VERSION 5.7 ;
  NOWIREEXTENSIONATPIN ON ;
  DIVIDERCHAR "/" ;
  BUSBITCHARS "[]" ;
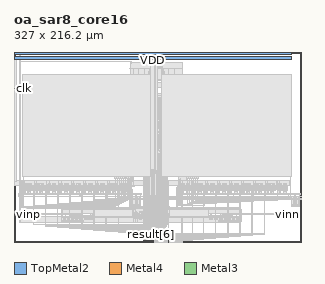
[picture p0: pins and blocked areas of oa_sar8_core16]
MACRO oa_sar8_core16
  CLASS BLOCK ;
  FOREIGN oa_sar8_core16 0.000 0.000 ;
  ORIGIN 0.000 0.000 ;
  SIZE 327.000 BY 216.200 ;
  PIN VDD
    DIRECTION INOUT ;
    USE POWER ;
    PORT
      LAYER TopMetal2 ;
        RECT 0.000 207.700 315.500 210.700 ;
    END
  END VDD
  PIN VSS
    DIRECTION INOUT ;
    USE GROUND ;
    PORT
      LAYER TopMetal2 ;
        RECT 0.000 213.200 315.500 216.200 ;
    END
  END VSS
  PIN busy
    DIRECTION OUTPUT ;
    USE SIGNAL ;
    PORT
      LAYER Metal4 ;
        RECT 158.400 0.000 158.800 1.500 ;
    END
  END busy
  PIN clk
    DIRECTION INPUT ;
    USE SIGNAL ;
    PORT
      LAYER Metal4 ;
        RECT 0.000 174.500 1.500 174.900 ;
    END
  END clk
  PIN done
    DIRECTION OUTPUT ;
    USE SIGNAL ;
    PORT
      LAYER Metal4 ;
        RECT 157.440 0.000 157.840 1.500 ;
    END
  END done
  PIN result[0]
    DIRECTION OUTPUT ;
    USE SIGNAL ;
    PORT
      LAYER Metal4 ;
        RECT 149.760 0.000 150.160 1.500 ;
    END
  END result[0]
  PIN result[1]
    DIRECTION OUTPUT ;
    USE SIGNAL ;
    PORT
      LAYER Metal4 ;
        RECT 150.720 0.000 151.120 1.500 ;
    END
  END result[1]
  PIN result[2]
    DIRECTION OUTPUT ;
    USE SIGNAL ;
    PORT
      LAYER Metal4 ;
        RECT 151.680 0.000 152.080 1.500 ;
    END
  END result[2]
  PIN result[3]
    DIRECTION OUTPUT ;
    USE SIGNAL ;
    PORT
      LAYER Metal4 ;
        RECT 152.640 0.000 153.040 1.500 ;
    END
  END result[3]
  PIN result[4]
    DIRECTION OUTPUT ;
    USE SIGNAL ;
    PORT
      LAYER Metal4 ;
        RECT 153.600 0.000 154.000 1.500 ;
    END
  END result[4]
  PIN result[5]
    DIRECTION OUTPUT ;
    USE SIGNAL ;
    PORT
      LAYER Metal4 ;
        RECT 154.560 0.000 154.960 1.500 ;
    END
  END result[5]
  PIN result[6]
    DIRECTION OUTPUT ;
    USE SIGNAL ;
    PORT
      LAYER Metal4 ;
        RECT 155.520 0.000 155.920 1.500 ;
    END
  END result[6]
  PIN result[7]
    DIRECTION OUTPUT ;
    USE SIGNAL ;
    PORT
      LAYER Metal4 ;
        RECT 156.480 0.000 156.880 1.500 ;
    END
  END result[7]
  PIN rst_n
    DIRECTION INPUT ;
    USE SIGNAL ;
    PORT
      LAYER Metal4 ;
        RECT 147.840 0.000 148.240 1.500 ;
    END
  END rst_n
  PIN start
    DIRECTION INPUT ;
    USE SIGNAL ;
    PORT
      LAYER Metal4 ;
        RECT 148.800 0.000 149.200 1.500 ;
    END
  END start
  PIN vcm
    DIRECTION INPUT ;
    USE SIGNAL ;
    PORT
      LAYER Metal4 ;
        RECT 175.400 0.000 175.800 1.500 ;
    END
  END vcm
  PIN vinn
    DIRECTION INPUT ;
    USE SIGNAL ;
    PORT
      LAYER Metal3 ;
        RECT 314.000 31.600 315.500 32.000 ;
    END
  END vinn
  PIN vinp
    DIRECTION INPUT ;
    USE SIGNAL ;
    PORT
      LAYER Metal3 ;
        RECT 0.000 31.600 1.500 32.000 ;
    END
  END vinp
  OBS
    LAYER Metal1 ;
      RECT 6.100 22.500 258.000 28.730 ;
      RECT 55.100 32.010 257.500 37.700 ;
      RECT 0.000 64.010 313.500 69.710 ;
      RECT 142.280 82.040 181.640 83.535 ;
      RECT 142.280 84.340 181.640 87.720 ;
      RECT 142.280 88.610 181.640 91.095 ;
      RECT 161.790 90.410 163.590 91.130 ;
      RECT 162.240 90.965 164.750 92.305 ;
      RECT 155.480 90.260 163.080 92.580 ;
      RECT 159.135 90.740 162.880 92.620 ;
      RECT 159.135 92.845 164.440 93.105 ;
      RECT 142.280 91.900 181.640 95.280 ;
      RECT 156.010 94.220 163.410 96.770 ;
      RECT 161.635 94.220 166.470 96.770 ;
      RECT 142.280 96.170 181.640 98.655 ;
      RECT 162.195 97.970 163.240 100.535 ;
      RECT 162.495 101.655 167.800 101.915 ;
      RECT 142.280 99.460 181.640 102.860 ;
      RECT 162.495 102.140 166.240 104.020 ;
      RECT 158.840 102.180 166.440 104.500 ;
      RECT 142.280 103.665 181.640 106.215 ;
      RECT 142.280 107.020 181.640 110.420 ;
      RECT 162.675 109.345 163.720 111.910 ;
      RECT 159.210 113.070 160.530 113.745 ;
      RECT 164.490 113.070 165.810 113.745 ;
      RECT 170.590 113.070 171.910 113.745 ;
      RECT 142.280 111.225 181.640 113.820 ;
      RECT 162.115 113.420 163.765 115.380 ;
      RECT 142.600 113.050 142.900 115.680 ;
      RECT 148.380 113.050 148.680 115.680 ;
      RECT 149.320 113.050 149.620 115.680 ;
      RECT 153.160 113.050 153.460 115.680 ;
      RECT 177.640 113.050 177.940 115.680 ;
      RECT 179.560 113.050 179.860 115.680 ;
      RECT 160.270 113.070 161.170 115.760 ;
      RECT 165.550 113.070 166.450 115.760 ;
      RECT 169.950 113.070 170.850 115.760 ;
      RECT 142.280 114.580 181.640 117.980 ;
      RECT 162.725 118.050 163.040 118.630 ;
      RECT 162.270 116.800 163.170 119.490 ;
      RECT 162.570 120.630 163.890 121.305 ;
      RECT 142.280 118.740 181.640 121.870 ;
      RECT 162.680 121.490 163.040 122.070 ;
      RECT 142.280 121.530 181.640 125.540 ;
      RECT 160.330 124.460 165.165 127.010 ;
      RECT 142.280 126.300 181.640 129.430 ;
      RECT 142.280 129.095 181.640 133.710 ;
      RECT 160.905 132.140 163.230 134.570 ;
      RECT 142.280 133.370 181.640 136.390 ;
      RECT 161.610 135.750 162.930 136.425 ;
      RECT 162.670 135.750 163.570 138.440 ;
      RECT 162.725 140.480 163.120 140.810 ;
      RECT 142.280 137.260 181.640 141.265 ;
      RECT 162.655 139.560 163.665 141.740 ;
      RECT 142.280 140.930 181.640 143.970 ;
      RECT 162.610 143.350 164.935 145.780 ;
      RECT 142.280 144.840 181.640 148.200 ;
      RECT 142.280 149.090 181.640 151.610 ;
      RECT 161.650 150.780 163.570 152.370 ;
      RECT 162.730 151.140 163.230 153.200 ;
      RECT 162.280 152.980 163.560 153.580 ;
      RECT 142.280 152.400 181.640 156.390 ;
      RECT 142.280 156.050 181.640 159.665 ;
      RECT 142.280 159.330 181.640 163.950 ;
      RECT 142.280 163.615 181.640 167.230 ;
      RECT 142.280 166.890 181.640 169.420 ;
      RECT 132.100 175.500 192.100 181.390 ;
      RECT 161.400 198.400 162.800 198.680 ;
      RECT 161.400 199.080 162.800 199.360 ;
      RECT 161.400 199.760 162.800 200.040 ;
      RECT 160.780 197.850 163.280 200.590 ;
      RECT 132.100 184.890 192.100 203.700 ;
      RECT 169.880 158.300 177.480 160.620 ;
      RECT 171.800 158.645 173.585 159.560 ;
      RECT 175.130 159.380 175.670 159.700 ;
      RECT 166.605 159.205 166.880 159.740 ;
      RECT 167.455 159.205 167.860 159.740 ;
      RECT 168.050 159.360 168.395 159.740 ;
      RECT 163.220 159.365 163.570 159.750 ;
      RECT 163.760 159.365 164.140 159.750 ;
      RECT 164.665 159.365 165.075 159.750 ;
      RECT 168.935 158.930 169.280 159.750 ;
      RECT 170.825 159.370 171.430 159.825 ;
      RECT 174.405 158.780 176.205 160.190 ;
      RECT 176.640 159.005 179.150 160.345 ;
      RECT 177.900 158.485 179.515 160.355 ;
      RECT 176.190 158.450 177.990 159.170 ;
      RECT 173.535 158.780 177.280 160.660 ;
      RECT 170.265 159.360 172.795 160.760 ;
      RECT 179.955 158.450 181.000 161.015 ;
      RECT 180.955 158.450 181.390 161.015 ;
      RECT 166.605 158.580 167.375 161.020 ;
      RECT 167.115 159.940 168.395 161.020 ;
      RECT 163.710 158.490 164.990 161.090 ;
      RECT 168.890 158.450 173.345 161.100 ;
      RECT 173.535 160.885 178.840 161.145 ;
      RECT 171.615 162.135 176.920 162.395 ;
      RECT 173.210 163.580 173.750 163.900 ;
      RECT 168.905 163.455 169.510 163.910 ;
      RECT 168.345 162.520 170.875 163.920 ;
      RECT 162.780 163.520 163.070 163.950 ;
      RECT 164.490 163.440 164.960 164.020 ;
      RECT 165.165 163.470 165.460 164.020 ;
      RECT 174.720 162.935 177.230 164.275 ;
      RECT 163.800 162.245 166.045 164.330 ;
      RECT 167.015 163.530 167.360 164.350 ;
      RECT 171.615 162.620 175.360 164.500 ;
      RECT 172.485 163.090 174.285 164.500 ;
      RECT 169.880 163.720 171.665 164.635 ;
      RECT 165.840 162.245 166.465 164.650 ;
      RECT 175.980 162.925 177.595 164.795 ;
      RECT 166.970 162.180 171.425 164.830 ;
      RECT 174.270 164.110 176.070 164.830 ;
      RECT 178.035 162.265 179.080 164.830 ;
      RECT 179.035 162.265 179.470 164.830 ;
      RECT 163.750 164.330 164.990 164.945 ;
      RECT 167.960 162.660 175.560 164.980 ;
      RECT 167.930 178.840 170.830 179.120 ;
      RECT 167.930 179.360 170.830 179.640 ;
      RECT 176.330 179.360 178.230 179.640 ;
      RECT 182.930 179.360 184.830 179.640 ;
      RECT 167.930 179.880 170.830 180.160 ;
      RECT 176.330 179.880 178.230 180.160 ;
      RECT 182.930 179.880 184.830 180.160 ;
      RECT 167.310 178.290 171.310 180.710 ;
      RECT 175.710 178.810 178.710 180.710 ;
      RECT 182.310 178.810 185.310 180.710 ;
      RECT 168.210 186.120 170.110 186.400 ;
      RECT 168.210 186.640 170.110 186.920 ;
      RECT 168.210 187.160 170.110 187.440 ;
      RECT 167.590 185.570 170.590 187.990 ;
      RECT 168.210 192.100 169.110 192.380 ;
      RECT 168.210 192.630 169.110 192.910 ;
      RECT 168.210 193.160 169.110 193.440 ;
      RECT 167.730 191.550 169.680 193.990 ;
      RECT 169.880 135.620 177.480 137.940 ;
      RECT 167.560 147.020 168.840 147.620 ;
      RECT 165.550 147.040 166.450 149.730 ;
      RECT 168.400 148.045 168.820 148.515 ;
      RECT 167.560 147.860 167.860 148.530 ;
      RECT 170.200 148.450 171.380 148.780 ;
      RECT 164.600 148.290 164.960 148.870 ;
      RECT 165.160 148.290 165.440 148.870 ;
      RECT 165.680 148.290 165.995 148.870 ;
      RECT 166.920 148.230 167.370 148.970 ;
      RECT 163.135 147.120 164.145 149.300 ;
      RECT 167.890 147.400 168.390 149.460 ;
      RECT 170.410 147.140 175.245 149.690 ;
      RECT 173.470 147.140 180.870 149.690 ;
      RECT 164.490 149.055 165.810 149.730 ;
      RECT 163.680 148.040 164.075 148.370 ;
      RECT 162.760 147.120 163.060 149.750 ;
      RECT 167.550 148.230 169.470 149.820 ;
      RECT 176.190 150.890 177.990 151.610 ;
      RECT 171.800 151.085 173.585 152.000 ;
      RECT 175.130 151.820 175.670 152.140 ;
      RECT 165.175 151.820 165.490 152.150 ;
      RECT 166.620 151.800 166.950 152.170 ;
      RECT 168.060 151.800 168.410 152.170 ;
      RECT 168.935 151.370 169.280 152.190 ;
      RECT 170.825 151.810 171.430 152.265 ;
      RECT 163.750 151.630 164.200 152.370 ;
      RECT 174.405 151.220 176.205 152.630 ;
      RECT 163.260 152.070 163.560 152.740 ;
      RECT 176.640 151.445 179.150 152.785 ;
      RECT 177.900 150.925 179.515 152.795 ;
      RECT 169.880 150.740 177.480 153.060 ;
      RECT 173.535 151.220 177.280 153.100 ;
      RECT 167.530 151.350 168.430 153.180 ;
      RECT 170.265 151.800 172.795 153.200 ;
      RECT 179.955 150.890 181.000 153.455 ;
      RECT 180.955 150.890 181.390 153.455 ;
      RECT 166.620 150.905 167.345 153.460 ;
      RECT 164.715 150.910 164.945 153.475 ;
      RECT 168.890 150.890 173.345 153.540 ;
      RECT 173.535 153.325 178.840 153.585 ;
      RECT 173.535 154.575 178.840 154.835 ;
      RECT 163.735 156.010 164.050 156.340 ;
      RECT 168.055 156.010 168.370 156.340 ;
      RECT 175.130 156.020 175.670 156.340 ;
      RECT 170.825 155.895 171.430 156.350 ;
      RECT 170.265 154.960 172.795 156.360 ;
      RECT 164.600 155.850 164.960 156.430 ;
      RECT 165.160 155.850 165.440 156.430 ;
      RECT 165.680 155.850 165.995 156.430 ;
      RECT 176.640 155.375 179.150 156.715 ;
      RECT 168.935 155.970 169.280 156.790 ;
      RECT 173.535 155.060 177.280 156.940 ;
      RECT 174.405 155.530 176.205 156.940 ;
      RECT 171.800 156.160 173.585 157.075 ;
      RECT 177.900 155.365 179.515 157.235 ;
      RECT 163.275 154.685 163.505 157.250 ;
      RECT 167.595 154.685 167.825 157.250 ;
      RECT 168.890 154.620 173.345 157.270 ;
      RECT 176.190 156.550 177.990 157.270 ;
      RECT 179.955 154.705 181.000 157.270 ;
      RECT 180.955 154.705 181.390 157.270 ;
      RECT 164.490 156.615 165.810 157.290 ;
      RECT 165.550 154.600 166.450 157.290 ;
      RECT 169.880 155.100 177.480 157.420 ;
      RECT 170.265 144.240 172.795 145.640 ;
      RECT 179.955 143.330 181.000 145.895 ;
      RECT 180.955 143.330 181.390 145.895 ;
      RECT 166.110 143.370 167.390 145.970 ;
      RECT 168.890 143.330 173.345 145.980 ;
      RECT 173.535 145.765 178.840 146.025 ;
      RECT 171.800 135.965 173.585 136.880 ;
      RECT 175.130 136.700 175.670 137.020 ;
      RECT 164.515 136.680 164.985 137.050 ;
      RECT 168.935 136.250 169.280 137.070 ;
      RECT 166.000 136.580 166.415 137.100 ;
      RECT 165.510 136.210 166.895 137.100 ;
      RECT 170.825 136.690 171.430 137.145 ;
      RECT 162.800 136.610 163.115 137.190 ;
      RECT 174.405 136.100 176.205 137.510 ;
      RECT 176.640 136.325 179.150 137.665 ;
      RECT 177.900 135.805 179.515 137.675 ;
      RECT 176.190 135.770 177.990 136.490 ;
      RECT 173.535 136.100 177.280 137.980 ;
      RECT 170.265 136.680 172.795 138.080 ;
      RECT 165.165 135.790 168.100 138.125 ;
      RECT 179.955 135.770 181.000 138.335 ;
      RECT 180.955 135.770 181.390 138.335 ;
      RECT 168.015 135.750 168.470 138.380 ;
      RECT 168.890 135.770 173.345 138.420 ;
      RECT 173.535 138.205 178.840 138.465 ;
      RECT 164.175 135.980 167.600 138.475 ;
      RECT 168.520 139.460 169.800 140.060 ;
      RECT 171.840 140.480 172.235 140.810 ;
      RECT 168.540 140.485 168.960 140.955 ;
      RECT 169.500 140.300 169.800 140.970 ;
      RECT 176.610 140.870 176.960 141.205 ;
      RECT 177.200 140.870 177.550 141.205 ;
      RECT 178.140 140.890 178.475 141.220 ;
      RECT 179.040 140.890 179.370 141.220 ;
      RECT 180.030 140.890 180.345 141.220 ;
      RECT 173.320 140.840 173.650 141.270 ;
      RECT 174.300 140.840 174.590 141.270 ;
      RECT 165.590 140.870 165.980 141.305 ;
      RECT 169.990 140.670 170.440 141.410 ;
      RECT 165.020 139.580 166.515 141.600 ;
      RECT 176.100 140.890 176.505 141.600 ;
      RECT 171.295 139.560 172.305 141.740 ;
      RECT 168.970 139.840 169.470 141.900 ;
      RECT 164.485 139.580 164.985 142.020 ;
      RECT 175.560 140.890 176.025 142.020 ;
      RECT 175.180 139.515 177.010 142.110 ;
      RECT 173.320 139.580 174.090 142.120 ;
      RECT 180.575 139.565 180.805 142.130 ;
      RECT 178.150 139.580 178.865 142.135 ;
      RECT 163.740 139.560 164.040 142.190 ;
      RECT 170.920 139.560 171.220 142.190 ;
      RECT 167.890 140.670 169.810 142.260 ;
      RECT 165.980 141.780 166.655 142.335 ;
      RECT 176.190 143.330 177.990 144.050 ;
      RECT 171.800 143.525 173.585 144.440 ;
      RECT 175.130 144.260 175.670 144.580 ;
      RECT 165.620 144.245 165.970 144.630 ;
      RECT 166.160 144.245 166.540 144.630 ;
      RECT 167.065 144.245 167.475 144.630 ;
      RECT 168.935 143.810 169.280 144.630 ;
      RECT 163.250 144.245 163.580 144.640 ;
      RECT 163.760 144.245 164.230 144.640 ;
      RECT 164.485 144.245 165.025 144.640 ;
      RECT 170.825 144.250 171.430 144.705 ;
      RECT 174.405 143.660 176.205 145.070 ;
      RECT 176.640 143.885 179.150 145.225 ;
      RECT 177.900 143.365 179.515 145.235 ;
      RECT 169.880 143.180 177.480 145.500 ;
      RECT 173.535 143.660 177.280 145.540 ;
      RECT 171.320 133.480 173.105 134.395 ;
      RECT 177.420 132.685 179.035 134.555 ;
      RECT 163.220 132.020 163.570 134.575 ;
      RECT 168.410 131.940 172.865 134.590 ;
      RECT 175.710 133.870 177.510 134.590 ;
      RECT 179.475 132.025 180.520 134.590 ;
      RECT 180.475 132.025 180.910 134.590 ;
      RECT 169.400 132.420 177.000 134.740 ;
      RECT 167.600 129.050 167.880 129.630 ;
      RECT 168.080 129.050 168.440 129.630 ;
      RECT 175.200 129.550 175.595 129.880 ;
      RECT 179.520 129.550 179.915 129.880 ;
      RECT 177.200 129.750 177.655 130.285 ;
      RECT 169.000 128.240 169.770 130.780 ;
      RECT 174.280 128.170 174.580 130.800 ;
      RECT 174.655 128.620 175.665 130.800 ;
      RECT 178.600 128.170 178.900 130.800 ;
      RECT 178.975 128.620 179.985 130.800 ;
      RECT 166.590 128.190 167.490 130.880 ;
      RECT 176.130 128.120 176.480 130.900 ;
      RECT 176.510 128.120 178.020 130.900 ;
      RECT 173.055 131.895 178.360 132.155 ;
      RECT 174.650 133.340 175.190 133.660 ;
      RECT 170.345 133.215 170.950 133.670 ;
      RECT 169.785 132.280 172.315 133.680 ;
      RECT 176.160 132.695 178.670 134.035 ;
      RECT 168.455 133.290 168.800 134.110 ;
      RECT 173.055 132.380 176.800 134.260 ;
      RECT 173.925 132.850 175.725 134.260 ;
      RECT 174.795 124.460 176.075 125.540 ;
      RECT 173.280 125.360 173.675 125.690 ;
      RECT 180.960 125.360 181.355 125.690 ;
      RECT 175.730 125.740 176.075 126.120 ;
      RECT 176.680 125.720 177.010 126.150 ;
      RECT 177.660 125.720 177.950 126.150 ;
      RECT 174.285 125.740 174.560 126.275 ;
      RECT 175.135 125.740 175.540 126.275 ;
      RECT 172.735 124.440 173.745 126.620 ;
      RECT 180.415 124.440 181.425 126.620 ;
      RECT 174.285 124.460 175.055 126.900 ;
      RECT 176.680 124.460 177.450 127.000 ;
      RECT 163.390 124.460 170.790 127.010 ;
      RECT 172.360 124.440 172.660 127.070 ;
      RECT 180.040 124.440 180.340 127.070 ;
      RECT 167.230 128.190 168.550 128.865 ;
      RECT 177.025 129.115 177.440 129.515 ;
      RECT 169.000 129.090 169.330 129.520 ;
      RECT 169.980 129.090 170.270 129.520 ;
      RECT 167.045 129.050 167.360 129.630 ;
      RECT 163.760 118.050 164.120 118.630 ;
      RECT 177.185 118.140 177.600 118.660 ;
      RECT 169.485 118.180 169.760 118.715 ;
      RECT 170.335 118.180 170.740 118.715 ;
      RECT 172.845 118.180 173.120 118.715 ;
      RECT 173.695 118.180 174.100 118.715 ;
      RECT 176.705 118.140 178.090 119.030 ;
      RECT 176.000 116.765 179.425 119.260 ;
      RECT 164.620 116.900 168.020 119.340 ;
      RECT 169.485 116.900 170.255 119.340 ;
      RECT 172.845 116.900 173.615 119.340 ;
      RECT 175.500 117.115 178.435 119.450 ;
      RECT 180.075 116.885 180.305 119.450 ;
      RECT 171.440 113.930 171.800 114.510 ;
      RECT 162.910 118.815 164.230 119.490 ;
      RECT 175.130 116.860 175.585 119.490 ;
      RECT 178.560 114.430 178.955 114.760 ;
      RECT 180.480 114.430 180.875 114.760 ;
      RECT 177.180 121.580 177.515 121.910 ;
      RECT 178.080 121.580 178.410 121.910 ;
      RECT 166.070 121.560 166.420 121.930 ;
      RECT 167.530 121.560 167.860 121.930 ;
      RECT 174.765 121.405 175.040 121.940 ;
      RECT 175.615 121.405 176.020 121.940 ;
      RECT 176.210 121.560 176.555 121.940 ;
      RECT 168.530 121.530 168.820 121.960 ;
      RECT 170.405 113.930 170.720 114.510 ;
      RECT 169.470 121.530 169.800 121.960 ;
      RECT 162.800 114.030 163.165 114.335 ;
      RECT 163.240 121.490 163.520 122.070 ;
      RECT 163.760 121.490 164.075 122.070 ;
      RECT 166.050 121.110 166.950 122.940 ;
      RECT 167.135 120.665 167.860 123.220 ;
      RECT 169.030 120.680 169.800 123.220 ;
      RECT 174.765 120.780 175.545 123.220 ;
      RECT 175.275 122.140 176.555 123.220 ;
      RECT 177.190 120.665 177.905 123.220 ;
      RECT 163.630 120.630 164.530 123.320 ;
      RECT 176.690 114.000 177.035 114.380 ;
      RECT 163.165 113.110 164.120 115.660 ;
      RECT 165.640 116.900 167.430 117.555 ;
      RECT 167.615 113.110 167.845 115.675 ;
      RECT 164.600 113.930 164.960 114.510 ;
      RECT 167.120 118.160 167.680 118.490 ;
      RECT 164.610 118.160 164.985 118.505 ;
      RECT 165.130 116.900 166.410 117.500 ;
      RECT 178.015 113.500 179.025 115.680 ;
      RECT 179.935 113.500 180.945 115.680 ;
      RECT 174.300 113.970 174.590 114.400 ;
      RECT 173.320 113.970 173.650 114.400 ;
      RECT 165.160 113.930 165.440 114.510 ;
      RECT 175.755 114.580 177.035 115.660 ;
      RECT 167.070 114.020 167.385 114.350 ;
      RECT 173.320 113.120 174.090 115.660 ;
      RECT 169.995 116.900 171.275 117.980 ;
      RECT 165.175 118.160 165.720 118.505 ;
      RECT 176.095 113.845 176.500 114.380 ;
      RECT 175.245 113.845 175.520 114.380 ;
      RECT 165.680 113.930 165.995 114.510 ;
      RECT 175.245 113.220 176.015 115.660 ;
      RECT 166.620 118.120 166.940 118.620 ;
      RECT 170.960 113.930 171.240 114.510 ;
      RECT 173.355 116.900 174.635 117.980 ;
      RECT 163.280 118.050 163.560 118.630 ;
      RECT 165.900 118.160 166.400 118.525 ;
      RECT 180.535 118.210 180.850 118.540 ;
      RECT 170.930 118.180 171.275 118.560 ;
      RECT 174.290 118.180 174.635 118.560 ;
      RECT 178.615 118.190 179.085 118.560 ;
      RECT 156.860 158.265 157.535 158.820 ;
      RECT 146.440 158.300 154.040 160.620 ;
      RECT 150.335 158.645 152.120 159.560 ;
      RECT 148.250 159.380 148.790 159.700 ;
      RECT 156.470 159.295 156.860 159.730 ;
      RECT 154.640 158.930 154.985 159.750 ;
      RECT 158.430 159.335 158.720 159.760 ;
      RECT 158.960 159.335 159.260 159.760 ;
      RECT 159.440 159.335 159.740 159.760 ;
      RECT 152.490 159.370 153.095 159.825 ;
      RECT 147.715 158.780 149.515 160.190 ;
      RECT 144.770 159.005 147.280 160.345 ;
      RECT 144.405 158.485 146.020 160.355 ;
      RECT 145.930 158.450 147.730 159.170 ;
      RECT 146.640 158.780 150.385 160.660 ;
      RECT 158.080 158.805 160.395 160.740 ;
      RECT 151.125 159.360 153.655 160.760 ;
      RECT 142.530 158.450 142.965 161.015 ;
      RECT 142.920 158.450 143.965 161.015 ;
      RECT 155.365 158.580 155.865 161.020 ;
      RECT 155.900 159.000 157.395 161.020 ;
      RECT 159.290 158.490 160.770 161.020 ;
      RECT 150.575 158.450 155.030 161.100 ;
      RECT 145.080 160.885 150.385 161.145 ;
      RECT 147.135 162.135 152.440 162.395 ;
      RECT 148.730 163.580 149.270 163.900 ;
      RECT 157.020 163.570 157.300 163.905 ;
      RECT 157.980 163.570 158.260 163.905 ;
      RECT 158.460 163.570 158.740 163.905 ;
      RECT 144.425 163.455 145.030 163.910 ;
      RECT 143.865 162.520 146.395 163.920 ;
      RECT 159.420 163.550 159.750 163.920 ;
      RECT 160.860 163.550 161.210 163.920 ;
      RECT 161.800 163.520 162.130 163.950 ;
      RECT 150.240 162.935 152.750 164.275 ;
      RECT 142.535 163.530 142.880 164.350 ;
      RECT 160.330 162.540 161.230 164.370 ;
      RECT 147.135 162.620 150.880 164.500 ;
      RECT 148.005 163.090 149.805 164.500 ;
      RECT 145.400 163.720 147.185 164.635 ;
      RECT 151.500 162.925 153.115 164.795 ;
      RECT 157.535 162.290 158.905 164.800 ;
      RECT 161.800 162.260 162.570 164.800 ;
      RECT 159.420 162.260 160.120 164.815 ;
      RECT 142.490 162.180 146.945 164.830 ;
      RECT 149.790 164.110 151.590 164.830 ;
      RECT 153.555 162.265 154.600 164.830 ;
      RECT 154.555 162.265 154.990 164.830 ;
      RECT 143.480 162.660 151.080 164.980 ;
      RECT 147.900 166.935 148.180 167.270 ;
      RECT 148.860 166.935 149.140 167.270 ;
      RECT 149.340 166.935 149.620 167.270 ;
      RECT 152.710 166.940 153.040 167.270 ;
      RECT 153.605 166.940 153.940 167.270 ;
      RECT 150.300 166.920 150.630 167.290 ;
      RECT 151.740 166.920 152.090 167.290 ;
      RECT 151.210 166.470 152.110 168.300 ;
      RECT 148.415 166.040 149.785 168.550 ;
      RECT 150.300 166.025 151.000 168.580 ;
      RECT 153.215 166.025 153.930 168.580 ;
      RECT 153.370 178.840 156.270 179.120 ;
      RECT 139.370 179.360 141.270 179.640 ;
      RECT 145.970 179.360 147.870 179.640 ;
      RECT 153.370 179.360 156.270 179.640 ;
      RECT 139.370 179.880 141.270 180.160 ;
      RECT 145.970 179.880 147.870 180.160 ;
      RECT 153.370 179.880 156.270 180.160 ;
      RECT 138.890 178.810 141.890 180.710 ;
      RECT 145.490 178.810 148.490 180.710 ;
      RECT 152.890 178.290 156.890 180.710 ;
      RECT 154.090 186.120 155.990 186.400 ;
      RECT 154.090 186.640 155.990 186.920 ;
      RECT 154.090 187.160 155.990 187.440 ;
      RECT 153.610 185.570 156.610 187.990 ;
      RECT 155.090 192.100 155.990 192.380 ;
      RECT 155.090 192.630 155.990 192.910 ;
      RECT 155.090 193.160 155.990 193.440 ;
      RECT 154.520 191.550 156.470 193.990 ;
      RECT 146.440 135.620 154.040 137.940 ;
      RECT 150.015 147.015 155.320 147.275 ;
      RECT 145.370 147.060 149.825 149.710 ;
      RECT 151.610 148.460 152.150 148.780 ;
      RECT 147.305 148.335 147.910 148.790 ;
      RECT 146.745 147.400 149.275 148.800 ;
      RECT 159.380 148.400 159.680 148.825 ;
      RECT 159.860 148.305 160.185 148.825 ;
      RECT 160.400 148.400 160.690 148.825 ;
      RECT 153.120 147.815 155.630 149.155 ;
      RECT 145.415 148.410 145.760 149.230 ;
      RECT 158.725 147.420 161.040 149.355 ;
      RECT 150.015 147.500 153.760 149.380 ;
      RECT 150.885 147.970 152.685 149.380 ;
      RECT 148.280 148.600 150.065 149.515 ;
      RECT 158.350 147.140 159.830 149.670 ;
      RECT 154.380 147.805 155.995 149.675 ;
      RECT 144.075 147.125 144.305 149.690 ;
      RECT 144.535 148.450 144.850 148.780 ;
      RECT 152.670 148.990 154.470 149.710 ;
      RECT 156.435 147.145 157.480 149.710 ;
      RECT 157.435 147.145 157.870 149.710 ;
      RECT 146.360 147.540 153.960 149.860 ;
      RECT 144.030 151.820 144.345 152.150 ;
      RECT 157.340 151.820 158.520 152.150 ;
      RECT 159.920 151.795 160.335 152.195 ;
      RECT 162.300 152.085 162.720 152.555 ;
      RECT 146.400 152.230 146.795 152.560 ;
      RECT 159.705 152.430 160.160 152.965 ;
      RECT 147.850 150.910 155.250 153.460 ;
      RECT 153.475 150.910 158.310 153.460 ;
      RECT 144.575 150.910 144.805 153.475 ;
      RECT 145.480 150.850 145.780 153.480 ;
      RECT 145.855 151.300 146.865 153.480 ;
      RECT 159.340 150.800 160.850 153.580 ;
      RECT 160.880 150.800 161.230 153.580 ;
      RECT 148.840 154.580 150.120 155.180 ;
      RECT 149.680 155.605 150.100 156.075 ;
      RECT 148.840 155.420 149.140 156.090 ;
      RECT 153.035 156.025 153.440 156.330 ;
      RECT 153.680 156.025 154.045 156.330 ;
      RECT 155.550 156.010 155.865 156.340 ;
      RECT 158.940 156.010 159.220 156.345 ;
      RECT 159.900 156.010 160.180 156.345 ;
      RECT 160.380 156.010 160.660 156.345 ;
      RECT 151.240 155.960 151.570 156.390 ;
      RECT 152.220 155.960 152.510 156.390 ;
      RECT 148.200 155.790 148.650 156.530 ;
      RECT 152.995 154.980 154.645 156.940 ;
      RECT 149.170 154.960 149.670 157.020 ;
      RECT 151.240 154.700 152.010 157.240 ;
      RECT 159.545 154.730 160.825 157.240 ;
      RECT 154.045 154.700 155.000 157.250 ;
      RECT 156.095 154.685 156.325 157.250 ;
      RECT 148.830 155.790 150.750 157.380 ;
      RECT 147.135 145.765 152.440 146.025 ;
      RECT 155.525 140.890 155.860 141.220 ;
      RECT 161.815 140.890 162.130 141.220 ;
      RECT 145.930 135.770 147.730 136.490 ;
      RECT 148.805 140.730 149.120 141.310 ;
      RECT 149.360 140.730 149.640 141.310 ;
      RECT 150.335 135.965 152.120 136.880 ;
      RECT 149.840 140.730 150.200 141.310 ;
      RECT 148.250 136.700 148.790 137.020 ;
      RECT 159.420 136.700 159.755 137.030 ;
      RECT 160.320 136.700 160.650 137.030 ;
      RECT 144.885 139.580 145.905 141.855 ;
      RECT 154.640 136.250 154.985 137.070 ;
      RECT 145.305 139.615 146.915 141.915 ;
      RECT 155.490 136.735 155.865 137.080 ;
      RECT 156.055 136.735 156.600 137.080 ;
      RECT 156.780 136.715 157.280 137.080 ;
      RECT 158.000 136.750 158.560 137.080 ;
      RECT 143.595 139.565 143.825 142.130 ;
      RECT 161.355 139.565 161.585 142.130 ;
      RECT 155.135 139.580 155.850 142.135 ;
      RECT 148.350 139.480 149.250 142.170 ;
      RECT 157.500 136.620 157.820 137.120 ;
      RECT 148.990 141.495 150.310 142.170 ;
      RECT 152.490 136.690 153.095 137.145 ;
      RECT 161.720 136.610 162.080 137.190 ;
      RECT 162.280 136.610 162.560 137.190 ;
      RECT 147.440 141.775 147.790 142.335 ;
      RECT 147.715 136.100 149.515 137.510 ;
      RECT 144.770 136.325 147.280 137.665 ;
      RECT 149.790 143.330 151.590 144.050 ;
      RECT 144.405 135.805 146.020 137.675 ;
      RECT 145.400 143.525 147.185 144.440 ;
      RECT 142.490 143.330 146.945 145.980 ;
      RECT 148.730 144.260 149.270 144.580 ;
      RECT 156.060 144.260 156.395 144.590 ;
      RECT 156.960 144.260 157.290 144.590 ;
      RECT 157.950 144.260 158.265 144.590 ;
      RECT 160.855 144.260 161.170 144.590 ;
      RECT 142.535 143.810 142.880 144.630 ;
      RECT 146.640 136.100 150.385 137.980 ;
      RECT 151.125 136.680 153.655 138.080 ;
      RECT 142.530 135.770 142.965 138.335 ;
      RECT 142.920 135.770 143.965 138.335 ;
      RECT 144.425 144.250 145.030 144.705 ;
      RECT 148.005 143.660 149.805 145.070 ;
      RECT 150.240 143.885 152.750 145.225 ;
      RECT 151.500 143.365 153.115 145.235 ;
      RECT 143.480 143.180 151.080 145.500 ;
      RECT 155.500 135.900 158.900 138.340 ;
      RECT 156.010 137.740 157.290 138.340 ;
      RECT 156.520 137.685 158.310 138.340 ;
      RECT 147.135 143.660 150.880 145.540 ;
      RECT 159.430 135.785 160.145 138.340 ;
      RECT 150.575 135.770 155.030 138.420 ;
      RECT 143.865 144.240 146.395 145.640 ;
      RECT 145.080 138.205 150.385 138.465 ;
      RECT 153.555 143.330 154.600 145.895 ;
      RECT 154.555 143.330 154.990 145.895 ;
      RECT 146.535 139.615 147.855 140.530 ;
      RECT 156.070 143.345 156.785 145.900 ;
      RECT 162.270 143.345 162.620 145.900 ;
      RECT 158.495 143.350 158.725 145.915 ;
      RECT 160.395 143.350 160.625 145.915 ;
      RECT 146.435 140.740 146.730 141.215 ;
      RECT 146.930 140.740 147.225 141.215 ;
      RECT 144.055 140.890 144.370 141.220 ;
      RECT 154.630 140.890 154.960 141.220 ;
      RECT 145.950 124.360 146.850 127.050 ;
      RECT 148.300 124.340 149.810 127.120 ;
      RECT 149.840 124.340 150.190 127.120 ;
      RECT 143.095 125.770 143.410 126.100 ;
      RECT 142.600 132.000 142.900 134.630 ;
      RECT 145.000 132.000 145.300 134.630 ;
      RECT 160.120 125.770 161.300 126.100 ;
      RECT 147.665 134.220 148.340 134.775 ;
      RECT 152.210 125.740 152.555 126.120 ;
      RECT 153.125 125.740 153.470 126.120 ;
      RECT 161.790 129.090 162.120 129.520 ;
      RECT 142.490 128.210 146.945 130.860 ;
      RECT 148.880 125.725 149.295 126.125 ;
      RECT 144.050 125.720 144.340 126.150 ;
      RECT 144.990 125.720 145.320 126.150 ;
      RECT 146.405 125.610 146.720 126.190 ;
      RECT 147.135 130.645 152.440 130.905 ;
      RECT 146.960 125.610 147.240 126.190 ;
      RECT 147.440 125.610 147.800 126.190 ;
      RECT 155.045 132.020 156.325 133.100 ;
      RECT 143.520 132.920 143.915 133.250 ;
      RECT 156.330 125.640 156.800 126.220 ;
      RECT 145.920 132.920 146.315 133.250 ;
      RECT 157.005 125.670 157.300 126.220 ;
      RECT 158.940 129.140 159.275 129.470 ;
      RECT 159.840 129.140 160.170 129.470 ;
      RECT 150.765 125.740 151.040 126.275 ;
      RECT 151.615 125.740 152.020 126.275 ;
      RECT 142.535 128.690 142.880 129.510 ;
      RECT 157.885 133.290 158.295 133.675 ;
      RECT 153.660 125.740 154.065 126.275 ;
      RECT 154.640 125.740 154.915 126.275 ;
      RECT 158.820 133.290 159.200 133.675 ;
      RECT 159.390 133.290 159.740 133.675 ;
      RECT 160.815 133.280 161.355 133.675 ;
      RECT 155.640 124.445 157.885 126.530 ;
      RECT 161.610 133.280 162.080 133.675 ;
      RECT 144.425 129.130 145.030 129.585 ;
      RECT 148.005 128.540 149.805 129.950 ;
      RECT 157.680 124.445 158.305 126.850 ;
      RECT 150.240 128.765 152.750 130.105 ;
      RECT 151.500 128.245 153.115 130.115 ;
      RECT 162.260 133.280 162.590 133.675 ;
      RECT 155.045 133.300 155.390 133.680 ;
      RECT 160.850 129.090 161.140 129.520 ;
      RECT 150.765 124.460 151.535 126.900 ;
      RECT 143.480 128.060 151.080 130.380 ;
      RECT 150.290 133.280 150.580 133.710 ;
      RECT 154.145 124.460 154.915 126.900 ;
      RECT 144.550 124.460 145.320 127.000 ;
      RECT 142.635 124.445 142.865 127.010 ;
      RECT 151.230 133.280 151.560 133.710 ;
      RECT 147.135 128.540 150.880 130.420 ;
      RECT 157.970 131.950 159.250 134.550 ;
      RECT 143.865 129.120 146.395 130.520 ;
      RECT 146.590 126.375 147.910 127.050 ;
      RECT 148.340 133.310 148.730 133.745 ;
      RECT 155.580 133.300 155.985 133.835 ;
      RECT 156.560 133.300 156.835 133.835 ;
      RECT 153.555 128.210 154.600 130.775 ;
      RECT 150.790 132.020 151.560 134.560 ;
      RECT 147.805 132.020 149.300 134.040 ;
      RECT 145.400 128.405 147.185 129.320 ;
      RECT 148.730 129.140 149.270 129.460 ;
      RECT 155.590 126.530 156.830 127.145 ;
      RECT 142.975 132.000 143.985 134.180 ;
      RECT 145.375 132.000 146.385 134.180 ;
      RECT 149.790 128.210 151.590 128.930 ;
      RECT 154.555 128.210 154.990 130.775 ;
      RECT 148.665 124.955 149.120 125.490 ;
      RECT 158.950 128.225 159.665 130.780 ;
      RECT 151.275 124.460 152.555 125.540 ;
      RECT 161.350 128.240 162.120 130.780 ;
      RECT 153.125 124.460 154.405 125.540 ;
      RECT 149.335 132.020 149.835 134.460 ;
      RECT 156.055 132.020 156.835 134.460 ;
      RECT 150.240 114.430 150.635 114.760 ;
      RECT 145.970 121.530 146.260 121.960 ;
      RECT 142.975 113.500 143.985 115.680 ;
      RECT 160.400 113.930 160.715 114.510 ;
      RECT 160.735 116.880 161.745 119.060 ;
      RECT 146.470 120.680 147.240 123.220 ;
      RECT 142.920 116.905 143.965 119.470 ;
      RECT 157.990 113.120 158.760 115.660 ;
      RECT 147.880 120.680 148.650 123.220 ;
      RECT 145.930 118.750 147.730 119.470 ;
      RECT 147.715 117.730 149.515 119.140 ;
      RECT 155.085 120.780 155.865 123.220 ;
      RECT 147.365 114.430 147.760 114.760 ;
      RECT 144.770 117.575 147.280 118.915 ;
      RECT 155.370 118.815 156.690 119.490 ;
      RECT 157.500 121.575 157.780 121.910 ;
      RECT 156.530 121.560 156.875 121.940 ;
      RECT 147.295 113.500 148.305 115.680 ;
      RECT 161.765 121.580 162.100 121.910 ;
      RECT 158.590 118.815 159.910 119.490 ;
      RECT 155.595 122.140 156.875 123.220 ;
      RECT 152.490 118.095 153.095 118.550 ;
      RECT 161.375 120.665 162.090 123.220 ;
      RECT 156.560 118.050 156.875 118.630 ;
      RECT 158.460 121.575 158.740 121.910 ;
      RECT 146.910 121.530 147.240 121.960 ;
      RECT 155.085 113.220 155.865 115.660 ;
      RECT 155.480 118.050 155.840 118.630 ;
      RECT 146.640 117.260 150.385 119.140 ;
      RECT 155.595 114.580 156.875 115.660 ;
      RECT 154.080 114.430 154.475 114.760 ;
      RECT 147.880 121.530 148.210 121.960 ;
      RECT 150.335 118.360 152.120 119.275 ;
      RECT 148.860 121.530 149.150 121.960 ;
      RECT 157.490 113.970 157.780 114.400 ;
      RECT 160.360 116.880 160.660 119.510 ;
      RECT 151.125 117.160 153.655 118.560 ;
      RECT 158.940 121.575 159.220 121.910 ;
      RECT 158.405 118.050 158.720 118.630 ;
      RECT 153.535 113.500 154.545 115.680 ;
      RECT 158.960 118.050 159.240 118.630 ;
      RECT 162.155 114.030 162.560 114.335 ;
      RECT 158.430 113.970 158.760 114.400 ;
      RECT 151.200 121.990 151.595 122.320 ;
      RECT 143.520 114.430 143.915 114.760 ;
      RECT 152.165 121.990 152.560 122.320 ;
      RECT 143.090 121.530 143.380 121.960 ;
      RECT 145.080 116.775 150.385 117.035 ;
      RECT 159.320 113.930 159.680 114.510 ;
      RECT 160.870 121.580 161.200 121.910 ;
      RECT 155.085 113.845 155.360 114.380 ;
      RECT 159.440 118.050 159.800 118.630 ;
      RECT 156.530 114.000 156.875 114.380 ;
      RECT 159.880 113.930 160.160 114.510 ;
      RECT 146.440 117.300 154.040 119.620 ;
      RECT 145.000 113.120 145.770 115.660 ;
      RECT 145.000 113.970 145.330 114.400 ;
      RECT 150.280 120.610 150.580 123.240 ;
      RECT 144.030 121.530 144.360 121.960 ;
      RECT 150.655 121.060 151.665 123.240 ;
      RECT 150.575 116.820 155.030 119.470 ;
      RECT 152.095 121.060 153.105 123.240 ;
      RECT 155.935 113.845 156.340 114.380 ;
      RECT 153.180 120.610 153.480 123.240 ;
      RECT 144.405 117.565 146.020 119.435 ;
      RECT 148.250 118.220 148.790 118.540 ;
      RECT 156.430 116.800 157.330 119.490 ;
      RECT 145.980 113.970 146.270 114.400 ;
      RECT 154.640 118.170 154.985 118.990 ;
      RECT 156.040 118.050 156.320 118.630 ;
      RECT 152.220 113.970 152.510 114.400 ;
      RECT 157.950 116.800 158.850 119.490 ;
      RECT 158.105 120.680 159.385 123.190 ;
      RECT 142.530 116.905 142.965 119.470 ;
      RECT 151.240 113.120 152.010 115.660 ;
      RECT 149.695 113.500 150.705 115.680 ;
      RECT 151.240 113.970 151.570 114.400 ;
      RECT 155.085 121.405 155.360 121.940 ;
      RECT 155.935 121.405 156.340 121.940 ;
      RECT 161.280 117.800 161.675 118.130 ;
      RECT 143.590 120.680 144.360 123.220 ;
      RECT 81.170 26.960 83.070 27.240 ;
      RECT 80.690 25.890 83.690 27.790 ;
      RECT 80.010 25.210 84.230 28.470 ;
      RECT 6.100 53.500 133.900 54.100 ;
      RECT 7.700 54.500 144.600 55.100 ;
      RECT 78.430 55.700 81.800 60.510 ;
      RECT 78.890 64.690 81.890 67.110 ;
      RECT 81.170 26.440 83.070 26.720 ;
      RECT 146.590 90.390 147.910 91.065 ;
      RECT 152.830 90.390 154.150 91.065 ;
      RECT 144.550 90.440 145.320 92.980 ;
      RECT 143.135 90.430 143.365 92.995 ;
      RECT 149.340 90.370 149.640 93.000 ;
      RECT 151.260 90.370 151.560 93.000 ;
      RECT 154.490 90.410 158.945 93.060 ;
      RECT 145.950 90.390 146.850 93.080 ;
      RECT 152.190 90.390 153.090 93.080 ;
      RECT 142.495 101.760 143.505 103.940 ;
      RECT 144.415 101.760 145.425 103.940 ;
      RECT 149.695 101.760 150.705 103.940 ;
      RECT 154.015 101.760 155.025 103.940 ;
      RECT 155.935 101.760 156.945 103.940 ;
      RECT 148.895 101.765 149.125 104.330 ;
      RECT 157.850 101.700 162.305 104.350 ;
      RECT 143.580 101.760 143.880 104.390 ;
      RECT 145.500 101.760 145.800 104.390 ;
      RECT 150.780 101.760 151.080 104.390 ;
      RECT 153.640 101.760 153.940 104.390 ;
      RECT 157.020 101.760 157.320 104.390 ;
      RECT 157.895 103.050 158.240 103.870 ;
      RECT 142.565 102.680 142.960 103.010 ;
      RECT 144.485 102.680 144.880 103.010 ;
      RECT 149.765 102.680 150.160 103.010 ;
      RECT 154.560 102.680 154.955 103.010 ;
      RECT 156.005 102.680 156.400 103.010 ;
      RECT 160.760 103.240 162.545 104.155 ;
      RECT 146.950 101.780 147.720 104.320 ;
      RECT 151.720 101.780 152.490 104.320 ;
      RECT 148.350 103.090 148.665 103.420 ;
      RECT 159.785 102.975 160.390 103.430 ;
      RECT 159.225 102.040 161.755 103.440 ;
      RECT 146.450 103.040 146.740 103.470 ;
      RECT 147.390 103.040 147.720 103.470 ;
      RECT 151.720 103.040 152.050 103.470 ;
      RECT 152.700 103.040 152.990 103.470 ;
      RECT 149.790 105.530 151.590 106.250 ;
      RECT 145.400 105.725 147.185 106.640 ;
      RECT 148.730 106.460 149.270 106.780 ;
      RECT 155.550 106.460 155.865 106.790 ;
      RECT 142.535 106.010 142.880 106.830 ;
      RECT 144.425 106.450 145.030 106.905 ;
      RECT 157.920 106.870 158.315 107.200 ;
      RECT 159.840 106.870 160.235 107.200 ;
      RECT 161.760 106.870 162.155 107.200 ;
      RECT 148.005 105.860 149.805 107.270 ;
      RECT 150.240 106.085 152.750 107.425 ;
      RECT 151.500 105.565 153.115 107.435 ;
      RECT 143.480 105.380 151.080 107.700 ;
      RECT 147.135 105.860 150.880 107.740 ;
      RECT 143.865 106.440 146.395 107.840 ;
      RECT 153.555 105.530 154.600 108.095 ;
      RECT 154.555 105.530 154.990 108.095 ;
      RECT 156.095 105.550 156.325 108.115 ;
      RECT 157.000 105.490 157.300 108.120 ;
      RECT 157.375 105.940 158.385 108.120 ;
      RECT 158.920 105.490 159.220 108.120 ;
      RECT 159.295 105.940 160.305 108.120 ;
      RECT 160.840 105.490 161.140 108.120 ;
      RECT 161.215 105.940 162.225 108.120 ;
      RECT 142.490 105.530 146.945 108.180 ;
      RECT 147.135 107.965 152.440 108.225 ;
      RECT 156.255 109.215 161.560 109.475 ;
      RECT 142.565 110.240 142.960 110.570 ;
      RECT 147.365 110.240 147.760 110.570 ;
      RECT 157.850 110.660 158.390 110.980 ;
      RECT 153.545 110.535 154.150 110.990 ;
      RECT 152.985 109.600 155.515 111.000 ;
      RECT 145.445 110.490 145.760 111.070 ;
      RECT 146.000 110.490 146.280 111.070 ;
      RECT 146.480 110.490 146.840 111.070 ;
      RECT 149.240 110.490 149.600 111.070 ;
      RECT 149.800 110.490 150.080 111.070 ;
      RECT 150.320 110.490 150.635 111.070 ;
      RECT 159.360 110.015 161.870 111.355 ;
      RECT 151.655 110.610 152.000 111.430 ;
      RECT 142.495 109.320 143.505 111.500 ;
      RECT 147.295 109.320 148.305 111.500 ;
      RECT 156.255 109.700 160.000 111.580 ;
      RECT 157.125 110.170 158.925 111.580 ;
      RECT 154.520 110.800 156.305 111.715 ;
      RECT 160.620 110.005 162.235 111.875 ;
      RECT 151.610 109.260 156.065 111.910 ;
      RECT 158.910 111.190 160.710 111.910 ;
      RECT 144.990 109.240 145.890 111.930 ;
      RECT 145.630 111.255 146.950 111.930 ;
      RECT 149.130 111.255 150.450 111.930 ;
      RECT 150.190 109.240 151.090 111.930 ;
      RECT 143.580 109.320 143.880 111.950 ;
      RECT 148.380 109.320 148.680 111.950 ;
      RECT 152.600 109.740 160.200 112.060 ;
      RECT 147.895 98.900 148.210 99.230 ;
      RECT 151.175 98.450 151.520 99.270 ;
      RECT 143.090 98.850 143.380 99.280 ;
      RECT 144.030 98.850 144.360 99.280 ;
      RECT 153.065 98.890 153.670 99.345 ;
      RECT 145.445 98.810 145.760 99.390 ;
      RECT 146.000 98.810 146.280 99.390 ;
      RECT 146.480 98.810 146.840 99.390 ;
      RECT 149.285 98.810 149.600 99.390 ;
      RECT 149.840 98.810 150.120 99.390 ;
      RECT 150.320 98.810 150.680 99.390 ;
      RECT 156.645 98.300 158.445 99.710 ;
      RECT 158.880 98.525 161.390 99.865 ;
      RECT 160.140 98.005 161.755 99.875 ;
      RECT 152.120 97.820 159.720 100.140 ;
      RECT 147.135 94.095 152.440 94.355 ;
      RECT 155.775 98.300 159.520 100.180 ;
      RECT 152.505 98.880 155.035 100.280 ;
      RECT 143.590 98.000 144.360 100.540 ;
      RECT 147.435 97.990 147.665 100.555 ;
      RECT 151.130 97.970 155.585 100.620 ;
      RECT 144.990 97.950 145.890 100.640 ;
      RECT 148.830 97.950 149.730 100.640 ;
      RECT 155.775 100.405 161.080 100.665 ;
      RECT 158.430 97.970 160.230 98.690 ;
      RECT 154.040 98.165 155.825 99.080 ;
      RECT 157.370 98.900 157.910 99.220 ;
      RECT 148.730 95.540 149.270 95.860 ;
      RECT 144.425 95.415 145.030 95.870 ;
      RECT 143.865 94.480 146.395 95.880 ;
      RECT 150.240 94.895 152.750 96.235 ;
      RECT 142.535 95.490 142.880 96.310 ;
      RECT 147.135 94.580 150.880 96.460 ;
      RECT 145.400 95.680 147.185 96.595 ;
      RECT 151.500 94.885 153.115 96.755 ;
      RECT 157.400 90.605 159.185 91.520 ;
      RECT 160.730 91.340 161.270 91.660 ;
      RECT 142.590 91.340 142.905 91.670 ;
      RECT 154.535 90.890 154.880 91.710 ;
      RECT 144.050 91.290 144.340 91.720 ;
      RECT 144.990 91.290 145.320 91.720 ;
      RECT 156.425 91.330 157.030 91.785 ;
      RECT 146.405 91.250 146.745 91.830 ;
      RECT 146.960 91.250 147.240 91.830 ;
      RECT 147.440 91.250 147.800 91.830 ;
      RECT 152.645 91.250 152.985 91.830 ;
      RECT 153.200 91.250 153.480 91.830 ;
      RECT 153.680 91.250 154.040 91.830 ;
      RECT 148.325 91.750 148.720 92.080 ;
      RECT 150.245 91.750 150.640 92.080 ;
      RECT 160.005 90.740 161.805 92.150 ;
      RECT 148.005 95.050 149.805 96.460 ;
      RECT 155.865 91.320 158.395 92.720 ;
      RECT 142.490 94.140 146.945 96.790 ;
      RECT 149.790 96.070 151.590 96.790 ;
      RECT 148.255 90.820 149.265 93.000 ;
      RECT 153.555 94.225 154.600 96.790 ;
      RECT 150.175 90.820 151.185 93.000 ;
      RECT 154.555 94.225 154.990 96.790 ;
      RECT 143.480 94.620 151.080 96.940 ;
      RECT 145.630 97.950 146.950 98.625 ;
      RECT 149.470 97.950 150.790 98.625 ;
      RECT 155.550 87.970 155.865 88.300 ;
      RECT 152.490 87.855 153.095 88.310 ;
      RECT 151.125 86.920 153.655 88.320 ;
      RECT 144.770 87.335 147.280 88.675 ;
      RECT 154.640 87.930 154.985 88.750 ;
      RECT 156.895 86.640 157.905 88.820 ;
      RECT 158.815 86.640 159.825 88.820 ;
      RECT 160.735 86.640 161.745 88.820 ;
      RECT 147.715 87.490 149.515 88.900 ;
      RECT 146.640 87.020 150.385 88.900 ;
      RECT 150.335 88.120 152.120 89.035 ;
      RECT 144.405 87.325 146.020 89.195 ;
      RECT 156.095 86.645 156.325 89.210 ;
      RECT 142.530 86.665 142.965 89.230 ;
      RECT 142.920 86.665 143.965 89.230 ;
      RECT 145.930 88.510 147.730 89.230 ;
      RECT 150.575 86.580 155.030 89.230 ;
      RECT 157.980 86.640 158.280 89.270 ;
      RECT 159.900 86.640 160.200 89.270 ;
      RECT 161.820 86.640 162.120 89.270 ;
      RECT 146.440 87.060 154.040 89.380 ;
      RECT 152.670 82.850 154.470 83.570 ;
      RECT 148.280 83.045 150.065 83.960 ;
      RECT 151.610 83.780 152.150 84.100 ;
      RECT 145.415 83.330 145.760 84.150 ;
      RECT 143.570 83.730 143.860 84.160 ;
      RECT 144.510 83.730 144.840 84.160 ;
      RECT 158.930 83.730 159.220 84.160 ;
      RECT 159.870 83.730 160.200 84.160 ;
      RECT 160.850 83.730 161.140 84.160 ;
      RECT 161.790 83.730 162.120 84.160 ;
      RECT 147.305 83.770 147.910 84.225 ;
      RECT 150.885 83.180 152.685 84.590 ;
      RECT 153.120 83.405 155.630 84.745 ;
      RECT 154.380 82.885 155.995 84.755 ;
      RECT 146.360 82.700 153.960 85.020 ;
      RECT 150.015 83.180 153.760 85.060 ;
      RECT 146.745 83.760 149.275 85.160 ;
      RECT 156.435 82.850 157.480 85.415 ;
      RECT 157.435 82.850 157.870 85.415 ;
      RECT 144.070 82.880 144.840 85.420 ;
      RECT 159.430 82.880 160.200 85.420 ;
      RECT 161.350 82.880 162.120 85.420 ;
      RECT 145.370 82.850 149.825 85.500 ;
      RECT 150.015 85.285 155.320 85.545 ;
      RECT 145.080 86.535 150.385 86.795 ;
      RECT 156.965 87.560 157.360 87.890 ;
      RECT 158.885 87.560 159.280 87.890 ;
      RECT 160.805 87.560 161.200 87.890 ;
      RECT 148.250 87.980 148.790 88.300 ;
      RECT 79.370 65.240 81.270 65.520 ;
      RECT 44.570 65.760 46.470 66.040 ;
      RECT 51.770 65.760 53.670 66.040 ;
      RECT 58.370 65.760 60.270 66.040 ;
      RECT 65.570 65.760 67.470 66.040 ;
      RECT 72.170 65.760 74.070 66.040 ;
      RECT 79.370 65.760 81.270 66.040 ;
      RECT 44.570 66.280 46.470 66.560 ;
      RECT 51.770 66.280 53.670 66.560 ;
      RECT 58.370 66.280 60.270 66.560 ;
      RECT 65.570 66.280 67.470 66.560 ;
      RECT 72.170 66.280 74.070 66.560 ;
      RECT 79.370 66.280 81.270 66.560 ;
      RECT 44.090 64.690 47.090 67.110 ;
      RECT 51.290 64.690 54.290 67.110 ;
      RECT 57.890 64.690 60.890 67.110 ;
      RECT 65.090 64.690 68.090 67.110 ;
      RECT 71.690 64.690 74.690 67.110 ;
      RECT 44.690 57.960 45.590 58.240 ;
      RECT 51.990 57.960 52.890 58.240 ;
      RECT 58.490 57.960 59.390 58.240 ;
      RECT 65.790 57.960 66.690 58.240 ;
      RECT 72.290 57.960 73.190 58.240 ;
      RECT 79.590 57.960 80.490 58.240 ;
      RECT 44.690 58.480 45.590 58.760 ;
      RECT 51.990 58.480 52.890 58.760 ;
      RECT 58.490 58.480 59.390 58.760 ;
      RECT 65.790 58.480 66.690 58.760 ;
      RECT 72.290 58.480 73.190 58.760 ;
      RECT 79.590 58.480 80.490 58.760 ;
      RECT 44.690 59.000 45.590 59.280 ;
      RECT 51.990 59.000 52.890 59.280 ;
      RECT 58.490 59.000 59.390 59.280 ;
      RECT 65.790 59.000 66.690 59.280 ;
      RECT 72.290 59.000 73.190 59.280 ;
      RECT 79.590 59.000 80.490 59.280 ;
      RECT 44.210 57.410 46.210 59.830 ;
      RECT 51.510 57.410 53.510 59.830 ;
      RECT 58.010 57.410 60.010 59.830 ;
      RECT 65.310 57.410 67.310 59.830 ;
      RECT 71.810 57.410 73.810 59.830 ;
      RECT 79.110 57.410 81.110 59.830 ;
      RECT 43.330 55.700 46.750 60.510 ;
      RECT 50.830 55.700 54.200 60.510 ;
      RECT 57.130 55.700 60.550 60.510 ;
      RECT 64.630 55.700 68.000 60.510 ;
      RECT 70.930 55.700 74.350 60.510 ;
      RECT 44.570 65.240 46.470 65.520 ;
      RECT 51.770 65.240 53.670 65.520 ;
      RECT 58.370 65.240 60.270 65.520 ;
      RECT 65.570 65.240 67.470 65.520 ;
      RECT 72.170 65.240 74.070 65.520 ;
      RECT 30.290 64.690 33.290 67.110 ;
      RECT 37.490 64.690 40.490 67.110 ;
      RECT 16.970 66.280 18.870 66.560 ;
      RECT 24.170 66.280 26.070 66.560 ;
      RECT 10.590 59.000 11.490 59.280 ;
      RECT 17.090 59.000 17.990 59.280 ;
      RECT 24.390 59.000 25.290 59.280 ;
      RECT 30.890 59.000 31.790 59.280 ;
      RECT 38.190 59.000 39.090 59.280 ;
      RECT 30.770 66.280 32.670 66.560 ;
      RECT 37.970 66.280 39.870 66.560 ;
      RECT 16.970 65.760 18.870 66.040 ;
      RECT 5.400 54.500 7.400 55.100 ;
      RECT 10.590 57.960 11.490 58.240 ;
      RECT 17.090 57.960 17.990 58.240 ;
      RECT 10.110 57.410 12.110 59.830 ;
      RECT 16.610 57.410 18.610 59.830 ;
      RECT 23.910 57.410 25.910 59.830 ;
      RECT 30.410 57.410 32.410 59.830 ;
      RECT 37.710 57.410 39.710 59.830 ;
      RECT 24.390 57.960 25.290 58.240 ;
      RECT 30.890 57.960 31.790 58.240 ;
      RECT 38.190 57.960 39.090 58.240 ;
      RECT 24.170 65.760 26.070 66.040 ;
      RECT 30.770 65.760 32.670 66.040 ;
      RECT 37.970 65.760 39.870 66.040 ;
      RECT 9.430 55.700 12.800 60.510 ;
      RECT 15.730 55.700 19.150 60.510 ;
      RECT 23.230 55.700 26.600 60.510 ;
      RECT 29.530 55.700 32.950 60.510 ;
      RECT 37.030 55.700 40.400 60.510 ;
      RECT 10.370 65.760 12.270 66.040 ;
      RECT 10.370 66.280 12.270 66.560 ;
      RECT 9.890 64.690 12.890 67.110 ;
      RECT 10.590 58.480 11.490 58.760 ;
      RECT 17.090 58.480 17.990 58.760 ;
      RECT 10.370 65.240 12.270 65.520 ;
      RECT 16.970 65.240 18.870 65.520 ;
      RECT 24.170 65.240 26.070 65.520 ;
      RECT 30.770 65.240 32.670 65.520 ;
      RECT 37.970 65.240 39.870 65.520 ;
      RECT 24.390 58.480 25.290 58.760 ;
      RECT 30.890 58.480 31.790 58.760 ;
      RECT 38.190 58.480 39.090 58.760 ;
      RECT 16.490 64.690 19.490 67.110 ;
      RECT 23.690 64.690 26.690 67.110 ;
      RECT 61.490 26.690 62.390 26.970 ;
      RECT 56.890 26.160 57.790 26.440 ;
      RECT 56.890 27.220 57.790 27.500 ;
      RECT 61.490 27.220 62.390 27.500 ;
      RECT 66.090 27.220 66.990 27.500 ;
      RECT 70.690 27.220 71.590 27.500 ;
      RECT 70.690 26.690 71.590 26.970 ;
      RECT 74.810 25.610 77.810 28.030 ;
      RECT 75.290 26.160 77.190 26.440 ;
      RECT 66.090 26.690 66.990 26.970 ;
      RECT 66.090 26.160 66.990 26.440 ;
      RECT 70.690 26.160 71.590 26.440 ;
      RECT 56.410 25.610 58.410 28.050 ;
      RECT 61.010 25.610 63.010 28.050 ;
      RECT 65.610 25.610 67.610 28.050 ;
      RECT 70.210 25.610 72.210 28.050 ;
      RECT 61.490 26.160 62.390 26.440 ;
      RECT 75.290 26.680 77.190 26.960 ;
      RECT 56.890 26.690 57.790 26.970 ;
      RECT 75.290 27.200 77.190 27.480 ;
      RECT 120.290 64.690 123.290 67.110 ;
      RECT 120.510 57.410 122.510 59.830 ;
      RECT 119.830 55.700 123.200 60.510 ;
      RECT 120.770 65.240 122.670 65.520 ;
      RECT 120.770 65.760 122.670 66.040 ;
      RECT 120.770 66.280 122.670 66.560 ;
      RECT 126.130 55.700 129.550 60.510 ;
      RECT 127.010 57.410 129.010 59.830 ;
      RECT 127.370 65.240 129.270 65.520 ;
      RECT 127.490 58.480 128.390 58.760 ;
      RECT 127.490 57.960 128.390 58.240 ;
      RECT 127.370 65.760 129.270 66.040 ;
      RECT 126.890 64.690 129.890 67.110 ;
      RECT 127.370 66.280 129.270 66.560 ;
      RECT 127.490 59.000 128.390 59.280 ;
      RECT 93.390 57.960 94.290 58.240 ;
      RECT 99.890 57.960 100.790 58.240 ;
      RECT 107.190 57.960 108.090 58.240 ;
      RECT 113.690 57.960 114.590 58.240 ;
      RECT 120.990 57.960 121.890 58.240 ;
      RECT 113.090 64.690 116.090 67.110 ;
      RECT 84.730 55.700 88.150 60.510 ;
      RECT 92.230 55.700 95.600 60.510 ;
      RECT 98.530 55.700 101.950 60.510 ;
      RECT 106.030 55.700 109.400 60.510 ;
      RECT 112.330 55.700 115.750 60.510 ;
      RECT 85.490 64.690 88.490 67.110 ;
      RECT 92.690 64.690 95.690 67.110 ;
      RECT 86.090 58.480 86.990 58.760 ;
      RECT 85.970 65.240 87.870 65.520 ;
      RECT 93.170 65.240 95.070 65.520 ;
      RECT 99.770 65.240 101.670 65.520 ;
      RECT 106.970 65.240 108.870 65.520 ;
      RECT 113.570 65.240 115.470 65.520 ;
      RECT 85.610 57.410 87.610 59.830 ;
      RECT 92.910 57.410 94.910 59.830 ;
      RECT 93.390 58.480 94.290 58.760 ;
      RECT 99.890 58.480 100.790 58.760 ;
      RECT 107.190 58.480 108.090 58.760 ;
      RECT 113.690 58.480 114.590 58.760 ;
      RECT 120.990 58.480 121.890 58.760 ;
      RECT 99.410 57.410 101.410 59.830 ;
      RECT 85.970 65.760 87.870 66.040 ;
      RECT 93.170 65.760 95.070 66.040 ;
      RECT 99.770 65.760 101.670 66.040 ;
      RECT 106.970 65.760 108.870 66.040 ;
      RECT 113.570 65.760 115.470 66.040 ;
      RECT 106.710 57.410 108.710 59.830 ;
      RECT 113.210 57.410 115.210 59.830 ;
      RECT 86.090 59.000 86.990 59.280 ;
      RECT 93.390 59.000 94.290 59.280 ;
      RECT 99.890 59.000 100.790 59.280 ;
      RECT 107.190 59.000 108.090 59.280 ;
      RECT 113.690 59.000 114.590 59.280 ;
      RECT 85.970 66.280 87.870 66.560 ;
      RECT 93.170 66.280 95.070 66.560 ;
      RECT 99.770 66.280 101.670 66.560 ;
      RECT 106.970 66.280 108.870 66.560 ;
      RECT 113.570 66.280 115.470 66.560 ;
      RECT 99.290 64.690 102.290 67.110 ;
      RECT 106.490 64.690 109.490 67.110 ;
      RECT 120.990 59.000 121.890 59.280 ;
      RECT 86.090 57.960 86.990 58.240 ;
      RECT 85.710 25.210 89.930 28.470 ;
      RECT 86.870 26.960 88.770 27.240 ;
      RECT 86.870 26.440 88.770 26.720 ;
      RECT 86.390 25.890 89.390 27.790 ;
      RECT 143.590 25.960 144.490 26.240 ;
      RECT 135.790 41.960 137.690 42.240 ;
      RECT 140.790 41.960 142.690 42.240 ;
      RECT 135.790 42.480 137.690 42.760 ;
      RECT 140.790 42.480 142.690 42.760 ;
      RECT 143.470 33.760 145.370 34.040 ;
      RECT 157.270 33.760 159.170 34.040 ;
      RECT 136.870 34.280 138.770 34.560 ;
      RECT 143.470 34.280 145.370 34.560 ;
      RECT 157.270 34.280 159.170 34.560 ;
      RECT 136.390 32.690 139.390 35.110 ;
      RECT 142.990 32.690 145.990 35.110 ;
      RECT 135.790 43.000 137.690 43.280 ;
      RECT 140.790 43.000 142.690 43.280 ;
      RECT 135.310 41.410 138.310 43.830 ;
      RECT 140.310 41.410 143.310 43.830 ;
      RECT 134.630 39.960 138.850 44.510 ;
      RECT 139.630 39.960 143.850 44.510 ;
      RECT 156.790 32.690 159.790 35.110 ;
      RECT 157.390 27.000 158.290 27.280 ;
      RECT 137.090 26.480 137.990 26.760 ;
      RECT 157.390 26.480 158.290 26.760 ;
      RECT 143.590 27.000 144.490 27.280 ;
      RECT 143.470 33.240 145.370 33.520 ;
      RECT 157.390 25.960 158.290 26.240 ;
      RECT 143.590 26.480 144.490 26.760 ;
      RECT 137.090 25.960 137.990 26.240 ;
      RECT 136.870 33.240 138.770 33.520 ;
      RECT 136.610 25.410 138.610 27.830 ;
      RECT 143.110 25.410 145.110 27.830 ;
      RECT 156.910 25.410 158.910 27.830 ;
      RECT 157.270 33.240 159.170 33.520 ;
      RECT 136.870 33.760 138.770 34.040 ;
      RECT 137.090 27.000 137.990 27.280 ;
      RECT 187.700 53.500 313.500 54.100 ;
      RECT 187.700 54.500 325.500 55.100 ;
      RECT 163.500 90.445 165.115 92.315 ;
      RECT 165.555 90.410 166.600 92.975 ;
      RECT 166.555 90.410 166.990 92.975 ;
      RECT 167.560 90.440 168.330 92.980 ;
      RECT 170.410 90.430 175.245 92.980 ;
      RECT 173.470 90.430 180.870 92.980 ;
      RECT 173.215 101.760 174.225 103.940 ;
      RECT 175.615 101.760 176.625 103.940 ;
      RECT 178.495 101.760 179.505 103.940 ;
      RECT 180.415 101.760 181.425 103.940 ;
      RECT 170.910 101.680 171.810 104.370 ;
      RECT 174.300 101.760 174.600 104.390 ;
      RECT 175.240 101.760 175.540 104.390 ;
      RECT 178.120 101.760 178.420 104.390 ;
      RECT 180.040 101.760 180.340 104.390 ;
      RECT 179.955 109.345 181.000 111.910 ;
      RECT 180.955 109.345 181.390 111.910 ;
      RECT 166.410 111.255 167.730 111.930 ;
      RECT 167.470 109.240 168.370 111.930 ;
      RECT 169.880 109.740 177.480 112.060 ;
      RECT 164.690 110.600 164.980 111.030 ;
      RECT 165.630 110.600 165.960 111.030 ;
      RECT 166.520 110.490 166.880 111.070 ;
      RECT 167.080 110.490 167.360 111.070 ;
      RECT 167.600 110.490 167.915 111.070 ;
      RECT 176.640 110.015 179.150 111.355 ;
      RECT 173.285 102.680 173.680 103.010 ;
      RECT 176.160 102.680 176.555 103.010 ;
      RECT 179.040 102.680 179.435 103.010 ;
      RECT 180.960 102.680 181.355 103.010 ;
      RECT 164.090 103.100 164.630 103.420 ;
      RECT 170.825 110.535 171.430 110.990 ;
      RECT 170.265 109.600 172.795 111.000 ;
      RECT 171.365 102.930 171.680 103.510 ;
      RECT 171.920 102.930 172.200 103.510 ;
      RECT 172.400 102.930 172.760 103.510 ;
      RECT 165.600 102.455 168.110 103.795 ;
      RECT 168.935 110.610 169.280 111.430 ;
      RECT 173.535 109.700 177.280 111.580 ;
      RECT 174.405 110.170 176.205 111.580 ;
      RECT 171.800 110.800 173.585 111.715 ;
      RECT 163.365 102.610 165.165 104.020 ;
      RECT 166.860 102.445 168.475 104.315 ;
      RECT 165.150 103.630 166.950 104.350 ;
      RECT 168.915 101.785 169.960 104.350 ;
      RECT 169.915 101.785 170.350 104.350 ;
      RECT 177.900 110.005 179.515 111.875 ;
      RECT 171.550 103.695 172.870 104.370 ;
      RECT 165.190 109.340 165.960 111.880 ;
      RECT 163.675 109.345 164.110 111.910 ;
      RECT 168.890 109.260 173.345 111.910 ;
      RECT 176.190 111.190 177.990 111.910 ;
      RECT 176.190 105.530 177.990 106.250 ;
      RECT 171.800 105.725 173.585 106.640 ;
      RECT 175.130 106.460 175.670 106.780 ;
      RECT 163.255 106.460 163.570 106.790 ;
      RECT 168.935 106.010 169.280 106.830 ;
      RECT 167.090 106.410 167.380 106.840 ;
      RECT 168.030 106.410 168.360 106.840 ;
      RECT 170.825 106.450 171.430 106.905 ;
      RECT 165.120 106.870 165.515 107.200 ;
      RECT 174.405 105.860 176.205 107.270 ;
      RECT 176.640 106.085 179.150 107.425 ;
      RECT 177.900 105.565 179.515 107.435 ;
      RECT 169.880 105.380 177.480 107.700 ;
      RECT 173.535 105.860 177.280 107.740 ;
      RECT 170.265 106.440 172.795 107.840 ;
      RECT 179.955 105.530 181.000 108.095 ;
      RECT 180.955 105.530 181.390 108.095 ;
      RECT 167.590 105.560 168.360 108.100 ;
      RECT 162.795 105.550 163.025 108.115 ;
      RECT 164.200 105.490 164.500 108.120 ;
      RECT 164.575 105.940 165.585 108.120 ;
      RECT 168.890 105.530 173.345 108.180 ;
      RECT 173.535 107.965 178.840 108.225 ;
      RECT 173.535 109.215 178.840 109.475 ;
      RECT 175.130 110.660 175.670 110.980 ;
      RECT 175.130 95.540 175.670 95.860 ;
      RECT 170.825 95.415 171.430 95.870 ;
      RECT 170.265 94.480 172.795 95.880 ;
      RECT 176.640 94.895 179.150 96.235 ;
      RECT 168.935 95.490 169.280 96.310 ;
      RECT 173.535 94.580 177.280 96.460 ;
      RECT 174.405 95.050 176.205 96.460 ;
      RECT 171.800 95.680 173.585 96.595 ;
      RECT 177.900 94.885 179.515 96.755 ;
      RECT 168.095 94.205 168.325 96.770 ;
      RECT 168.890 94.140 173.345 96.790 ;
      RECT 176.190 96.070 177.990 96.790 ;
      RECT 179.955 94.225 181.000 96.790 ;
      RECT 180.955 94.225 181.390 96.790 ;
      RECT 169.880 94.620 177.480 96.940 ;
      RECT 166.410 97.950 167.730 98.625 ;
      RECT 176.190 97.970 177.990 98.690 ;
      RECT 171.800 98.165 173.585 99.080 ;
      RECT 175.130 98.900 175.670 99.220 ;
      RECT 164.690 98.850 164.980 99.280 ;
      RECT 165.630 98.850 165.960 99.280 ;
      RECT 170.825 98.890 171.430 99.345 ;
      RECT 166.520 98.810 166.880 99.390 ;
      RECT 167.080 98.810 167.360 99.390 ;
      RECT 167.600 98.810 167.915 99.390 ;
      RECT 168.935 98.450 169.280 99.415 ;
      RECT 174.405 98.300 176.205 99.710 ;
      RECT 176.640 98.525 179.150 99.865 ;
      RECT 177.900 98.005 179.515 99.875 ;
      RECT 169.880 97.820 177.480 100.140 ;
      RECT 173.535 98.300 177.280 100.180 ;
      RECT 170.265 98.880 172.795 100.280 ;
      RECT 163.195 97.970 163.630 100.535 ;
      RECT 179.955 97.970 181.000 100.535 ;
      RECT 180.955 97.970 181.390 100.535 ;
      RECT 165.190 98.000 165.960 100.540 ;
      RECT 168.890 97.970 173.345 100.620 ;
      RECT 167.470 97.950 168.370 100.640 ;
      RECT 173.535 100.405 178.840 100.665 ;
      RECT 170.200 91.340 171.380 91.670 ;
      RECT 167.560 91.290 167.890 91.720 ;
      RECT 168.540 91.290 168.830 91.720 ;
      RECT 173.535 94.095 178.840 94.355 ;
      RECT 165.500 95.530 166.680 95.860 ;
      RECT 167.550 95.530 167.865 95.860 ;
      RECT 167.080 86.640 167.380 89.270 ;
      RECT 169.880 87.060 177.480 89.380 ;
      RECT 173.470 82.830 174.790 83.505 ;
      RECT 171.895 83.780 172.210 84.110 ;
      RECT 162.770 83.730 163.060 84.160 ;
      RECT 163.710 83.730 164.040 84.160 ;
      RECT 167.080 83.730 167.410 84.160 ;
      RECT 168.060 83.730 168.350 84.160 ;
      RECT 177.170 83.730 177.460 84.160 ;
      RECT 178.110 83.730 178.440 84.160 ;
      RECT 173.285 83.690 173.600 84.270 ;
      RECT 173.840 83.690 174.120 84.270 ;
      RECT 174.320 83.690 174.680 84.270 ;
      RECT 165.125 84.190 165.520 84.520 ;
      RECT 170.400 84.190 170.795 84.520 ;
      RECT 176.160 84.190 176.555 84.520 ;
      RECT 180.000 84.190 180.395 84.520 ;
      RECT 163.270 82.880 164.040 85.420 ;
      RECT 167.080 82.880 167.850 85.420 ;
      RECT 177.670 82.880 178.440 85.420 ;
      RECT 171.435 82.870 171.665 85.435 ;
      RECT 165.055 83.260 166.065 85.440 ;
      RECT 166.140 82.810 166.440 85.440 ;
      RECT 169.480 82.810 169.780 85.440 ;
      RECT 169.855 83.260 170.865 85.440 ;
      RECT 175.240 82.810 175.540 85.440 ;
      RECT 175.615 83.260 176.625 85.440 ;
      RECT 179.080 82.810 179.380 85.440 ;
      RECT 179.455 83.260 180.465 85.440 ;
      RECT 172.830 82.830 173.730 85.520 ;
      RECT 173.535 86.535 178.840 86.795 ;
      RECT 163.680 87.560 164.075 87.890 ;
      RECT 165.125 87.560 165.520 87.890 ;
      RECT 168.000 87.560 168.395 87.890 ;
      RECT 175.130 87.980 175.670 88.300 ;
      RECT 170.825 87.855 171.430 88.310 ;
      RECT 170.265 86.920 172.795 88.320 ;
      RECT 176.640 87.335 179.150 88.675 ;
      RECT 168.935 87.930 169.280 88.750 ;
      RECT 163.135 86.640 164.145 88.820 ;
      RECT 165.055 86.640 166.065 88.820 ;
      RECT 167.455 86.640 168.465 88.820 ;
      RECT 173.535 87.020 177.280 88.900 ;
      RECT 174.405 87.490 176.205 88.900 ;
      RECT 171.800 88.120 173.585 89.035 ;
      RECT 177.900 87.325 179.515 89.195 ;
      RECT 168.890 86.580 173.345 89.230 ;
      RECT 176.190 88.510 177.990 89.230 ;
      RECT 179.955 86.665 181.000 89.230 ;
      RECT 180.955 86.665 181.390 89.230 ;
      RECT 162.760 86.640 163.060 89.270 ;
      RECT 166.140 86.640 166.440 89.270 ;
      RECT 190.590 57.960 191.490 58.240 ;
      RECT 224.570 65.760 226.470 66.040 ;
      RECT 240.410 27.220 241.310 27.500 ;
      RECT 231.770 65.760 233.670 66.040 ;
      RECT 237.890 64.690 240.890 67.110 ;
      RECT 238.370 65.760 240.270 66.040 ;
      RECT 218.190 57.960 219.090 58.240 ;
      RECT 197.090 57.960 197.990 58.240 ;
      RECT 223.230 26.960 225.130 27.240 ;
      RECT 190.590 58.480 191.490 58.760 ;
      RECT 197.090 58.480 197.990 58.760 ;
      RECT 204.390 58.480 205.290 58.760 ;
      RECT 210.890 58.480 211.790 58.760 ;
      RECT 186.800 53.600 187.200 54.000 ;
      RECT 218.190 58.480 219.090 58.760 ;
      RECT 190.370 65.240 192.270 65.520 ;
      RECT 196.970 65.240 198.870 65.520 ;
      RECT 204.170 65.240 206.070 65.520 ;
      RECT 239.790 25.610 241.790 28.050 ;
      RECT 204.390 57.960 205.290 58.240 ;
      RECT 210.770 65.240 212.670 65.520 ;
      RECT 217.970 65.240 219.870 65.520 ;
      RECT 210.890 57.960 211.790 58.240 ;
      RECT 228.930 26.440 230.830 26.720 ;
      RECT 171.070 33.760 172.970 34.040 ;
      RECT 224.570 65.240 226.470 65.520 ;
      RECT 171.190 27.000 172.090 27.280 ;
      RECT 222.070 25.210 226.290 28.470 ;
      RECT 227.770 25.210 231.990 28.470 ;
      RECT 190.590 59.000 191.490 59.280 ;
      RECT 197.090 59.000 197.990 59.280 ;
      RECT 204.390 59.000 205.290 59.280 ;
      RECT 223.230 26.440 225.130 26.720 ;
      RECT 231.770 65.240 233.670 65.520 ;
      RECT 240.410 26.690 241.310 26.970 ;
      RECT 238.370 65.240 240.270 65.520 ;
      RECT 210.890 59.000 211.790 59.280 ;
      RECT 222.610 25.890 225.610 27.790 ;
      RECT 218.190 59.000 219.090 59.280 ;
      RECT 170.590 32.690 173.590 35.110 ;
      RECT 190.370 66.280 192.270 66.560 ;
      RECT 196.970 66.280 198.870 66.560 ;
      RECT 204.170 66.280 206.070 66.560 ;
      RECT 210.770 66.280 212.670 66.560 ;
      RECT 228.310 25.890 231.310 27.790 ;
      RECT 171.070 34.280 172.970 34.560 ;
      RECT 190.110 57.410 192.110 59.830 ;
      RECT 196.610 57.410 198.610 59.830 ;
      RECT 203.910 57.410 205.910 59.830 ;
      RECT 217.970 66.280 219.870 66.560 ;
      RECT 224.570 66.280 226.470 66.560 ;
      RECT 231.770 66.280 233.670 66.560 ;
      RECT 238.370 66.280 240.270 66.560 ;
      RECT 224.690 58.480 225.590 58.760 ;
      RECT 189.430 55.700 192.800 60.510 ;
      RECT 195.730 55.700 199.150 60.510 ;
      RECT 203.230 55.700 206.600 60.510 ;
      RECT 210.410 57.410 212.410 59.830 ;
      RECT 231.990 58.480 232.890 58.760 ;
      RECT 217.710 57.410 219.710 59.830 ;
      RECT 238.490 58.480 239.390 58.760 ;
      RECT 224.210 57.410 226.210 59.830 ;
      RECT 209.530 55.700 212.950 60.510 ;
      RECT 224.690 57.960 225.590 58.240 ;
      RECT 217.030 55.700 220.400 60.510 ;
      RECT 224.690 59.000 225.590 59.280 ;
      RECT 231.990 59.000 232.890 59.280 ;
      RECT 223.330 55.700 226.750 60.510 ;
      RECT 238.490 59.000 239.390 59.280 ;
      RECT 230.830 55.700 234.200 60.510 ;
      RECT 237.130 55.700 240.550 60.510 ;
      RECT 228.930 26.960 230.830 27.240 ;
      RECT 171.190 26.480 172.090 26.760 ;
      RECT 190.370 65.760 192.270 66.040 ;
      RECT 231.990 57.960 232.890 58.240 ;
      RECT 231.510 57.410 233.510 59.830 ;
      RECT 238.490 57.960 239.390 58.240 ;
      RECT 240.410 26.160 241.310 26.440 ;
      RECT 196.970 65.760 198.870 66.040 ;
      RECT 234.810 26.680 236.710 26.960 ;
      RECT 234.810 27.200 236.710 27.480 ;
      RECT 171.190 25.960 172.090 26.240 ;
      RECT 234.810 26.160 236.710 26.440 ;
      RECT 170.710 25.410 172.710 27.830 ;
      RECT 204.170 65.760 206.070 66.040 ;
      RECT 171.070 33.240 172.970 33.520 ;
      RECT 238.010 57.410 240.010 59.830 ;
      RECT 189.890 64.690 192.890 67.110 ;
      RECT 210.770 65.760 212.670 66.040 ;
      RECT 196.490 64.690 199.490 67.110 ;
      RECT 234.190 25.610 237.190 28.030 ;
      RECT 203.690 64.690 206.690 67.110 ;
      RECT 210.290 64.690 213.290 67.110 ;
      RECT 217.490 64.690 220.490 67.110 ;
      RECT 224.090 64.690 227.090 67.110 ;
      RECT 217.970 65.760 219.870 66.040 ;
      RECT 231.290 64.690 234.290 67.110 ;
      RECT 300.770 65.760 302.670 66.040 ;
      RECT 307.370 65.760 309.270 66.040 ;
      RECT 286.970 65.240 288.870 65.520 ;
      RECT 293.570 65.240 295.470 65.520 ;
      RECT 300.770 65.240 302.670 65.520 ;
      RECT 307.370 65.240 309.270 65.520 ;
      RECT 293.090 64.690 296.090 67.110 ;
      RECT 286.030 55.700 289.400 60.510 ;
      RECT 292.330 55.700 295.750 60.510 ;
      RECT 299.830 55.700 303.200 60.510 ;
      RECT 306.130 55.700 309.550 60.510 ;
      RECT 287.190 58.480 288.090 58.760 ;
      RECT 293.690 58.480 294.590 58.760 ;
      RECT 300.990 58.480 301.890 58.760 ;
      RECT 300.290 64.690 303.290 67.110 ;
      RECT 307.490 58.480 308.390 58.760 ;
      RECT 287.190 57.960 288.090 58.240 ;
      RECT 286.970 66.280 288.870 66.560 ;
      RECT 293.570 66.280 295.470 66.560 ;
      RECT 300.770 66.280 302.670 66.560 ;
      RECT 307.370 66.280 309.270 66.560 ;
      RECT 293.690 57.960 294.590 58.240 ;
      RECT 306.890 64.690 309.890 67.110 ;
      RECT 300.990 57.960 301.890 58.240 ;
      RECT 307.490 57.960 308.390 58.240 ;
      RECT 287.190 59.000 288.090 59.280 ;
      RECT 286.710 57.410 288.710 59.830 ;
      RECT 293.210 57.410 295.210 59.830 ;
      RECT 293.690 59.000 294.590 59.280 ;
      RECT 300.510 57.410 302.510 59.830 ;
      RECT 300.990 59.000 301.890 59.280 ;
      RECT 307.490 59.000 308.390 59.280 ;
      RECT 307.010 57.410 309.010 59.830 ;
      RECT 286.490 64.690 289.490 67.110 ;
      RECT 286.970 65.760 288.870 66.040 ;
      RECT 293.570 65.760 295.470 66.040 ;
      RECT 245.570 66.280 247.470 66.560 ;
      RECT 258.430 55.700 261.800 60.510 ;
      RECT 273.170 65.240 275.070 65.520 ;
      RECT 272.690 64.690 275.690 67.110 ;
      RECT 273.390 57.960 274.290 58.240 ;
      RECT 252.170 66.280 254.070 66.560 ;
      RECT 259.370 66.280 261.270 66.560 ;
      RECT 265.970 66.280 267.870 66.560 ;
      RECT 279.770 65.240 281.670 65.520 ;
      RECT 273.170 66.280 275.070 66.560 ;
      RECT 279.770 66.280 281.670 66.560 ;
      RECT 265.490 64.690 268.490 67.110 ;
      RECT 264.730 55.700 268.150 60.510 ;
      RECT 252.290 57.960 253.190 58.240 ;
      RECT 259.590 57.960 260.490 58.240 ;
      RECT 245.570 65.240 247.470 65.520 ;
      RECT 272.230 55.700 275.600 60.510 ;
      RECT 265.610 57.410 267.610 59.830 ;
      RECT 278.530 55.700 281.950 60.510 ;
      RECT 279.890 57.960 280.790 58.240 ;
      RECT 245.790 59.000 246.690 59.280 ;
      RECT 272.910 57.410 274.910 59.830 ;
      RECT 252.290 59.000 253.190 59.280 ;
      RECT 266.090 57.960 266.990 58.240 ;
      RECT 259.590 59.000 260.490 59.280 ;
      RECT 266.090 59.000 266.990 59.280 ;
      RECT 279.410 57.410 281.410 59.830 ;
      RECT 273.390 59.000 274.290 59.280 ;
      RECT 245.310 57.410 247.310 59.830 ;
      RECT 279.890 59.000 280.790 59.280 ;
      RECT 252.170 65.240 254.070 65.520 ;
      RECT 259.370 65.240 261.270 65.520 ;
      RECT 244.630 55.700 248.000 60.510 ;
      RECT 250.930 55.700 254.350 60.510 ;
      RECT 245.790 58.480 246.690 58.760 ;
      RECT 252.290 58.480 253.190 58.760 ;
      RECT 259.590 58.480 260.490 58.760 ;
      RECT 266.090 58.480 266.990 58.760 ;
      RECT 251.810 57.410 253.810 59.830 ;
      RECT 259.110 57.410 261.110 59.830 ;
      RECT 279.290 64.690 282.290 67.110 ;
      RECT 245.090 64.690 248.090 67.110 ;
      RECT 245.570 65.760 247.470 66.040 ;
      RECT 251.690 64.690 254.690 67.110 ;
      RECT 252.170 65.760 254.070 66.040 ;
      RECT 259.370 65.760 261.270 66.040 ;
      RECT 258.890 64.690 261.890 67.110 ;
      RECT 265.970 65.760 267.870 66.040 ;
      RECT 273.170 65.760 275.070 66.040 ;
      RECT 273.390 58.480 274.290 58.760 ;
      RECT 279.770 65.760 281.670 66.040 ;
      RECT 245.790 57.960 246.690 58.240 ;
      RECT 279.890 58.480 280.790 58.760 ;
      RECT 265.970 65.240 267.870 65.520 ;
      RECT 249.610 27.220 250.510 27.500 ;
      RECT 249.610 26.160 250.510 26.440 ;
      RECT 244.390 25.610 246.390 28.050 ;
      RECT 245.010 26.160 245.910 26.440 ;
      RECT 248.990 25.610 250.990 28.050 ;
      RECT 249.610 26.690 250.510 26.970 ;
      RECT 254.210 27.220 255.110 27.500 ;
      RECT 253.590 25.610 255.590 28.050 ;
      RECT 254.210 26.690 255.110 26.970 ;
      RECT 245.010 27.220 245.910 27.500 ;
      RECT 254.210 26.160 255.110 26.440 ;
      RECT 245.010 26.690 245.910 26.970 ;
      RECT 321.210 41.410 324.210 43.830 ;
      RECT 316.690 43.000 318.590 43.280 ;
      RECT 316.690 42.480 318.590 42.760 ;
      RECT 321.690 42.480 323.590 42.760 ;
      RECT 315.530 39.960 319.750 44.510 ;
      RECT 316.690 41.960 318.590 42.240 ;
      RECT 320.530 39.960 324.750 44.510 ;
      RECT 316.210 41.410 319.210 43.830 ;
      RECT 321.690 43.000 323.590 43.280 ;
      RECT 321.690 41.960 323.590 42.240 ;
    LAYER Metal2 ;
      RECT 163.000 30.000 163.400 50.300 ;
      RECT 161.860 52.900 163.500 87.025 ;
      RECT 162.815 106.475 163.460 106.770 ;
      RECT 161.860 88.415 163.980 107.560 ;
      RECT 159.455 87.575 163.500 116.845 ;
      RECT 153.695 96.395 155.340 118.945 ;
      RECT 159.455 117.660 159.665 118.945 ;
      RECT 162.815 118.225 163.025 118.945 ;
      RECT 170.975 118.225 171.185 118.945 ;
      RECT 173.375 118.230 173.585 118.945 ;
      RECT 156.580 118.235 158.220 119.365 ;
      RECT 163.295 118.235 163.505 119.365 ;
      RECT 165.695 118.650 165.905 119.365 ;
      RECT 169.535 117.815 169.745 119.365 ;
      RECT 156.095 118.235 156.305 119.785 ;
      RECT 166.175 118.235 166.385 119.785 ;
      RECT 170.495 118.235 170.705 119.785 ;
      RECT 142.175 116.975 142.860 120.205 ;
      RECT 158.495 118.235 158.705 120.205 ;
      RECT 164.260 114.035 165.420 121.045 ;
      RECT 175.295 118.235 175.505 121.045 ;
      RECT 177.700 118.235 178.860 121.045 ;
      RECT 143.620 100.175 144.305 121.465 ;
      RECT 167.445 118.200 169.265 121.465 ;
      RECT 144.095 118.655 144.305 121.885 ;
      RECT 145.540 115.295 146.220 121.885 ;
      RECT 165.220 118.235 168.780 121.885 ;
      RECT 176.260 116.975 177.905 121.885 ;
      RECT 150.815 114.035 151.450 122.240 ;
      RECT 145.055 110.675 146.700 122.725 ;
      RECT 152.740 118.235 153.425 122.725 ;
      RECT 158.980 118.235 159.660 122.725 ;
      RECT 152.255 117.815 152.465 124.825 ;
      RECT 144.575 112.775 144.785 125.665 ;
      RECT 146.015 114.035 146.700 125.665 ;
      RECT 143.135 104.375 144.300 126.085 ;
      RECT 147.935 116.975 149.105 128.605 ;
      RECT 174.340 114.035 176.460 128.605 ;
      RECT 161.380 114.035 164.460 129.025 ;
      RECT 148.900 115.715 149.585 132.385 ;
      RECT 147.455 116.135 148.145 134.485 ;
      RECT 162.815 129.155 163.500 136.165 ;
      RECT 158.315 114.035 160.145 137.005 ;
      RECT 162.340 140.495 163.500 143.725 ;
      RECT 141.215 106.895 144.300 158.845 ;
      RECT 162.820 152.675 163.500 163.885 ;
      RECT 134.000 69.200 134.400 176.000 ;
      RECT 135.400 87.520 135.800 184.300 ;
      RECT 10.650 71.000 11.350 189.905 ;
      RECT 161.400 198.440 163.420 203.400 ;
      RECT 6.250 22.600 6.950 215.005 ;
      RECT 205.600 126.100 305.200 127.700 ;
      RECT 199.000 121.300 305.200 122.900 ;
      RECT 201.200 122.900 305.200 124.500 ;
      RECT 207.800 127.700 305.200 129.300 ;
      RECT 196.800 119.700 305.200 121.300 ;
      RECT 187.800 124.480 188.200 185.100 ;
      RECT 203.400 124.500 305.200 126.100 ;
      RECT 313.950 186.500 314.650 189.905 ;
      RECT 176.330 179.920 178.230 183.400 ;
      RECT 176.330 175.650 178.230 179.600 ;
      RECT 182.930 179.920 184.830 185.100 ;
      RECT 182.930 175.650 184.830 179.600 ;
      RECT 167.310 179.310 167.990 186.970 ;
      RECT 168.210 186.580 170.110 186.980 ;
      RECT 171.670 179.300 172.070 186.980 ;
      RECT 167.930 179.300 170.830 179.700 ;
      RECT 168.210 192.550 169.110 192.950 ;
      RECT 168.210 183.000 170.730 193.900 ;
      RECT 169.180 189.295 169.880 196.300 ;
      RECT 175.710 179.570 176.110 197.400 ;
      RECT 182.310 179.570 182.710 197.400 ;
      RECT 167.590 192.140 169.110 199.300 ;
      RECT 167.930 175.650 171.450 180.160 ;
      RECT 165.695 121.175 165.905 142.885 ;
      RECT 171.455 140.495 172.140 142.885 ;
      RECT 170.015 140.915 170.225 143.305 ;
      RECT 170.975 141.755 171.185 143.305 ;
      RECT 167.135 139.655 167.345 143.725 ;
      RECT 181.055 139.655 181.265 143.725 ;
      RECT 169.055 142.175 169.265 144.145 ;
      RECT 163.300 121.595 165.900 144.565 ;
      RECT 174.335 140.910 174.545 144.565 ;
      RECT 173.375 140.915 173.585 144.985 ;
      RECT 166.655 130.415 167.345 146.245 ;
      RECT 180.100 140.915 180.780 147.505 ;
      RECT 168.095 142.595 168.305 147.925 ;
      RECT 178.175 140.915 178.385 158.845 ;
      RECT 170.495 133.355 171.660 159.685 ;
      RECT 179.135 140.915 179.345 162.625 ;
      RECT 173.380 133.355 177.900 163.885 ;
      RECT 169.055 147.635 169.265 148.765 ;
      RECT 170.495 148.050 170.705 148.765 ;
      RECT 163.295 148.055 163.980 149.605 ;
      RECT 166.175 148.890 166.385 149.605 ;
      RECT 163.775 144.275 164.940 150.865 ;
      RECT 169.055 149.315 169.265 151.705 ;
      RECT 164.735 150.995 164.945 151.710 ;
      RECT 163.775 151.410 163.985 152.125 ;
      RECT 167.135 148.475 167.345 152.125 ;
      RECT 168.095 151.410 168.305 152.125 ;
      RECT 163.295 150.995 163.505 152.545 ;
      RECT 165.215 151.825 165.425 152.545 ;
      RECT 166.655 144.270 167.820 152.545 ;
      RECT 181.055 153.095 181.265 154.225 ;
      RECT 163.295 154.350 163.505 155.065 ;
      RECT 167.620 145.955 169.745 155.065 ;
      RECT 163.775 154.355 163.985 156.325 ;
      RECT 165.215 155.195 165.425 156.325 ;
      RECT 165.695 155.610 165.905 156.325 ;
      RECT 165.700 148.475 166.380 156.325 ;
      RECT 168.095 153.935 168.305 156.325 ;
      RECT 169.055 156.030 169.265 156.745 ;
      RECT 181.055 156.450 181.265 157.165 ;
      RECT 164.260 148.475 165.420 158.845 ;
      RECT 166.175 145.535 166.385 146.250 ;
      RECT 181.055 158.130 181.265 158.845 ;
      RECT 166.655 154.355 166.865 159.685 ;
      RECT 168.095 156.875 168.305 159.685 ;
      RECT 163.295 144.275 163.505 144.990 ;
      RECT 163.295 159.395 163.505 160.110 ;
      RECT 164.735 159.395 164.945 160.110 ;
      RECT 167.135 152.675 167.820 161.785 ;
      RECT 166.180 159.395 169.260 162.625 ;
      RECT 166.175 143.850 166.385 144.565 ;
      RECT 170.495 151.835 171.180 163.465 ;
      RECT 163.775 157.295 164.940 163.885 ;
      RECT 165.220 160.655 166.860 163.885 ;
      RECT 167.135 163.170 167.345 163.885 ;
      RECT 168.575 144.275 168.785 148.345 ;
      RECT 169.055 163.175 169.265 163.895 ;
      RECT 163.775 160.235 164.940 164.725 ;
      RECT 169.535 140.075 169.745 140.795 ;
      RECT 168.095 140.075 168.305 141.205 ;
      RECT 169.055 140.075 169.265 141.205 ;
      RECT 176.260 130.415 176.940 141.205 ;
      RECT 175.780 121.595 177.900 141.205 ;
      RECT 175.775 121.170 175.985 121.885 ;
      RECT 176.255 140.910 176.465 141.625 ;
      RECT 178.655 140.910 178.865 141.625 ;
      RECT 163.775 141.330 163.985 142.045 ;
      RECT 166.175 141.330 166.385 142.045 ;
      RECT 175.775 141.330 175.985 142.045 ;
      RECT 180.095 122.435 180.305 124.825 ;
      RECT 181.055 129.575 181.265 136.165 ;
      RECT 166.655 135.870 166.865 136.585 ;
      RECT 174.335 124.530 174.545 125.245 ;
      RECT 178.175 121.595 178.385 122.310 ;
      RECT 164.735 129.995 164.945 137.005 ;
      RECT 168.100 136.715 169.260 137.845 ;
      RECT 173.375 121.595 173.585 125.665 ;
      RECT 173.375 129.995 173.585 139.945 ;
      RECT 173.855 119.075 174.065 139.945 ;
      RECT 175.775 139.650 175.985 140.365 ;
      RECT 164.735 140.065 164.945 140.785 ;
      RECT 166.175 136.715 166.385 140.785 ;
      RECT 168.575 140.070 168.785 140.785 ;
      RECT 181.055 124.535 181.265 125.665 ;
      RECT 170.495 126.210 170.705 126.925 ;
      RECT 169.535 121.170 169.745 121.885 ;
      RECT 166.655 121.595 166.865 128.605 ;
      RECT 170.015 128.660 170.225 129.380 ;
      RECT 167.135 125.795 167.345 129.445 ;
      RECT 169.055 124.535 169.265 129.445 ;
      RECT 174.335 128.315 174.545 129.445 ;
      RECT 177.215 128.730 177.425 129.445 ;
      RECT 168.095 122.015 168.305 129.865 ;
      RECT 175.295 129.150 175.505 129.865 ;
      RECT 176.735 125.795 176.945 129.865 ;
      RECT 172.415 124.955 172.625 126.085 ;
      RECT 167.615 121.595 167.825 130.285 ;
      RECT 179.615 129.565 179.825 130.285 ;
      RECT 177.215 129.995 177.425 131.125 ;
      RECT 177.700 125.795 178.865 131.125 ;
      RECT 166.175 121.585 166.385 122.305 ;
      RECT 180.575 121.595 180.785 132.385 ;
      RECT 168.580 130.415 169.740 133.645 ;
      RECT 168.575 123.275 168.785 124.825 ;
      RECT 174.335 125.795 174.545 126.510 ;
      RECT 19.000 127.700 116.400 129.300 ;
      RECT 19.000 119.700 127.400 121.300 ;
      RECT 19.000 124.500 120.800 126.100 ;
      RECT 19.000 121.300 125.200 122.900 ;
      RECT 147.455 157.715 148.140 167.245 ;
      RECT 148.420 156.035 149.580 167.245 ;
      RECT 150.335 166.530 150.545 167.245 ;
      RECT 151.775 156.035 152.460 167.245 ;
      RECT 152.740 156.025 153.425 167.245 ;
      RECT 153.695 164.435 154.860 167.245 ;
      RECT 134.700 160.600 135.100 174.900 ;
      RECT 19.000 126.100 118.600 127.700 ;
      RECT 136.100 136.240 136.500 197.400 ;
      RECT 19.000 122.900 123.000 124.500 ;
      RECT 145.970 175.650 147.870 179.600 ;
      RECT 153.370 179.300 156.270 179.700 ;
      RECT 154.960 169.055 156.800 169.345 ;
      RECT 152.750 175.650 156.270 180.160 ;
      RECT 145.970 179.920 147.870 183.400 ;
      RECT 139.370 179.920 141.270 184.300 ;
      RECT 156.210 179.310 156.890 186.970 ;
      RECT 152.130 179.300 152.530 186.980 ;
      RECT 154.090 186.580 155.990 186.980 ;
      RECT 155.090 192.550 155.990 192.950 ;
      RECT 153.470 183.000 155.990 193.900 ;
      RECT 154.330 189.295 155.030 196.300 ;
      RECT 149.380 166.955 150.540 168.085 ;
      RECT 141.490 179.570 141.890 197.400 ;
      RECT 148.090 179.570 148.490 197.400 ;
      RECT 139.370 175.650 141.270 179.600 ;
      RECT 155.090 192.140 156.610 199.300 ;
      RECT 161.400 198.900 162.800 199.320 ;
      RECT 160.780 197.000 161.180 199.410 ;
      RECT 133.300 203.200 133.700 205.900 ;
      RECT 145.535 140.915 146.700 149.190 ;
      RECT 147.935 129.155 149.100 151.285 ;
      RECT 145.060 124.535 146.700 152.545 ;
      RECT 149.860 132.930 151.980 155.905 ;
      RECT 152.735 136.715 152.945 159.685 ;
      RECT 149.375 140.915 149.585 143.305 ;
      RECT 161.160 142.595 163.000 142.885 ;
      RECT 146.975 140.915 147.185 143.725 ;
      RECT 156.575 141.335 156.785 143.725 ;
      RECT 158.495 141.335 158.705 143.725 ;
      RECT 142.655 140.075 142.865 144.145 ;
      RECT 144.580 134.195 145.745 144.565 ;
      RECT 160.415 140.075 161.100 144.565 ;
      RECT 151.780 148.475 152.465 155.065 ;
      RECT 161.855 151.835 162.065 155.065 ;
      RECT 160.415 154.770 160.625 155.485 ;
      RECT 156.095 154.775 156.305 155.490 ;
      RECT 148.895 153.095 149.105 155.905 ;
      RECT 161.160 150.155 163.000 150.445 ;
      RECT 155.615 155.610 155.825 156.325 ;
      RECT 151.360 156.025 151.570 156.745 ;
      RECT 160.415 156.035 160.625 156.750 ;
      RECT 154.655 156.450 154.865 157.165 ;
      RECT 162.335 152.255 162.545 157.165 ;
      RECT 150.335 156.035 150.545 158.005 ;
      RECT 159.935 156.035 160.145 158.005 ;
      RECT 161.160 157.715 163.000 158.005 ;
      RECT 155.615 157.715 155.825 158.845 ;
      RECT 149.375 155.195 149.585 159.265 ;
      RECT 154.655 158.550 154.865 159.265 ;
      RECT 157.055 158.545 157.265 159.265 ;
      RECT 145.540 148.475 147.660 151.285 ;
      RECT 156.575 158.970 156.785 159.685 ;
      RECT 153.695 156.035 153.905 160.105 ;
      RECT 158.975 159.385 159.185 160.105 ;
      RECT 160.415 159.395 160.625 160.525 ;
      RECT 154.960 161.495 156.800 161.785 ;
      RECT 159.455 156.875 159.665 162.625 ;
      RECT 157.535 156.035 159.180 163.045 ;
      RECT 158.495 159.395 158.705 163.045 ;
      RECT 144.580 153.095 145.745 163.885 ;
      RECT 147.935 153.095 149.100 163.885 ;
      RECT 157.055 162.335 157.265 163.885 ;
      RECT 158.015 163.170 158.225 163.885 ;
      RECT 158.975 161.495 159.660 163.885 ;
      RECT 160.895 158.555 161.105 163.885 ;
      RECT 161.855 159.395 162.065 163.885 ;
      RECT 162.335 163.170 162.545 163.885 ;
      RECT 144.575 147.635 144.785 148.765 ;
      RECT 158.500 148.475 163.020 164.680 ;
      RECT 161.160 165.275 163.000 165.565 ;
      RECT 142.655 164.015 142.865 166.405 ;
      RECT 148.415 165.690 148.625 166.405 ;
      RECT 153.215 162.755 153.425 166.405 ;
      RECT 160.895 150.995 161.105 151.710 ;
      RECT 158.015 148.475 158.225 152.125 ;
      RECT 154.655 143.010 154.865 143.725 ;
      RECT 159.935 151.415 160.145 152.135 ;
      RECT 144.095 148.050 144.305 148.765 ;
      RECT 144.575 152.670 144.785 153.385 ;
      RECT 154.960 153.935 156.800 154.225 ;
      RECT 158.015 143.435 158.225 144.565 ;
      RECT 158.980 147.635 160.145 154.645 ;
      RECT 157.055 143.855 157.265 144.575 ;
      RECT 160.415 145.110 160.625 145.825 ;
      RECT 154.960 146.375 156.800 146.665 ;
      RECT 156.100 144.275 157.740 147.505 ;
      RECT 158.495 147.210 158.705 147.925 ;
      RECT 159.935 147.215 160.145 148.555 ;
      RECT 154.660 136.715 155.820 138.265 ;
      RECT 159.935 132.095 160.145 136.165 ;
      RECT 154.960 138.815 156.800 139.105 ;
      RECT 143.620 132.935 143.820 139.945 ;
      RECT 160.415 125.370 160.625 126.085 ;
      RECT 161.855 121.170 162.065 121.885 ;
      RECT 162.815 136.290 163.025 139.945 ;
      RECT 142.175 134.195 142.860 136.585 ;
      RECT 161.855 129.155 162.545 133.645 ;
      RECT 143.135 125.375 143.345 126.095 ;
      RECT 150.820 124.955 151.505 126.085 ;
      RECT 156.575 132.935 156.785 133.655 ;
      RECT 153.215 124.955 153.425 132.385 ;
      RECT 153.695 125.220 153.905 137.005 ;
      RECT 148.415 132.930 148.625 133.645 ;
      RECT 152.255 125.785 152.465 126.505 ;
      RECT 154.175 125.790 154.385 126.505 ;
      RECT 145.055 139.650 145.265 140.365 ;
      RECT 151.270 133.460 151.505 140.365 ;
      RECT 155.615 133.345 155.825 134.065 ;
      RECT 154.180 135.920 155.820 140.785 ;
      RECT 150.335 122.015 151.020 126.085 ;
      RECT 162.335 136.715 162.545 140.785 ;
      RECT 156.095 136.290 156.305 137.005 ;
      RECT 155.135 132.930 155.345 133.645 ;
      RECT 157.535 136.290 157.745 137.005 ;
      RECT 156.575 125.375 156.785 126.095 ;
      RECT 159.455 132.935 159.665 137.005 ;
      RECT 156.575 126.635 156.785 129.025 ;
      RECT 146.975 125.370 147.185 126.085 ;
      RECT 158.015 133.355 158.225 134.070 ;
      RECT 154.655 125.370 154.865 126.085 ;
      RECT 158.975 129.155 159.185 133.645 ;
      RECT 158.020 121.220 158.700 124.825 ;
      RECT 159.935 128.730 160.145 129.445 ;
      RECT 160.895 121.175 161.105 121.895 ;
      RECT 146.015 126.210 146.225 126.925 ;
      RECT 160.895 128.580 161.105 133.645 ;
      RECT 160.420 119.075 161.060 119.365 ;
      RECT 149.860 125.795 151.980 126.925 ;
      RECT 150.335 120.330 150.545 121.045 ;
      RECT 160.415 133.355 162.060 137.005 ;
      RECT 142.655 122.435 142.865 124.825 ;
      RECT 150.815 132.515 151.025 137.845 ;
      RECT 144.095 140.490 144.305 141.205 ;
      RECT 148.895 124.530 149.105 125.245 ;
      RECT 148.895 137.555 149.105 141.205 ;
      RECT 149.855 132.095 150.065 141.205 ;
      RECT 162.815 121.585 163.025 122.305 ;
      RECT 153.215 133.775 154.860 141.205 ;
      RECT 155.620 134.195 157.260 141.205 ;
      RECT 155.135 119.915 155.345 121.885 ;
      RECT 161.855 140.490 162.065 141.205 ;
      RECT 161.855 130.415 162.065 133.645 ;
      RECT 156.095 121.595 156.305 122.310 ;
      RECT 148.415 122.845 148.625 123.565 ;
      RECT 161.160 127.475 163.000 127.765 ;
      RECT 154.960 123.695 156.800 123.985 ;
      RECT 154.655 127.890 154.865 128.605 ;
      RECT 155.620 120.755 157.740 121.885 ;
      RECT 156.580 121.595 157.265 128.605 ;
      RECT 157.535 132.095 158.220 133.225 ;
      RECT 159.455 127.890 159.665 128.605 ;
      RECT 158.975 121.170 159.185 121.885 ;
      RECT 148.415 141.330 148.625 142.045 ;
      RECT 146.975 121.595 147.185 122.725 ;
      RECT 161.160 119.915 163.000 120.205 ;
      RECT 142.655 137.550 142.865 138.265 ;
      RECT 161.375 141.330 161.585 142.045 ;
      RECT 145.055 125.370 145.265 126.085 ;
      RECT 144.580 129.155 145.260 132.385 ;
      RECT 161.375 120.755 161.585 121.470 ;
      RECT 146.495 123.275 146.705 126.085 ;
      RECT 154.960 131.255 156.800 131.545 ;
      RECT 142.655 126.635 142.865 129.025 ;
      RECT 161.160 135.035 163.000 135.325 ;
      RECT 147.455 141.345 147.665 142.065 ;
      RECT 136.100 62.800 136.500 112.280 ;
      RECT 81.170 27.000 83.070 30.400 ;
      RECT 81.170 26.430 83.070 26.730 ;
      RECT 159.360 52.900 159.760 78.205 ;
      RECT 150.720 52.900 151.120 79.885 ;
      RECT 158.400 52.900 158.800 79.885 ;
      RECT 147.840 52.900 148.240 80.305 ;
      RECT 154.560 52.900 154.960 81.145 ;
      RECT 148.800 52.900 149.200 81.985 ;
      RECT 156.480 52.900 156.880 81.985 ;
      RECT 159.935 52.900 160.720 82.405 ;
      RECT 151.680 52.900 152.080 82.825 ;
      RECT 152.640 52.900 153.040 87.025 ;
      RECT 159.940 52.900 161.680 87.025 ;
      RECT 154.175 52.900 155.920 87.445 ;
      RECT 153.600 52.900 154.000 88.285 ;
      RECT 149.760 52.900 150.160 96.265 ;
      RECT 157.060 52.900 157.840 102.145 ;
      RECT 142.175 87.575 142.860 110.545 ;
      RECT 158.495 80.855 159.660 105.925 ;
      RECT 160.895 91.355 161.105 95.845 ;
      RECT 159.455 91.355 160.140 107.185 ;
      RECT 153.695 91.355 153.905 96.265 ;
      RECT 152.735 91.565 152.945 96.685 ;
      RECT 144.100 82.580 149.585 97.105 ;
      RECT 146.975 87.575 147.665 97.525 ;
      RECT 147.935 91.830 148.625 98.365 ;
      RECT 142.655 90.515 143.345 99.205 ;
      RECT 157.540 85.055 158.705 100.045 ;
      RECT 144.580 87.995 145.745 102.145 ;
      RECT 150.820 87.155 151.980 102.145 ;
      RECT 141.215 86.315 141.425 103.405 ;
      RECT 144.575 106.475 144.785 112.225 ;
      RECT 153.700 110.675 154.865 112.225 ;
      RECT 142.660 102.760 143.345 103.405 ;
      RECT 161.160 112.355 163.000 112.645 ;
      RECT 142.655 111.935 142.865 113.485 ;
      RECT 143.615 109.835 143.825 113.485 ;
      RECT 155.615 111.515 155.825 113.485 ;
      RECT 158.020 103.115 158.705 113.485 ;
      RECT 151.775 113.190 151.985 113.905 ;
      RECT 158.015 111.515 158.225 113.905 ;
      RECT 153.215 113.195 153.425 113.910 ;
      RECT 160.895 113.195 161.105 113.910 ;
      RECT 145.055 113.195 145.265 114.220 ;
      RECT 148.415 111.935 148.625 114.325 ;
      RECT 152.255 111.095 152.465 114.325 ;
      RECT 155.135 113.610 155.345 114.325 ;
      RECT 156.575 113.610 156.785 114.325 ;
      RECT 143.615 114.030 143.825 114.745 ;
      RECT 147.455 113.195 147.665 114.745 ;
      RECT 150.335 113.195 150.545 114.745 ;
      RECT 157.535 114.025 157.745 114.745 ;
      RECT 151.365 106.475 152.945 115.120 ;
      RECT 149.375 114.450 149.585 115.165 ;
      RECT 162.815 114.035 163.025 115.165 ;
      RECT 156.095 114.035 156.305 115.585 ;
      RECT 149.380 110.675 150.065 116.425 ;
      RECT 154.960 116.135 156.800 116.425 ;
      RECT 160.420 114.035 161.105 116.845 ;
      RECT 158.975 107.735 159.185 117.265 ;
      RECT 148.415 115.295 148.625 117.685 ;
      RECT 158.495 114.035 158.705 117.685 ;
      RECT 161.375 117.395 161.585 118.115 ;
      RECT 147.940 95.130 149.105 118.525 ;
      RECT 155.615 117.810 155.825 118.525 ;
      RECT 154.660 117.020 157.260 118.525 ;
      RECT 162.335 116.555 162.545 118.525 ;
      RECT 146.975 102.690 147.185 103.405 ;
      RECT 151.775 102.690 151.985 103.405 ;
      RECT 152.735 99.335 153.900 103.405 ;
      RECT 149.855 102.695 150.065 103.825 ;
      RECT 159.935 103.105 160.145 103.825 ;
      RECT 143.615 103.530 143.825 104.245 ;
      RECT 161.160 104.795 163.000 105.085 ;
      RECT 147.455 103.115 147.675 105.505 ;
      RECT 148.895 103.955 149.105 105.925 ;
      RECT 157.055 105.210 157.265 105.925 ;
      RECT 154.960 108.575 156.800 108.865 ;
      RECT 154.655 105.215 154.865 105.935 ;
      RECT 142.655 106.050 142.865 106.765 ;
      RECT 150.340 98.915 151.025 106.765 ;
      RECT 158.015 104.375 158.225 107.185 ;
      RECT 156.095 95.130 156.305 95.845 ;
      RECT 148.415 108.990 148.625 109.705 ;
      RECT 144.575 95.135 144.785 95.855 ;
      RECT 156.100 107.735 157.265 109.705 ;
      RECT 160.895 107.310 161.105 108.025 ;
      RECT 147.455 109.830 147.665 110.545 ;
      RECT 145.055 106.475 145.265 110.965 ;
      RECT 145.535 103.115 145.745 110.965 ;
      RECT 161.160 97.235 163.000 97.525 ;
      RECT 142.655 95.975 142.865 98.365 ;
      RECT 145.055 97.650 145.265 98.365 ;
      RECT 146.020 101.855 146.705 110.965 ;
      RECT 143.615 96.395 143.825 98.785 ;
      RECT 148.900 98.075 151.500 98.785 ;
      RECT 150.335 109.835 150.545 110.965 ;
      RECT 146.015 98.490 146.225 99.205 ;
      RECT 153.215 98.490 153.425 99.205 ;
      RECT 157.535 98.490 157.745 99.205 ;
      RECT 146.495 98.915 146.705 100.045 ;
      RECT 149.375 98.915 149.585 100.045 ;
      RECT 150.820 110.675 151.980 110.965 ;
      RECT 145.535 98.915 145.745 100.465 ;
      RECT 143.615 98.915 144.300 101.305 ;
      RECT 154.960 101.015 156.800 101.305 ;
      RECT 158.015 110.250 158.225 110.965 ;
      RECT 148.895 98.915 149.105 102.145 ;
      RECT 149.855 98.915 150.065 102.145 ;
      RECT 149.790 110.675 150.065 111.805 ;
      RECT 152.255 99.755 152.465 102.145 ;
      RECT 155.615 106.050 155.825 108.025 ;
      RECT 144.575 102.270 144.785 102.985 ;
      RECT 154.655 101.855 154.865 102.985 ;
      RECT 156.100 99.755 157.745 102.985 ;
      RECT 162.815 99.335 163.025 102.985 ;
      RECT 148.415 99.755 148.625 103.340 ;
      RECT 159.935 98.075 160.625 111.805 ;
      RECT 117.600 71.750 118.000 72.150 ;
      RECT 119.800 71.750 120.200 72.150 ;
      RECT 122.000 71.750 122.400 72.150 ;
      RECT 115.400 71.750 115.800 72.150 ;
      RECT 153.215 90.515 153.425 91.645 ;
      RECT 150.335 88.835 150.545 92.065 ;
      RECT 156.575 90.095 156.785 92.065 ;
      RECT 146.495 91.565 146.705 92.285 ;
      RECT 145.055 91.355 145.265 92.905 ;
      RECT 151.295 92.190 151.505 92.905 ;
      RECT 154.960 93.455 156.800 93.745 ;
      RECT 152.255 91.355 152.465 94.165 ;
      RECT 154.175 91.355 154.860 94.165 ;
      RECT 161.160 82.115 163.000 82.405 ;
      RECT 130.800 71.750 131.200 72.150 ;
      RECT 159.455 82.950 159.665 83.665 ;
      RECT 145.535 83.370 145.745 84.085 ;
      RECT 147.455 83.370 147.665 84.085 ;
      RECT 158.975 82.955 159.185 84.085 ;
      RECT 158.015 82.115 158.225 84.505 ;
      RECT 162.815 83.795 163.025 84.510 ;
      RECT 160.895 83.870 161.105 84.590 ;
      RECT 161.375 84.630 161.585 85.345 ;
      RECT 159.935 83.795 160.145 85.765 ;
      RECT 154.960 85.895 156.800 86.185 ;
      RECT 133.000 71.750 133.400 72.150 ;
      RECT 158.015 85.895 158.225 87.025 ;
      RECT 124.200 71.750 124.600 72.150 ;
      RECT 126.400 71.750 126.800 72.150 ;
      RECT 162.815 86.730 163.025 87.445 ;
      RECT 157.055 87.150 157.265 87.865 ;
      RECT 158.975 85.895 159.185 87.865 ;
      RECT 128.600 71.750 129.000 72.150 ;
      RECT 155.615 87.570 155.825 88.285 ;
      RECT 154.655 87.990 154.865 88.705 ;
      RECT 142.655 88.410 142.865 89.125 ;
      RECT 144.575 83.795 144.785 89.125 ;
      RECT 156.095 88.410 156.305 89.125 ;
      RECT 160.895 83.795 162.060 89.125 ;
      RECT 148.420 87.995 149.105 89.545 ;
      RECT 151.775 83.795 151.985 89.545 ;
      RECT 161.160 89.675 163.000 89.965 ;
      RECT 152.255 83.795 152.945 90.385 ;
      RECT 143.135 83.795 143.345 90.805 ;
      RECT 146.015 88.415 146.225 90.805 ;
      RECT 149.375 89.675 149.585 90.805 ;
      RECT 144.575 90.510 144.785 91.225 ;
      RECT 146.975 90.515 147.185 91.540 ;
      RECT 143.615 82.955 144.300 91.645 ;
      RECT 8.900 39.700 9.300 62.400 ;
      RECT 22.700 41.000 23.100 62.400 ;
      RECT 36.500 42.300 36.900 62.400 ;
      RECT 50.300 43.600 50.700 62.400 ;
      RECT 64.100 44.900 64.500 62.400 ;
      RECT 77.900 46.200 78.300 62.400 ;
      RECT 54.920 62.000 55.320 66.110 ;
      RECT 58.370 65.730 60.270 66.110 ;
      RECT 61.150 62.000 61.550 66.110 ;
      RECT 65.570 65.730 67.470 66.110 ;
      RECT 68.720 62.000 69.120 66.110 ;
      RECT 72.170 65.730 74.070 66.110 ;
      RECT 74.950 62.000 75.350 66.110 ;
      RECT 79.370 65.730 81.270 66.110 ;
      RECT 43.350 61.200 46.470 66.520 ;
      RECT 57.150 61.200 60.270 66.520 ;
      RECT 70.950 61.200 74.070 66.520 ;
      RECT 51.150 65.240 53.670 69.550 ;
      RECT 64.950 65.240 67.470 69.550 ;
      RECT 78.750 65.240 81.270 69.550 ;
      RECT 74.800 51.500 75.200 54.000 ;
      RECT 43.330 53.600 43.730 56.100 ;
      RECT 53.800 53.600 54.200 56.100 ;
      RECT 57.130 53.600 57.530 56.100 ;
      RECT 67.600 53.600 68.000 56.100 ;
      RECT 70.930 53.600 71.330 56.100 ;
      RECT 81.400 53.600 81.800 56.100 ;
      RECT 44.690 58.450 45.590 58.830 ;
      RECT 51.990 58.450 52.890 58.830 ;
      RECT 58.490 58.450 59.390 58.830 ;
      RECT 65.790 58.450 66.690 58.830 ;
      RECT 72.290 58.450 73.190 58.830 ;
      RECT 79.590 58.450 80.490 58.830 ;
      RECT 51.370 54.650 52.890 59.240 ;
      RECT 65.170 54.650 66.690 59.240 ;
      RECT 78.970 54.650 80.490 59.240 ;
      RECT 49.400 52.500 49.800 60.800 ;
      RECT 53.110 58.430 53.510 60.800 ;
      RECT 63.200 52.500 63.600 60.800 ;
      RECT 66.910 58.430 67.310 60.800 ;
      RECT 77.000 52.500 77.400 60.800 ;
      RECT 80.710 58.430 81.110 60.800 ;
      RECT 44.070 57.960 45.590 61.600 ;
      RECT 57.870 57.960 59.390 61.600 ;
      RECT 71.670 57.960 73.190 61.600 ;
      RECT 67.690 60.400 68.090 66.090 ;
      RECT 74.290 59.600 74.690 66.090 ;
      RECT 81.490 60.400 81.890 66.090 ;
      RECT 42.200 58.450 42.600 62.400 ;
      RECT 48.200 58.450 48.600 62.400 ;
      RECT 44.570 65.730 46.470 66.110 ;
      RECT 56.000 58.450 56.400 62.400 ;
      RECT 62.000 58.450 62.400 62.400 ;
      RECT 47.350 62.000 47.750 66.110 ;
      RECT 69.800 58.450 70.200 62.400 ;
      RECT 75.800 58.450 76.200 62.400 ;
      RECT 51.770 65.730 53.670 66.110 ;
      RECT 45.810 58.430 46.210 64.010 ;
      RECT 59.610 58.430 60.010 64.010 ;
      RECT 73.410 58.430 73.810 64.010 ;
      RECT 46.690 59.600 47.090 66.090 ;
      RECT 53.890 60.400 54.290 66.090 ;
      RECT 60.490 59.600 60.890 66.090 ;
      RECT 37.570 54.650 39.090 59.240 ;
      RECT 27.320 62.000 27.720 66.110 ;
      RECT 30.770 65.730 32.670 66.110 ;
      RECT 1.250 69.095 1.950 69.705 ;
      RECT 11.710 58.430 12.110 60.800 ;
      RECT 21.800 52.500 22.200 60.800 ;
      RECT 25.510 58.430 25.910 60.800 ;
      RECT 35.600 52.500 36.000 60.800 ;
      RECT 39.310 58.430 39.710 60.800 ;
      RECT 7.850 60.400 8.550 69.705 ;
      RECT 33.550 62.000 33.950 66.110 ;
      RECT 5.600 51.500 6.000 55.000 ;
      RECT 12.400 53.600 12.800 56.100 ;
      RECT 15.730 53.600 16.130 56.100 ;
      RECT 26.200 53.600 26.600 56.100 ;
      RECT 16.470 57.960 17.990 61.600 ;
      RECT 30.270 57.960 31.790 61.600 ;
      RECT 29.530 53.600 29.930 56.100 ;
      RECT 40.000 53.600 40.400 56.100 ;
      RECT 37.970 65.730 39.870 66.110 ;
      RECT 41.120 62.000 41.520 66.110 ;
      RECT 14.600 58.450 15.000 62.400 ;
      RECT 20.600 58.450 21.000 62.400 ;
      RECT 10.370 65.730 12.270 66.110 ;
      RECT 28.400 58.450 28.800 62.400 ;
      RECT 34.400 58.450 34.800 62.400 ;
      RECT 15.750 61.200 18.870 66.520 ;
      RECT 29.550 61.200 32.670 66.520 ;
      RECT 13.520 62.000 13.920 66.110 ;
      RECT 10.590 58.450 11.490 58.830 ;
      RECT 17.090 58.450 17.990 58.830 ;
      RECT 24.390 58.450 25.290 58.830 ;
      RECT 30.890 58.450 31.790 58.830 ;
      RECT 38.190 58.450 39.090 58.830 ;
      RECT 16.970 65.730 18.870 66.110 ;
      RECT 19.750 62.000 20.150 66.110 ;
      RECT 18.210 58.430 18.610 64.010 ;
      RECT 32.010 58.430 32.410 64.010 ;
      RECT 9.750 65.240 12.270 69.550 ;
      RECT 23.550 65.240 26.070 69.550 ;
      RECT 37.350 65.240 39.870 69.550 ;
      RECT 12.490 60.400 12.890 66.090 ;
      RECT 19.090 59.600 19.490 66.090 ;
      RECT 26.290 60.400 26.690 66.090 ;
      RECT 32.890 59.600 33.290 66.090 ;
      RECT 40.090 60.400 40.490 66.090 ;
      RECT 24.170 65.730 26.070 66.110 ;
      RECT 9.970 54.650 11.490 59.240 ;
      RECT 23.770 54.650 25.290 59.240 ;
      RECT 58.010 26.640 58.410 28.000 ;
      RECT 62.610 26.640 63.010 28.000 ;
      RECT 67.890 26.630 68.290 28.800 ;
      RECT 71.810 26.640 72.210 28.800 ;
      RECT 77.410 26.630 77.810 28.800 ;
      RECT 63.290 26.630 63.690 29.600 ;
      RECT 72.490 26.630 72.890 29.600 ;
      RECT 80.410 25.220 80.810 30.400 ;
      RECT 75.290 26.670 77.190 26.970 ;
      RECT 58.690 26.630 59.090 31.200 ;
      RECT 65.470 26.160 66.990 31.200 ;
      RECT 70.070 26.160 71.590 32.000 ;
      RECT 74.670 26.160 77.190 32.000 ;
      RECT 67.210 26.640 67.610 32.800 ;
      RECT 53.500 23.500 53.900 37.500 ;
      RECT 54.300 28.400 54.700 39.300 ;
      RECT 56.890 26.680 57.790 26.980 ;
      RECT 61.490 26.680 62.390 26.980 ;
      RECT 66.090 26.680 66.990 26.980 ;
      RECT 70.690 26.680 71.590 26.980 ;
      RECT 78.090 23.500 78.490 27.020 ;
      RECT 56.270 24.940 57.790 27.460 ;
      RECT 60.870 24.940 62.390 27.460 ;
      RECT 137.910 42.430 138.310 49.250 ;
      RECT 142.910 42.430 143.310 49.250 ;
      RECT 135.170 41.960 137.690 51.900 ;
      RECT 140.170 41.960 142.690 51.900 ;
      RECT 131.700 37.100 132.100 61.600 ;
      RECT 138.800 42.420 139.200 55.000 ;
      RECT 143.800 42.420 144.200 55.000 ;
      RECT 133.200 40.000 133.600 63.200 ;
      RECT 132.500 38.900 132.900 64.020 ;
      RECT 134.000 39.100 134.400 60.000 ;
      RECT 127.370 65.730 129.270 66.110 ;
      RECT 126.150 61.200 129.270 66.520 ;
      RECT 130.150 62.000 130.550 66.110 ;
      RECT 125.000 58.450 125.400 62.400 ;
      RECT 131.000 58.450 131.400 62.400 ;
      RECT 123.920 62.000 124.320 66.110 ;
      RECT 122.800 53.600 123.200 56.100 ;
      RECT 126.130 53.600 126.530 56.100 ;
      RECT 128.610 58.430 129.010 64.010 ;
      RECT 124.800 51.500 125.200 54.000 ;
      RECT 122.890 60.400 123.290 66.090 ;
      RECT 129.490 59.600 129.890 66.090 ;
      RECT 127.490 58.450 128.390 58.830 ;
      RECT 126.870 57.960 128.390 61.600 ;
      RECT 90.800 52.500 91.200 60.800 ;
      RECT 94.510 58.430 94.910 60.800 ;
      RECT 104.600 52.500 105.000 60.800 ;
      RECT 108.310 58.430 108.710 60.800 ;
      RECT 84.730 53.600 85.130 56.100 ;
      RECT 95.200 53.600 95.600 56.100 ;
      RECT 98.530 53.600 98.930 56.100 ;
      RECT 83.600 58.450 84.000 62.400 ;
      RECT 89.600 58.450 90.000 62.400 ;
      RECT 91.700 47.500 92.100 62.400 ;
      RECT 97.400 58.450 97.800 62.400 ;
      RECT 103.400 58.450 103.800 62.400 ;
      RECT 105.500 48.800 105.900 62.400 ;
      RECT 111.200 58.450 111.600 62.400 ;
      RECT 117.200 58.450 117.600 62.400 ;
      RECT 119.300 50.100 119.700 62.400 ;
      RECT 118.400 52.500 118.800 60.800 ;
      RECT 92.550 65.240 95.070 69.550 ;
      RECT 106.350 65.240 108.870 69.550 ;
      RECT 109.000 53.600 109.400 56.100 ;
      RECT 112.330 53.600 112.730 56.100 ;
      RECT 120.150 65.240 122.670 69.550 ;
      RECT 122.110 58.430 122.510 60.800 ;
      RECT 87.210 58.430 87.610 64.010 ;
      RECT 101.010 58.430 101.410 64.010 ;
      RECT 114.810 58.430 115.210 64.010 ;
      RECT 98.550 61.200 101.670 66.520 ;
      RECT 112.350 61.200 115.470 66.520 ;
      RECT 86.090 58.450 86.990 58.830 ;
      RECT 88.090 59.600 88.490 66.090 ;
      RECT 95.290 60.400 95.690 66.090 ;
      RECT 101.890 59.600 102.290 66.090 ;
      RECT 109.090 60.400 109.490 66.090 ;
      RECT 115.690 59.600 116.090 66.090 ;
      RECT 84.750 61.200 87.870 66.520 ;
      RECT 85.470 57.960 86.990 61.600 ;
      RECT 93.390 58.450 94.290 58.830 ;
      RECT 99.890 58.450 100.790 58.830 ;
      RECT 107.190 58.450 108.090 58.830 ;
      RECT 113.690 58.450 114.590 58.830 ;
      RECT 120.990 58.450 121.890 58.830 ;
      RECT 99.270 57.960 100.790 61.600 ;
      RECT 92.770 54.650 94.290 59.240 ;
      RECT 106.570 54.650 108.090 59.240 ;
      RECT 120.370 54.650 121.890 59.240 ;
      RECT 113.070 57.960 114.590 61.600 ;
      RECT 82.520 62.000 82.920 66.110 ;
      RECT 85.970 65.730 87.870 66.110 ;
      RECT 88.750 62.000 89.150 66.110 ;
      RECT 93.170 65.730 95.070 66.110 ;
      RECT 96.320 62.000 96.720 66.110 ;
      RECT 99.770 65.730 101.670 66.110 ;
      RECT 102.550 62.000 102.950 66.110 ;
      RECT 106.970 65.730 108.870 66.110 ;
      RECT 110.120 62.000 110.520 66.110 ;
      RECT 113.570 65.730 115.470 66.110 ;
      RECT 116.350 62.000 116.750 66.110 ;
      RECT 120.770 65.730 122.670 66.110 ;
      RECT 83.970 26.380 84.370 28.800 ;
      RECT 88.990 26.650 89.390 28.800 ;
      RECT 86.870 27.000 88.770 32.800 ;
      RECT 83.290 26.650 83.690 28.000 ;
      RECT 86.110 25.220 86.510 30.400 ;
      RECT 86.870 26.430 88.770 26.730 ;
      RECT 92.050 30.000 92.750 35.705 ;
      RECT 89.670 26.380 90.070 30.400 ;
      RECT 141.100 26.450 141.500 30.400 ;
      RECT 147.100 26.450 147.500 30.400 ;
      RECT 160.900 26.450 161.300 30.400 ;
      RECT 157.390 26.450 158.290 26.830 ;
      RECT 156.770 25.960 158.290 29.600 ;
      RECT 146.250 30.000 146.650 34.110 ;
      RECT 157.270 33.730 159.170 34.110 ;
      RECT 160.050 30.000 160.450 34.110 ;
      RECT 142.250 29.200 145.370 34.520 ;
      RECT 156.050 29.200 159.170 34.520 ;
      RECT 138.210 26.430 138.610 28.800 ;
      RECT 136.470 22.650 137.990 27.240 ;
      RECT 134.500 28.400 134.900 31.200 ;
      RECT 138.990 28.400 139.390 34.090 ;
      RECT 145.590 27.600 145.990 34.090 ;
      RECT 159.390 27.600 159.790 34.090 ;
      RECT 136.250 33.240 138.770 37.550 ;
      RECT 149.200 30.000 149.600 38.400 ;
      RECT 140.200 22.600 140.600 29.600 ;
      RECT 135.170 39.960 135.570 40.360 ;
      RECT 136.870 33.730 138.770 34.110 ;
      RECT 140.020 30.000 140.420 34.110 ;
      RECT 143.470 33.730 145.370 34.110 ;
      RECT 144.710 26.430 145.110 31.200 ;
      RECT 142.970 25.960 144.490 29.600 ;
      RECT 137.090 26.450 137.990 26.830 ;
      RECT 140.170 39.960 140.570 40.360 ;
      RECT 143.590 26.450 144.490 26.830 ;
      RECT 135.790 42.480 137.690 42.760 ;
      RECT 140.790 42.480 142.690 42.760 ;
      RECT 158.510 26.430 158.910 31.200 ;
      RECT 135.400 27.600 135.800 30.400 ;
      RECT 169.920 52.900 170.320 81.985 ;
      RECT 170.880 52.900 171.280 81.985 ;
      RECT 172.800 52.900 173.200 81.985 ;
      RECT 173.760 52.900 174.160 82.405 ;
      RECT 163.200 52.900 163.985 82.825 ;
      RECT 164.160 52.900 164.560 83.245 ;
      RECT 168.000 52.900 168.400 83.245 ;
      RECT 168.960 52.900 169.740 83.245 ;
      RECT 171.840 52.900 172.240 83.245 ;
      RECT 165.695 52.900 166.480 87.025 ;
      RECT 166.180 52.900 167.440 87.025 ;
      RECT 244.100 44.470 244.500 62.400 ;
      RECT 164.255 52.900 165.520 93.325 ;
      RECT 174.720 52.900 175.120 95.425 ;
      RECT 170.495 91.355 170.705 95.005 ;
      RECT 166.175 94.715 166.385 95.845 ;
      RECT 177.695 91.775 177.905 95.845 ;
      RECT 168.580 91.355 169.745 96.685 ;
      RECT 164.735 87.575 165.420 98.365 ;
      RECT 167.620 92.615 168.300 99.205 ;
      RECT 178.180 81.695 178.865 102.145 ;
      RECT 179.615 82.115 180.300 102.145 ;
      RECT 166.175 92.615 167.340 102.985 ;
      RECT 173.855 83.790 174.540 102.985 ;
      RECT 176.255 84.215 176.465 102.985 ;
      RECT 174.820 87.995 175.505 110.965 ;
      RECT 175.775 83.795 176.945 114.745 ;
      RECT 178.655 85.475 178.865 114.745 ;
      RECT 180.575 83.375 180.785 114.745 ;
      RECT 172.415 88.835 175.020 118.525 ;
      RECT 177.215 85.055 177.425 118.525 ;
      RECT 165.695 98.490 165.905 99.205 ;
      RECT 170.015 101.850 170.225 102.565 ;
      RECT 167.615 95.130 167.825 95.845 ;
      RECT 173.375 96.395 173.585 102.985 ;
      RECT 170.975 98.490 171.185 99.205 ;
      RECT 181.055 98.910 181.265 99.625 ;
      RECT 179.135 96.815 179.345 102.985 ;
      RECT 163.295 100.175 163.505 103.405 ;
      RECT 164.255 95.555 164.465 103.405 ;
      RECT 165.220 100.175 165.905 103.405 ;
      RECT 170.975 100.175 171.185 103.405 ;
      RECT 171.455 102.690 171.665 103.405 ;
      RECT 171.935 102.275 172.145 103.405 ;
      RECT 172.415 102.690 172.625 103.405 ;
      RECT 181.060 102.695 181.745 104.665 ;
      RECT 164.255 105.210 164.465 105.925 ;
      RECT 181.055 103.535 181.265 105.925 ;
      RECT 168.095 103.535 168.305 106.660 ;
      RECT 166.655 98.915 166.865 106.765 ;
      RECT 165.215 106.470 165.425 107.185 ;
      RECT 163.775 108.155 163.985 109.705 ;
      RECT 169.055 106.475 169.265 110.545 ;
      RECT 164.735 110.250 164.945 110.965 ;
      RECT 166.175 106.475 167.340 110.965 ;
      RECT 167.620 107.735 167.820 110.965 ;
      RECT 168.095 99.125 169.260 100.465 ;
      RECT 165.215 110.670 165.425 111.385 ;
      RECT 181.055 110.255 181.265 111.385 ;
      RECT 168.095 110.675 168.305 111.390 ;
      RECT 165.695 110.675 165.905 111.805 ;
      RECT 170.975 104.795 171.185 112.225 ;
      RECT 169.060 111.095 170.220 113.485 ;
      RECT 177.695 112.770 177.905 113.485 ;
      RECT 179.615 110.675 179.825 113.485 ;
      RECT 173.855 104.375 174.065 113.905 ;
      RECT 163.295 109.415 164.940 114.325 ;
      RECT 163.780 113.195 165.900 114.325 ;
      RECT 166.175 113.610 166.385 114.325 ;
      RECT 167.135 113.195 167.345 114.325 ;
      RECT 170.495 111.095 170.705 114.325 ;
      RECT 173.375 113.610 173.585 114.325 ;
      RECT 175.295 113.610 175.505 114.325 ;
      RECT 171.455 113.615 171.665 114.335 ;
      RECT 173.855 113.970 174.540 114.745 ;
      RECT 170.980 95.555 171.665 101.305 ;
      RECT 164.735 98.915 164.945 102.145 ;
      RECT 167.135 98.915 167.345 102.145 ;
      RECT 170.975 114.035 171.185 115.165 ;
      RECT 175.295 114.875 175.505 115.590 ;
      RECT 166.655 110.675 166.865 116.005 ;
      RECT 167.140 110.675 169.740 117.265 ;
      RECT 175.300 114.035 176.940 117.265 ;
      RECT 167.615 115.295 167.825 117.685 ;
      RECT 180.095 117.390 180.305 118.105 ;
      RECT 166.655 117.810 166.865 118.525 ;
      RECT 172.895 117.810 173.105 118.525 ;
      RECT 175.300 95.135 175.985 102.145 ;
      RECT 168.100 95.975 169.260 98.365 ;
      RECT 180.580 107.735 181.740 118.525 ;
      RECT 163.775 117.815 163.985 118.535 ;
      RECT 163.295 83.790 163.505 84.505 ;
      RECT 173.375 82.535 173.585 84.085 ;
      RECT 165.215 83.790 165.425 84.505 ;
      RECT 177.215 83.785 177.425 84.505 ;
      RECT 167.620 84.215 170.700 84.925 ;
      RECT 175.295 83.795 175.505 84.925 ;
      RECT 171.935 83.795 172.145 85.345 ;
      RECT 174.335 83.795 174.545 85.345 ;
      RECT 167.135 83.795 167.345 86.185 ;
      RECT 177.695 83.795 178.380 86.605 ;
      RECT 163.775 83.730 163.985 87.025 ;
      RECT 166.175 82.530 166.385 83.245 ;
      RECT 179.135 82.530 179.345 83.245 ;
      RECT 181.055 86.315 181.265 87.035 ;
      RECT 171.455 85.055 171.665 87.445 ;
      RECT 167.135 86.735 167.345 87.450 ;
      RECT 168.095 87.150 168.305 87.865 ;
      RECT 169.055 87.570 169.265 88.285 ;
      RECT 172.895 83.795 173.105 88.285 ;
      RECT 163.295 85.475 163.985 88.290 ;
      RECT 170.975 87.995 171.185 90.385 ;
      RECT 180.095 84.215 180.305 91.225 ;
      RECT 177.695 82.535 177.905 83.665 ;
      RECT 167.615 90.930 167.825 91.645 ;
      RECT 167.615 83.730 168.265 84.085 ;
      RECT 181.055 91.355 181.265 94.585 ;
      RECT 186.000 38.900 186.400 64.020 ;
      RECT 203.550 65.240 206.070 69.550 ;
      RECT 175.400 37.200 175.800 69.600 ;
      RECT 184.400 37.100 184.800 61.600 ;
      RECT 188.900 42.830 189.300 62.400 ;
      RECT 202.700 42.010 203.100 62.400 ;
      RECT 216.500 41.190 216.900 62.400 ;
      RECT 185.200 39.100 185.600 60.000 ;
      RECT 230.300 43.650 230.700 62.400 ;
      RECT 204.390 58.450 205.290 58.830 ;
      RECT 210.890 58.450 211.790 58.830 ;
      RECT 223.330 53.600 223.730 56.100 ;
      RECT 233.800 53.600 234.200 56.100 ;
      RECT 229.400 52.500 229.800 60.800 ;
      RECT 233.110 58.430 233.510 60.800 ;
      RECT 237.130 53.600 237.530 56.100 ;
      RECT 243.200 52.500 243.600 60.800 ;
      RECT 218.190 58.450 219.090 58.830 ;
      RECT 224.690 58.450 225.590 58.830 ;
      RECT 231.990 58.450 232.890 58.830 ;
      RECT 238.490 58.450 239.390 58.830 ;
      RECT 209.550 61.200 212.670 66.520 ;
      RECT 223.350 61.200 226.470 66.520 ;
      RECT 237.150 61.200 240.270 66.520 ;
      RECT 205.510 58.430 205.910 60.800 ;
      RECT 217.350 65.240 219.870 69.550 ;
      RECT 231.150 65.240 233.670 69.550 ;
      RECT 215.600 52.500 216.000 60.800 ;
      RECT 206.290 60.400 206.690 66.090 ;
      RECT 212.890 59.600 213.290 66.090 ;
      RECT 220.090 60.400 220.490 66.090 ;
      RECT 226.690 59.600 227.090 66.090 ;
      RECT 233.890 60.400 234.290 66.090 ;
      RECT 240.490 59.600 240.890 66.090 ;
      RECT 209.530 53.600 209.930 56.100 ;
      RECT 210.270 57.960 211.790 61.600 ;
      RECT 225.810 58.430 226.210 64.010 ;
      RECT 239.610 58.430 240.010 64.010 ;
      RECT 203.770 54.650 205.290 59.240 ;
      RECT 217.570 54.650 219.090 59.240 ;
      RECT 231.370 54.650 232.890 59.240 ;
      RECT 208.400 58.450 208.800 62.400 ;
      RECT 214.400 58.450 214.800 62.400 ;
      RECT 224.070 57.960 225.590 61.600 ;
      RECT 219.310 58.430 219.710 60.800 ;
      RECT 220.000 53.600 220.400 56.100 ;
      RECT 222.200 58.450 222.600 62.400 ;
      RECT 228.200 58.450 228.600 62.400 ;
      RECT 212.010 58.430 212.410 64.010 ;
      RECT 237.870 57.960 239.390 61.600 ;
      RECT 236.000 58.450 236.400 62.400 ;
      RECT 242.000 58.450 242.400 62.400 ;
      RECT 217.970 65.730 219.870 66.110 ;
      RECT 221.120 62.000 221.520 66.110 ;
      RECT 224.570 65.730 226.470 66.110 ;
      RECT 227.350 62.000 227.750 66.110 ;
      RECT 206.200 53.600 206.600 56.100 ;
      RECT 231.770 65.730 233.670 66.110 ;
      RECT 234.920 62.000 235.320 66.110 ;
      RECT 204.170 65.730 206.070 66.110 ;
      RECT 207.320 62.000 207.720 66.110 ;
      RECT 210.770 65.730 212.670 66.110 ;
      RECT 213.550 62.000 213.950 66.110 ;
      RECT 238.370 65.730 240.270 66.110 ;
      RECT 241.150 62.000 241.550 66.110 ;
      RECT 196.470 57.960 197.990 61.600 ;
      RECT 189.750 65.240 192.270 69.550 ;
      RECT 192.400 53.600 192.800 56.100 ;
      RECT 195.730 53.600 196.130 56.100 ;
      RECT 195.750 61.200 198.870 66.520 ;
      RECT 194.600 58.450 195.000 62.400 ;
      RECT 186.800 51.500 187.200 54.000 ;
      RECT 190.370 65.730 192.270 66.110 ;
      RECT 200.600 58.450 201.000 62.400 ;
      RECT 193.520 62.000 193.920 66.110 ;
      RECT 196.970 65.730 198.870 66.110 ;
      RECT 199.750 62.000 200.150 66.110 ;
      RECT 189.970 54.650 191.490 59.240 ;
      RECT 190.590 58.450 191.490 58.830 ;
      RECT 191.710 58.430 192.110 60.800 ;
      RECT 197.090 58.450 197.990 58.830 ;
      RECT 192.490 60.400 192.890 66.090 ;
      RECT 199.090 59.600 199.490 66.090 ;
      RECT 198.210 58.430 198.610 64.010 ;
      RECT 173.190 27.600 173.590 34.090 ;
      RECT 171.070 33.730 172.970 34.110 ;
      RECT 174.700 26.450 175.100 30.400 ;
      RECT 173.850 30.000 174.250 34.110 ;
      RECT 170.570 25.960 172.090 29.600 ;
      RECT 169.850 29.200 172.970 34.520 ;
      RECT 172.310 26.430 172.710 31.200 ;
      RECT 178.200 27.600 178.600 39.500 ;
      RECT 176.600 30.800 177.000 40.400 ;
      RECT 171.190 26.450 172.090 26.830 ;
      RECT 223.230 26.430 225.130 26.730 ;
      RECT 221.930 26.380 222.330 30.400 ;
      RECT 225.490 25.220 225.890 30.400 ;
      RECT 228.930 26.430 230.830 26.730 ;
      RECT 233.510 23.500 233.910 27.020 ;
      RECT 219.250 30.000 219.950 35.705 ;
      RECT 234.810 26.160 237.330 32.000 ;
      RECT 228.930 27.000 230.830 30.400 ;
      RECT 231.190 25.220 231.590 30.400 ;
      RECT 240.410 26.160 241.930 32.000 ;
      RECT 227.630 26.380 228.030 28.800 ;
      RECT 234.190 26.630 234.590 28.800 ;
      RECT 243.710 26.630 244.110 28.800 ;
      RECT 239.790 26.640 240.190 28.800 ;
      RECT 240.410 26.680 241.310 26.980 ;
      RECT 239.110 26.630 239.510 29.600 ;
      RECT 223.230 27.000 225.130 32.800 ;
      RECT 234.810 26.670 236.710 26.970 ;
      RECT 222.610 26.650 223.010 28.800 ;
      RECT 228.310 26.650 228.710 28.000 ;
      RECT 284.600 52.500 285.000 60.800 ;
      RECT 257.900 45.290 258.300 62.400 ;
      RECT 271.700 46.110 272.100 62.400 ;
      RECT 318.810 42.430 319.210 49.250 ;
      RECT 323.810 42.430 324.210 49.250 ;
      RECT 316.070 41.960 318.590 51.900 ;
      RECT 321.070 41.960 323.590 51.900 ;
      RECT 319.700 42.420 320.100 55.000 ;
      RECT 324.700 42.420 325.100 55.000 ;
      RECT 306.150 61.200 309.270 66.520 ;
      RECT 287.190 58.450 288.090 58.830 ;
      RECT 289.090 60.400 289.490 66.090 ;
      RECT 295.690 59.600 296.090 66.090 ;
      RECT 302.890 60.400 303.290 66.090 ;
      RECT 286.970 65.730 288.870 66.110 ;
      RECT 309.490 59.600 309.890 66.090 ;
      RECT 290.120 62.000 290.520 66.110 ;
      RECT 293.690 58.450 294.590 58.830 ;
      RECT 300.990 58.450 301.890 58.830 ;
      RECT 285.500 46.930 285.900 62.400 ;
      RECT 291.200 58.450 291.600 62.400 ;
      RECT 293.570 65.730 295.470 66.110 ;
      RECT 296.350 62.000 296.750 66.110 ;
      RECT 300.770 65.730 302.670 66.110 ;
      RECT 297.200 58.450 297.600 62.400 ;
      RECT 299.300 47.750 299.700 62.400 ;
      RECT 305.000 58.450 305.400 62.400 ;
      RECT 311.000 58.450 311.400 62.400 ;
      RECT 307.490 58.450 308.390 58.830 ;
      RECT 286.350 65.240 288.870 69.550 ;
      RECT 286.570 54.650 288.090 59.240 ;
      RECT 300.370 54.650 301.890 59.240 ;
      RECT 292.350 61.200 295.470 66.520 ;
      RECT 300.150 65.240 302.670 69.550 ;
      RECT 303.920 62.000 304.320 66.110 ;
      RECT 311.800 51.500 312.200 54.000 ;
      RECT 298.400 60.400 298.800 69.600 ;
      RECT 307.370 65.730 309.270 66.110 ;
      RECT 289.000 53.600 289.400 56.100 ;
      RECT 292.330 53.600 292.730 56.100 ;
      RECT 302.800 53.600 303.200 56.100 ;
      RECT 288.310 58.430 288.710 60.800 ;
      RECT 294.810 58.430 295.210 64.010 ;
      RECT 302.110 58.430 302.510 60.800 ;
      RECT 308.610 58.430 309.010 64.010 ;
      RECT 310.150 62.000 310.550 66.110 ;
      RECT 306.130 53.600 306.530 56.100 ;
      RECT 293.070 57.960 294.590 61.600 ;
      RECT 306.870 57.960 308.390 61.600 ;
      RECT 282.550 62.000 282.950 66.110 ;
      RECT 279.890 58.450 280.790 58.830 ;
      RECT 247.690 60.400 248.090 66.090 ;
      RECT 244.950 65.240 247.470 69.550 ;
      RECT 277.400 58.450 277.800 62.400 ;
      RECT 258.750 65.240 261.270 69.550 ;
      RECT 247.600 53.600 248.000 56.100 ;
      RECT 250.930 53.600 251.330 56.100 ;
      RECT 245.170 54.650 246.690 59.240 ;
      RECT 258.970 54.650 260.490 59.240 ;
      RECT 272.770 54.650 274.290 59.240 ;
      RECT 272.550 65.240 275.070 69.550 ;
      RECT 254.290 59.600 254.690 66.090 ;
      RECT 261.490 60.400 261.890 66.090 ;
      RECT 268.090 59.600 268.490 66.090 ;
      RECT 261.400 53.600 261.800 56.100 ;
      RECT 275.290 60.400 275.690 66.090 ;
      RECT 281.890 59.600 282.290 66.090 ;
      RECT 276.320 62.000 276.720 66.110 ;
      RECT 249.800 51.500 250.200 54.000 ;
      RECT 283.400 58.450 283.800 62.400 ;
      RECT 264.730 53.600 265.130 56.100 ;
      RECT 275.200 53.600 275.600 56.100 ;
      RECT 279.770 65.730 281.670 66.110 ;
      RECT 260.710 58.430 261.110 60.800 ;
      RECT 278.530 53.600 278.930 56.100 ;
      RECT 250.950 61.200 254.070 66.520 ;
      RECT 270.800 52.500 271.200 60.800 ;
      RECT 274.510 58.430 274.910 60.800 ;
      RECT 253.410 58.430 253.810 64.010 ;
      RECT 267.210 58.430 267.610 64.010 ;
      RECT 264.750 61.200 267.870 66.520 ;
      RECT 281.010 58.430 281.410 64.010 ;
      RECT 278.550 61.200 281.670 66.520 ;
      RECT 266.090 58.450 266.990 58.830 ;
      RECT 249.800 58.450 250.200 62.400 ;
      RECT 255.800 58.450 256.200 62.400 ;
      RECT 273.390 58.450 274.290 58.830 ;
      RECT 245.570 65.730 247.470 66.110 ;
      RECT 248.720 62.000 249.120 66.110 ;
      RECT 252.170 65.730 254.070 66.110 ;
      RECT 254.950 62.000 255.350 66.110 ;
      RECT 259.370 65.730 261.270 66.110 ;
      RECT 262.520 62.000 262.920 66.110 ;
      RECT 265.970 65.730 267.870 66.110 ;
      RECT 251.670 57.960 253.190 61.600 ;
      RECT 265.470 57.960 266.990 61.600 ;
      RECT 279.270 57.960 280.790 61.600 ;
      RECT 263.600 58.450 264.000 62.400 ;
      RECT 269.600 58.450 270.000 62.400 ;
      RECT 246.910 58.430 247.310 60.800 ;
      RECT 257.000 52.500 257.400 60.800 ;
      RECT 268.750 62.000 269.150 66.110 ;
      RECT 273.170 65.730 275.070 66.110 ;
      RECT 245.790 58.450 246.690 58.830 ;
      RECT 252.290 58.450 253.190 58.830 ;
      RECT 259.590 58.450 260.490 58.830 ;
      RECT 258.100 23.500 258.500 37.500 ;
      RECT 257.300 28.400 257.700 39.300 ;
      RECT 248.990 26.640 249.390 28.000 ;
      RECT 248.310 26.630 248.710 29.600 ;
      RECT 244.390 26.640 244.790 32.800 ;
      RECT 245.010 26.680 245.910 26.980 ;
      RECT 249.610 26.680 250.510 26.980 ;
      RECT 249.610 24.940 251.130 27.460 ;
      RECT 253.590 26.640 253.990 28.000 ;
      RECT 252.910 26.630 253.310 31.200 ;
      RECT 254.210 24.940 255.730 27.460 ;
      RECT 245.010 26.160 246.530 31.200 ;
      RECT 254.210 26.680 255.110 26.980 ;
      RECT 316.690 42.480 318.590 42.760 ;
      RECT 316.070 39.960 316.470 40.360 ;
      RECT 321.690 42.480 323.590 42.760 ;
      RECT 321.070 39.960 321.470 40.360 ;
    LAYER Metal3 ;
      RECT 159.360 0.000 191.200 0.400 ;
      RECT 160.320 1.300 203.300 1.700 ;
      RECT 161.280 2.600 216.000 3.000 ;
      RECT 162.240 3.900 229.800 4.300 ;
      RECT 163.200 5.200 243.600 5.600 ;
      RECT 118.400 10.400 167.440 10.800 ;
      RECT 104.600 11.700 168.400 12.100 ;
      RECT 90.800 13.000 169.360 13.400 ;
      RECT 77.000 14.300 170.320 14.700 ;
      RECT 63.200 15.600 171.280 16.000 ;
      RECT 49.400 16.900 172.240 17.300 ;
      RECT 35.600 18.200 173.200 18.600 ;
      RECT 21.800 19.500 174.160 19.900 ;
      RECT 55.300 27.600 257.200 28.000 ;
      RECT 148.000 29.200 176.000 29.600 ;
      RECT 162.000 30.000 175.200 30.400 ;
      RECT 134.200 30.800 177.000 31.200 ;
      RECT 134.000 39.100 185.600 39.500 ;
      RECT 133.200 40.000 177.000 40.400 ;
      RECT 133.000 48.850 327.000 49.250 ;
      RECT 163.000 49.900 314.500 50.300 ;
      RECT 5.400 51.500 327.000 51.900 ;
      RECT 163.790 82.995 164.505 83.205 ;
      RECT 159.415 83.420 180.825 83.620 ;
      RECT 158.935 83.840 176.985 84.460 ;
      RECT 163.255 84.260 165.465 84.460 ;
      RECT 161.335 85.100 178.905 85.720 ;
      RECT 158.935 85.940 167.385 86.140 ;
      RECT 141.175 86.360 181.305 86.560 ;
      RECT 163.735 87.200 171.705 87.820 ;
      RECT 160.855 88.880 172.665 89.080 ;
      RECT 149.335 89.295 164.505 89.920 ;
      RECT 156.535 90.135 171.225 90.345 ;
      RECT 144.535 90.980 180.345 91.180 ;
      RECT 159.415 91.400 181.305 91.600 ;
      RECT 151.255 92.660 164.505 93.280 ;
      RECT 149.335 96.860 179.385 97.060 ;
      RECT 160.375 98.120 164.985 98.320 ;
      RECT 157.495 98.960 164.505 99.160 ;
      RECT 162.775 98.960 181.305 99.580 ;
      RECT 146.455 101.900 164.985 102.100 ;
      RECT 143.575 101.060 166.425 104.620 ;
      RECT 158.455 105.675 164.505 105.885 ;
      RECT 162.775 106.520 166.905 106.720 ;
      RECT 141.175 106.940 165.465 107.140 ;
      RECT 152.215 110.720 166.425 111.340 ;
      RECT 144.535 111.980 171.225 112.180 ;
      RECT 153.655 113.240 167.385 113.865 ;
      RECT 156.535 114.080 166.425 114.280 ;
      RECT 157.495 114.500 176.025 114.700 ;
      RECT 147.415 115.760 166.905 116.380 ;
      RECT 159.895 117.015 177.945 117.225 ;
      RECT 158.455 117.440 167.865 117.640 ;
      RECT 159.415 117.860 169.785 118.060 ;
      RECT 159.415 118.275 166.905 118.485 ;
      RECT 163.255 119.120 165.945 119.320 ;
      RECT 158.455 118.695 165.945 120.160 ;
      RECT 161.335 119.540 166.425 121.000 ;
      RECT 161.815 121.640 166.905 121.840 ;
      RECT 162.775 122.060 168.345 122.260 ;
      RECT 146.935 122.480 180.345 122.680 ;
      RECT 158.935 124.995 174.585 125.205 ;
      RECT 159.895 128.780 167.385 129.400 ;
      RECT 162.775 128.780 170.265 129.400 ;
      RECT 158.935 129.200 177.465 130.660 ;
      RECT 160.855 130.880 178.905 131.080 ;
      RECT 162.775 139.700 167.385 139.900 ;
      RECT 162.295 140.540 168.825 140.740 ;
      RECT 161.815 140.960 169.305 141.160 ;
      RECT 158.455 141.375 171.705 141.585 ;
      RECT 163.735 141.795 166.425 142.005 ;
      RECT 161.335 141.800 169.305 142.420 ;
      RECT 163.735 142.635 165.945 142.845 ;
      RECT 160.375 143.060 171.225 143.260 ;
      RECT 149.335 143.055 168.345 143.680 ;
      RECT 157.015 143.900 166.905 144.100 ;
      RECT 152.695 145.160 170.745 145.360 ;
      RECT 159.415 147.680 178.425 147.880 ;
      RECT 157.975 148.515 170.745 148.725 ;
      RECT 162.830 151.035 164.985 151.245 ;
      RECT 163.735 151.880 167.385 152.080 ;
      RECT 160.855 152.300 166.905 152.500 ;
      RECT 158.935 151.455 179.385 152.920 ;
      RECT 159.895 154.400 166.905 154.600 ;
      RECT 160.375 155.240 165.465 155.440 ;
      RECT 159.415 156.075 169.305 156.700 ;
      RECT 160.855 158.600 166.905 158.800 ;
      RECT 157.015 159.015 168.345 160.060 ;
      RECT 163.735 159.435 164.985 160.480 ;
      RECT 158.935 161.540 167.385 161.740 ;
      RECT 145.495 162.380 170.745 163.420 ;
      RECT 162.295 163.640 167.385 163.840 ;
      RECT 114.800 71.700 116.400 177.900 ;
      RECT 117.000 71.700 118.600 177.900 ;
      RECT 119.200 71.700 120.800 177.900 ;
      RECT 121.400 71.700 123.000 177.900 ;
      RECT 123.600 71.700 125.200 177.900 ;
      RECT 125.800 71.700 127.400 177.900 ;
      RECT 127.800 71.700 129.800 177.900 ;
      RECT 130.000 71.700 132.000 177.900 ;
      RECT 132.200 71.700 134.200 177.900 ;
      RECT 189.200 71.500 192.000 177.900 ;
      RECT 188.100 70.600 194.200 177.900 ;
      RECT 187.200 69.700 196.400 177.900 ;
      RECT 196.800 71.700 198.400 177.900 ;
      RECT 199.000 71.700 200.600 177.900 ;
      RECT 201.200 71.700 202.800 177.900 ;
      RECT 203.400 71.700 205.000 177.900 ;
      RECT 205.600 71.700 207.200 177.900 ;
      RECT 207.800 71.700 209.400 177.900 ;
      RECT 129.700 183.900 168.090 184.300 ;
      RECT 156.110 184.700 265.000 185.100 ;
      RECT 131.800 197.000 191.800 197.400 ;
      RECT 155.900 198.900 168.300 199.300 ;
      RECT 214.605 128.400 214.895 128.600 ;
      RECT 168.055 110.300 169.305 110.920 ;
      RECT 173.815 117.860 180.345 118.060 ;
      RECT 175.255 129.620 181.305 129.820 ;
      RECT 167.575 130.040 179.865 130.240 ;
      RECT 172.855 118.280 175.545 118.480 ;
      RECT 166.670 130.455 167.385 130.665 ;
      RECT 165.175 111.140 170.745 111.340 ;
      RECT 166.615 136.340 174.105 136.540 ;
      RECT 170.935 118.700 173.625 118.900 ;
      RECT 168.055 139.700 181.305 140.320 ;
      RECT 169.495 140.120 176.025 140.320 ;
      RECT 171.415 114.075 173.625 114.285 ;
      RECT 169.495 119.115 175.545 119.325 ;
      RECT 174.295 141.380 178.905 141.580 ;
      RECT 169.015 119.540 170.745 119.740 ;
      RECT 173.335 141.800 176.025 142.000 ;
      RECT 174.830 114.075 175.545 114.285 ;
      RECT 213.305 120.400 213.595 120.600 ;
      RECT 168.055 142.640 171.705 142.840 ;
      RECT 219.305 120.400 219.595 120.600 ;
      RECT 225.305 120.400 225.595 120.600 ;
      RECT 231.305 120.400 231.595 120.600 ;
      RECT 237.305 120.400 237.595 120.600 ;
      RECT 166.135 144.320 174.585 144.520 ;
      RECT 167.095 144.740 173.625 144.940 ;
      RECT 243.305 120.400 243.595 120.600 ;
      RECT 164.695 145.575 166.425 145.785 ;
      RECT 166.615 146.000 169.785 146.200 ;
      RECT 249.305 120.400 249.595 120.600 ;
      RECT 255.305 120.400 255.595 120.600 ;
      RECT 166.135 149.360 169.305 149.560 ;
      RECT 262.605 120.400 262.895 120.600 ;
      RECT 268.605 120.400 268.895 120.600 ;
      RECT 274.605 120.400 274.895 120.600 ;
      RECT 280.605 120.400 280.895 120.600 ;
      RECT 168.055 153.980 181.305 154.180 ;
      RECT 286.605 120.400 286.895 120.600 ;
      RECT 292.605 120.400 292.895 120.600 ;
      RECT 165.655 156.080 168.345 156.280 ;
      RECT 298.605 120.400 298.895 120.600 ;
      RECT 168.055 156.920 181.305 157.120 ;
      RECT 304.605 120.400 304.895 120.600 ;
      RECT 178.135 158.600 181.305 158.800 ;
      RECT 165.655 111.140 181.305 111.760 ;
      RECT 165.230 121.215 165.945 121.425 ;
      RECT 170.935 114.920 175.545 115.120 ;
      RECT 169.495 121.640 180.825 121.840 ;
      RECT 238.605 122.000 238.895 122.200 ;
      RECT 244.605 122.000 244.895 122.200 ;
      RECT 250.605 122.000 250.895 122.200 ;
      RECT 256.605 122.000 256.895 122.200 ;
      RECT 261.305 122.000 261.595 122.200 ;
      RECT 267.305 122.000 267.595 122.200 ;
      RECT 273.305 122.000 273.595 122.200 ;
      RECT 279.305 122.000 279.595 122.200 ;
      RECT 170.935 110.715 179.865 110.925 ;
      RECT 169.975 113.235 177.945 113.445 ;
      RECT 168.110 123.315 168.825 123.525 ;
      RECT 226.605 123.600 226.895 123.800 ;
      RECT 232.605 123.600 232.895 123.800 ;
      RECT 285.305 123.600 285.595 123.800 ;
      RECT 291.305 123.600 291.595 123.800 ;
      RECT 166.615 124.580 169.305 124.780 ;
      RECT 181.015 124.480 188.200 124.880 ;
      RECT 166.615 113.660 171.705 113.860 ;
      RECT 220.605 125.200 220.895 125.400 ;
      RECT 169.180 179.300 172.070 179.700 ;
      RECT 170.230 183.000 177.580 183.400 ;
      RECT 297.305 125.200 297.595 125.400 ;
      RECT 167.095 125.840 174.585 126.040 ;
      RECT 314.100 186.500 314.500 186.900 ;
      RECT 168.960 186.580 172.070 186.980 ;
      RECT 169.180 189.295 169.880 189.905 ;
      RECT 313.950 189.295 314.650 189.905 ;
      RECT 168.460 192.550 170.730 192.950 ;
      RECT 168.360 193.500 170.830 193.900 ;
      RECT 170.030 126.675 170.745 126.885 ;
      RECT 303.305 126.800 303.595 127.000 ;
      RECT 6.400 205.500 133.700 205.900 ;
      RECT 157.015 162.380 159.225 162.580 ;
      RECT 148.855 161.960 158.745 163.000 ;
      RECT 157.975 163.640 161.145 163.840 ;
      RECT 161.115 165.320 163.045 165.520 ;
      RECT 142.615 166.160 148.665 166.360 ;
      RECT 150.295 167.000 153.945 167.200 ;
      RECT 154.915 169.100 156.845 169.300 ;
      RECT 134.700 174.500 135.100 174.900 ;
      RECT 152.130 179.300 155.020 179.700 ;
      RECT 146.620 183.000 153.970 183.400 ;
      RECT 152.130 186.580 155.240 186.980 ;
      RECT 154.330 189.295 155.030 189.905 ;
      RECT 153.470 192.550 155.740 192.950 ;
      RECT 153.370 193.500 155.840 193.900 ;
      RECT 154.915 161.540 156.845 161.740 ;
      RECT 10.650 189.295 11.350 189.905 ;
      RECT 6.250 214.395 6.950 215.005 ;
      RECT 25.305 120.400 25.595 120.600 ;
      RECT 31.305 120.400 31.595 120.600 ;
      RECT 20.605 126.800 20.895 127.000 ;
      RECT 37.305 120.400 37.595 120.600 ;
      RECT 43.305 120.400 43.595 120.600 ;
      RECT 49.305 120.400 49.595 120.600 ;
      RECT 55.305 120.400 55.595 120.600 ;
      RECT 61.305 120.400 61.595 120.600 ;
      RECT 68.605 120.400 68.895 120.600 ;
      RECT 32.605 123.600 32.895 123.800 ;
      RECT 38.605 123.600 38.895 123.800 ;
      RECT 74.605 120.400 74.895 120.600 ;
      RECT 80.605 120.400 80.895 120.600 ;
      RECT 44.605 122.000 44.895 122.200 ;
      RECT 50.605 122.000 50.895 122.200 ;
      RECT 56.605 122.000 56.895 122.200 ;
      RECT 26.605 125.200 26.895 125.400 ;
      RECT 62.605 122.000 62.895 122.200 ;
      RECT 67.305 122.000 67.595 122.200 ;
      RECT 19.305 120.400 19.595 120.600 ;
      RECT 73.305 122.000 73.595 122.200 ;
      RECT 79.305 122.000 79.595 122.200 ;
      RECT 147.895 134.240 151.520 134.440 ;
      RECT 142.615 140.120 145.305 140.320 ;
      RECT 151.255 140.120 160.665 140.320 ;
      RECT 144.055 140.960 148.185 141.160 ;
      RECT 151.735 141.375 156.825 141.585 ;
      RECT 147.415 141.800 148.665 142.000 ;
      RECT 161.115 142.640 163.045 142.840 ;
      RECT 146.935 143.480 158.265 143.680 ;
      RECT 162.830 144.315 163.545 144.525 ;
      RECT 159.415 145.575 164.025 145.785 ;
      RECT 154.915 146.420 156.845 146.620 ;
      RECT 158.935 147.255 160.185 147.465 ;
      RECT 144.535 147.680 158.745 147.880 ;
      RECT 144.055 148.520 145.785 148.720 ;
      RECT 163.255 149.355 164.025 149.565 ;
      RECT 161.115 150.200 163.045 150.400 ;
      RECT 160.855 150.620 164.025 151.240 ;
      RECT 144.535 153.140 149.145 153.340 ;
      RECT 154.915 153.980 156.845 154.180 ;
      RECT 152.215 154.820 156.345 155.020 ;
      RECT 161.815 154.820 163.545 155.020 ;
      RECT 147.895 156.080 155.865 156.280 ;
      RECT 151.320 156.495 153.465 156.705 ;
      RECT 159.415 156.920 162.585 157.120 ;
      RECT 154.615 156.920 164.025 157.540 ;
      RECT 147.415 157.760 160.185 157.960 ;
      RECT 161.115 157.760 163.045 157.960 ;
      RECT 149.335 159.020 154.905 159.220 ;
      RECT 156.535 159.440 159.705 159.640 ;
      RECT 160.375 159.440 163.545 159.640 ;
      RECT 151.735 159.860 157.785 160.060 ;
      RECT 134.700 160.600 160.665 161.000 ;
      RECT 145.495 139.700 152.985 139.900 ;
      RECT 161.115 135.080 163.045 135.280 ;
      RECT 136.100 136.240 142.425 136.640 ;
      RECT 153.655 136.760 156.345 136.960 ;
      RECT 157.495 136.760 163.065 136.960 ;
      RECT 148.855 137.600 151.065 137.800 ;
      RECT 142.615 138.020 153.465 138.220 ;
      RECT 154.915 138.860 156.845 139.060 ;
      RECT 109.305 128.400 109.595 128.600 ;
      RECT 98.605 120.400 98.895 120.600 ;
      RECT 92.605 120.400 92.895 120.600 ;
      RECT 104.605 120.400 104.895 120.600 ;
      RECT 103.305 125.200 103.595 125.400 ;
      RECT 85.305 122.000 85.595 122.200 ;
      RECT 110.605 120.400 110.895 120.600 ;
      RECT 86.605 120.400 86.895 120.600 ;
      RECT 91.305 123.600 91.595 123.800 ;
      RECT 97.305 123.600 97.595 123.800 ;
      RECT 155.575 107.780 164.025 108.400 ;
      RECT 149.335 114.080 152.505 115.960 ;
      RECT 152.215 126.260 154.425 126.460 ;
      RECT 156.535 128.775 161.145 128.985 ;
      RECT 157.015 109.455 163.545 109.665 ;
      RECT 158.935 107.780 161.145 107.980 ;
      RECT 142.615 126.680 146.265 126.880 ;
      RECT 154.915 116.180 156.845 116.380 ;
      RECT 160.855 116.600 162.585 116.800 ;
      RECT 154.135 114.075 155.385 114.285 ;
      RECT 154.615 125.840 157.305 126.040 ;
      RECT 144.590 125.835 145.305 126.045 ;
      RECT 154.915 108.620 156.845 108.820 ;
      RECT 147.950 109.455 148.665 109.665 ;
      RECT 150.295 120.795 153.465 121.005 ;
      RECT 148.375 114.080 151.065 114.280 ;
      RECT 145.015 121.215 161.145 121.425 ;
      RECT 136.100 111.880 142.905 112.280 ;
      RECT 158.990 116.595 159.705 116.805 ;
      RECT 159.950 125.835 160.665 126.045 ;
      RECT 148.375 117.435 151.065 117.645 ;
      RECT 161.115 127.520 163.045 127.720 ;
      RECT 148.855 128.360 154.905 128.560 ;
      RECT 152.215 117.020 159.225 118.060 ;
      RECT 149.815 111.560 155.865 111.760 ;
      RECT 161.115 112.400 163.045 112.600 ;
      RECT 154.915 131.300 156.845 131.500 ;
      RECT 149.815 132.140 160.185 132.340 ;
      RECT 150.775 132.560 158.745 132.760 ;
      RECT 159.415 132.980 161.145 133.180 ;
      RECT 156.535 132.975 157.880 133.185 ;
      RECT 144.110 112.815 144.825 113.025 ;
      RECT 143.575 113.240 145.305 113.440 ;
      RECT 149.335 118.275 155.865 118.485 ;
      RECT 158.455 113.240 161.145 113.440 ;
      RECT 144.055 118.700 153.945 118.900 ;
      RECT 150.295 122.055 154.425 122.265 ;
      RECT 142.615 122.480 145.305 122.680 ;
      RECT 147.415 113.235 149.145 113.445 ;
      RECT 146.455 123.320 148.665 123.520 ;
      RECT 154.615 118.695 159.705 118.905 ;
      RECT 148.375 133.400 155.385 133.600 ;
      RECT 157.975 133.400 162.585 133.600 ;
      RECT 143.575 114.495 152.025 114.705 ;
      RECT 157.975 111.560 160.185 111.760 ;
      RECT 160.375 118.695 161.100 119.320 ;
      RECT 150.295 113.235 151.065 113.445 ;
      RECT 151.735 113.235 153.465 113.445 ;
      RECT 156.055 119.540 160.185 119.740 ;
      RECT 153.175 133.815 153.945 134.025 ;
      RECT 154.915 123.740 156.845 123.940 ;
      RECT 155.575 133.815 157.305 134.025 ;
      RECT 145.495 124.580 152.505 124.780 ;
      RECT 142.615 110.295 147.705 110.505 ;
      RECT 148.855 110.720 158.265 110.920 ;
      RECT 148.855 125.000 153.465 125.200 ;
      RECT 151.200 121.640 153.465 121.840 ;
      RECT 161.115 119.960 163.045 120.160 ;
      RECT 147.470 117.015 148.185 117.225 ;
      RECT 149.870 109.875 150.585 110.085 ;
      RECT 156.055 121.635 157.785 121.845 ;
      RECT 150.295 113.655 152.025 113.865 ;
      RECT 149.335 114.915 150.105 115.125 ;
      RECT 142.135 119.955 155.385 120.165 ;
      RECT 158.510 121.635 159.225 121.845 ;
      RECT 157.015 128.360 159.705 128.560 ;
      RECT 143.095 125.420 156.825 125.620 ;
      RECT 146.935 125.840 151.545 126.040 ;
      RECT 159.895 114.915 163.065 115.125 ;
      RECT 156.055 115.335 157.305 115.545 ;
      RECT 54.300 28.400 89.800 28.800 ;
      RECT 81.920 26.380 84.370 26.780 ;
      RECT 63.100 29.095 93.250 29.705 ;
      RECT 80.400 30.000 93.100 30.400 ;
      RECT 53.500 37.100 132.100 37.500 ;
      RECT 10.800 38.000 149.600 38.400 ;
      RECT 54.300 38.900 132.900 39.300 ;
      RECT 8.900 39.700 115.800 40.100 ;
      RECT 22.700 41.000 118.000 41.400 ;
      RECT 36.500 42.300 120.200 42.700 ;
      RECT 50.300 43.600 122.400 44.000 ;
      RECT 64.100 44.900 124.600 45.300 ;
      RECT 77.900 46.200 126.800 46.600 ;
      RECT 79.840 58.450 84.000 58.830 ;
      RECT 7.900 59.600 134.400 60.000 ;
      RECT 76.900 60.400 90.100 60.800 ;
      RECT 7.900 61.200 132.100 61.600 ;
      RECT 76.900 62.000 90.100 62.400 ;
      RECT 7.900 62.800 136.600 63.200 ;
      RECT 7.900 63.620 132.900 64.020 ;
      RECT 80.120 65.730 82.920 66.110 ;
      RECT 152.695 90.135 153.465 90.345 ;
      RECT 142.615 90.560 153.465 90.760 ;
      RECT 144.535 91.815 146.745 92.025 ;
      RECT 153.175 91.815 156.825 92.025 ;
      RECT 145.015 92.660 148.665 92.860 ;
      RECT 154.915 93.500 156.845 93.700 ;
      RECT 152.215 93.920 154.425 94.120 ;
      RECT 144.535 95.175 153.465 95.385 ;
      RECT 148.855 95.595 161.145 95.805 ;
      RECT 149.390 96.015 150.105 96.225 ;
      RECT 153.230 96.015 153.945 96.225 ;
      RECT 143.575 96.440 152.985 96.640 ;
      RECT 161.115 97.280 163.045 97.480 ;
      RECT 146.935 97.275 148.185 97.485 ;
      RECT 142.615 98.120 145.305 98.320 ;
      RECT 147.895 98.120 149.145 99.160 ;
      RECT 152.750 98.955 153.465 99.165 ;
      RECT 142.670 98.955 152.985 99.580 ;
      RECT 149.335 99.800 152.505 100.000 ;
      RECT 157.495 99.800 158.745 100.000 ;
      RECT 146.030 99.795 148.665 100.005 ;
      RECT 144.055 100.220 145.785 100.420 ;
      RECT 154.915 101.060 156.845 101.260 ;
      RECT 144.535 102.740 163.065 102.940 ;
      RECT 141.175 103.160 143.385 103.360 ;
      RECT 145.495 103.160 147.225 103.360 ;
      RECT 149.815 103.160 163.545 103.780 ;
      RECT 153.175 103.575 160.185 103.785 ;
      RECT 143.575 103.995 152.985 104.205 ;
      RECT 159.895 85.520 163.545 85.720 ;
      RECT 142.670 104.415 143.385 104.625 ;
      RECT 161.115 104.840 163.045 105.040 ;
      RECT 147.415 105.255 154.905 105.465 ;
      RECT 148.855 105.675 149.625 105.885 ;
      RECT 156.590 105.675 157.305 105.885 ;
      RECT 152.270 86.775 152.985 86.985 ;
      RECT 142.615 106.520 145.305 106.720 ;
      RECT 150.775 106.520 155.865 106.720 ;
      RECT 151.255 87.200 154.425 87.400 ;
      RECT 162.350 87.195 163.065 87.405 ;
      RECT 158.935 87.620 160.665 87.820 ;
      RECT 154.915 85.940 156.845 86.140 ;
      RECT 157.015 86.780 164.025 87.825 ;
      RECT 135.400 87.520 142.425 87.920 ;
      RECT 145.495 88.040 153.945 88.240 ;
      RECT 147.415 87.620 155.865 88.240 ;
      RECT 86.340 58.450 90.000 58.830 ;
      RECT 93.640 58.450 97.800 58.830 ;
      RECT 100.140 58.450 103.800 58.830 ;
      RECT 107.440 58.450 111.600 58.830 ;
      RECT 113.940 58.450 117.600 58.830 ;
      RECT 121.240 58.450 125.400 58.830 ;
      RECT 127.740 58.450 131.400 58.830 ;
      RECT 145.975 88.460 154.905 88.660 ;
      RECT 162.830 88.455 163.545 88.665 ;
      RECT 90.700 60.400 103.900 60.800 ;
      RECT 104.500 60.400 117.700 60.800 ;
      RECT 118.300 60.400 131.500 60.800 ;
      RECT 144.535 88.880 156.345 89.080 ;
      RECT 157.975 84.260 158.265 86.140 ;
      RECT 90.700 62.000 103.900 62.400 ;
      RECT 104.500 62.000 117.700 62.400 ;
      RECT 118.300 62.000 131.500 62.400 ;
      RECT 142.190 88.875 142.905 89.085 ;
      RECT 148.855 89.295 152.025 89.505 ;
      RECT 161.115 89.720 163.045 89.920 ;
      RECT 86.720 65.730 89.150 66.110 ;
      RECT 93.920 65.730 96.720 66.110 ;
      RECT 100.520 65.730 102.950 66.110 ;
      RECT 107.720 65.730 110.520 66.110 ;
      RECT 114.320 65.730 116.750 66.110 ;
      RECT 121.520 65.730 124.320 66.110 ;
      RECT 128.120 65.730 130.550 66.110 ;
      RECT 159.415 77.955 160.665 78.165 ;
      RECT 148.375 79.635 151.065 79.845 ;
      RECT 158.030 79.635 158.745 79.845 ;
      RECT 147.895 80.055 163.545 80.265 ;
      RECT 154.615 80.900 158.745 81.100 ;
      RECT 148.430 81.735 149.145 81.945 ;
      RECT 156.535 81.735 157.305 81.945 ;
      RECT 157.975 82.160 160.185 82.360 ;
      RECT 161.115 82.160 163.045 82.360 ;
      RECT 151.310 82.575 152.025 82.785 ;
      RECT 143.575 83.000 159.225 83.200 ;
      RECT 162.775 82.580 164.025 83.205 ;
      RECT 143.095 83.840 145.785 84.040 ;
      RECT 147.415 83.840 152.505 84.040 ;
      RECT 24.920 65.730 27.720 66.110 ;
      RECT 31.520 65.730 33.950 66.110 ;
      RECT 38.720 65.730 41.520 66.110 ;
      RECT 45.320 65.730 47.750 66.110 ;
      RECT 52.520 65.730 55.320 66.110 ;
      RECT 59.120 65.730 61.550 66.110 ;
      RECT 66.320 65.730 69.120 66.110 ;
      RECT 72.920 65.730 75.350 66.110 ;
      RECT 21.700 60.400 34.900 60.800 ;
      RECT 35.500 60.400 48.700 60.800 ;
      RECT 49.300 60.400 62.500 60.800 ;
      RECT 63.100 60.400 76.300 60.800 ;
      RECT 72.540 58.450 76.200 58.830 ;
      RECT 10.840 58.450 15.000 58.830 ;
      RECT 17.340 58.450 21.000 58.830 ;
      RECT 24.640 58.450 28.800 58.830 ;
      RECT 1.250 69.095 1.950 69.705 ;
      RECT 7.700 69.095 8.700 69.705 ;
      RECT 10.800 71.000 11.200 71.400 ;
      RECT 31.140 58.450 34.800 58.830 ;
      RECT 7.900 62.000 21.100 62.400 ;
      RECT 21.700 62.000 34.900 62.400 ;
      RECT 35.500 62.000 48.700 62.400 ;
      RECT 49.300 62.000 62.500 62.400 ;
      RECT 63.100 62.000 76.300 62.400 ;
      RECT 38.440 58.450 42.600 58.830 ;
      RECT 44.940 58.450 48.600 58.830 ;
      RECT 52.240 58.450 56.400 58.830 ;
      RECT 58.740 58.450 62.400 58.830 ;
      RECT 66.040 58.450 70.200 58.830 ;
      RECT 7.900 60.400 21.100 60.800 ;
      RECT 11.120 65.730 13.920 66.110 ;
      RECT 17.720 65.730 20.150 66.110 ;
      RECT 63.200 52.500 63.600 52.900 ;
      RECT 77.000 52.500 77.400 52.900 ;
      RECT 53.500 23.500 78.900 23.900 ;
      RECT 58.500 30.800 66.100 31.200 ;
      RECT 2.500 31.600 75.300 32.000 ;
      RECT 76.040 26.620 78.490 27.020 ;
      RECT 57.140 26.630 59.090 27.030 ;
      RECT 61.740 26.630 63.690 27.030 ;
      RECT 21.800 52.500 22.200 52.900 ;
      RECT 66.340 26.630 68.290 27.030 ;
      RECT 70.940 26.630 72.890 27.030 ;
      RECT 35.600 52.500 36.000 52.900 ;
      RECT 49.400 52.500 49.800 52.900 ;
      RECT 92.050 35.095 92.750 35.705 ;
      RECT 144.220 33.730 146.650 34.110 ;
      RECT 87.620 26.380 90.070 26.780 ;
      RECT 91.700 47.500 129.000 47.900 ;
      RECT 105.500 48.800 131.200 49.200 ;
      RECT 134.400 28.400 147.600 28.800 ;
      RECT 158.020 33.730 160.450 34.110 ;
      RECT 119.300 50.100 133.400 50.500 ;
      RECT 134.400 29.200 147.600 29.600 ;
      RECT 148.200 30.000 161.400 30.400 ;
      RECT 143.840 26.450 147.500 26.830 ;
      RECT 134.400 30.000 147.600 30.400 ;
      RECT 157.640 26.450 161.300 26.830 ;
      RECT 137.620 33.730 140.420 34.110 ;
      RECT 90.800 52.500 91.200 52.900 ;
      RECT 104.600 52.500 105.000 52.900 ;
      RECT 118.400 52.500 118.800 52.900 ;
      RECT 147.840 52.900 148.240 53.300 ;
      RECT 148.800 52.900 149.200 53.300 ;
      RECT 149.760 52.900 150.160 53.300 ;
      RECT 150.720 52.900 151.120 53.300 ;
      RECT 151.680 52.900 152.080 53.300 ;
      RECT 152.640 52.900 153.040 53.300 ;
      RECT 153.600 52.900 154.000 53.300 ;
      RECT 154.560 52.900 154.960 53.300 ;
      RECT 155.520 52.900 155.920 53.300 ;
      RECT 156.480 52.900 156.880 53.300 ;
      RECT 157.440 52.900 157.840 53.300 ;
      RECT 158.400 52.900 158.800 53.300 ;
      RECT 159.360 52.900 159.760 53.300 ;
      RECT 160.320 52.900 160.720 53.300 ;
      RECT 161.280 52.900 161.680 53.300 ;
      RECT 162.240 52.900 162.640 53.300 ;
      RECT 163.200 52.900 163.600 53.300 ;
      RECT 137.340 26.450 141.500 26.830 ;
      RECT 136.540 42.420 139.200 42.820 ;
      RECT 141.540 42.420 144.200 42.820 ;
      RECT 184.400 37.100 258.500 37.500 ;
      RECT 218.750 29.095 248.900 29.705 ;
      RECT 186.000 38.900 257.700 39.300 ;
      RECT 166.080 9.100 285.000 9.500 ;
      RECT 233.100 23.500 258.500 23.900 ;
      RECT 185.200 59.600 311.500 60.000 ;
      RECT 243.710 26.630 245.660 27.030 ;
      RECT 243.100 60.400 256.300 60.800 ;
      RECT 184.400 61.200 311.500 61.600 ;
      RECT 164.160 6.500 257.400 6.900 ;
      RECT 201.800 45.290 258.300 45.690 ;
      RECT 204.000 46.110 272.100 46.510 ;
      RECT 236.700 31.600 313.500 32.000 ;
      RECT 206.200 46.930 285.900 47.330 ;
      RECT 243.100 62.000 256.300 62.400 ;
      RECT 243.100 62.800 256.300 63.200 ;
      RECT 186.000 63.620 311.500 64.020 ;
      RECT 208.400 47.750 299.700 48.150 ;
      RECT 165.120 7.800 271.200 8.200 ;
      RECT 222.200 28.400 257.700 28.800 ;
      RECT 301.520 65.730 304.320 66.110 ;
      RECT 256.900 60.400 270.100 60.800 ;
      RECT 270.700 60.400 283.900 60.800 ;
      RECT 284.500 60.400 297.700 60.800 ;
      RECT 298.300 60.400 311.500 60.800 ;
      RECT 246.040 58.450 250.200 58.830 ;
      RECT 252.540 58.450 256.200 58.830 ;
      RECT 259.840 58.450 264.000 58.830 ;
      RECT 266.340 58.450 270.000 58.830 ;
      RECT 273.640 58.450 277.800 58.830 ;
      RECT 280.140 58.450 283.800 58.830 ;
      RECT 287.440 58.450 291.600 58.830 ;
      RECT 256.900 62.000 270.100 62.400 ;
      RECT 270.700 62.000 283.900 62.400 ;
      RECT 284.500 62.000 297.700 62.400 ;
      RECT 298.300 62.000 311.500 62.400 ;
      RECT 293.940 58.450 297.600 58.830 ;
      RECT 256.900 62.800 270.100 63.200 ;
      RECT 270.700 62.800 283.900 63.200 ;
      RECT 284.500 62.800 297.700 63.200 ;
      RECT 298.300 62.800 311.500 63.200 ;
      RECT 301.240 58.450 305.400 58.830 ;
      RECT 307.740 58.450 311.400 58.830 ;
      RECT 308.120 65.730 310.550 66.110 ;
      RECT 294.320 65.730 296.750 66.110 ;
      RECT 246.320 65.730 249.120 66.110 ;
      RECT 252.920 65.730 255.350 66.110 ;
      RECT 260.120 65.730 262.920 66.110 ;
      RECT 266.720 65.730 269.150 66.110 ;
      RECT 273.920 65.730 276.720 66.110 ;
      RECT 280.520 65.730 282.950 66.110 ;
      RECT 287.720 65.730 290.520 66.110 ;
      RECT 174.775 95.180 176.025 95.380 ;
      RECT 171.895 85.100 177.465 85.300 ;
      RECT 164.215 95.600 177.945 95.800 ;
      RECT 190.840 58.450 195.000 58.830 ;
      RECT 197.340 58.450 201.000 58.830 ;
      RECT 173.815 82.160 179.865 82.360 ;
      RECT 187.900 62.000 201.100 62.400 ;
      RECT 169.495 96.440 173.625 96.640 ;
      RECT 201.700 62.000 214.900 62.400 ;
      RECT 215.500 62.000 228.700 62.400 ;
      RECT 229.300 62.000 242.500 62.400 ;
      RECT 173.335 82.580 177.945 82.780 ;
      RECT 204.640 58.450 208.800 58.830 ;
      RECT 211.140 58.450 214.800 58.830 ;
      RECT 165.655 86.780 167.385 86.980 ;
      RECT 166.135 83.000 168.345 83.200 ;
      RECT 170.455 98.955 171.225 99.165 ;
      RECT 187.900 62.800 201.100 63.200 ;
      RECT 201.700 62.800 214.900 63.200 ;
      RECT 215.500 62.800 228.700 63.200 ;
      RECT 164.695 99.800 174.105 100.000 ;
      RECT 229.300 62.800 242.500 63.200 ;
      RECT 171.895 83.000 179.385 83.200 ;
      RECT 168.055 100.220 171.225 100.420 ;
      RECT 218.440 58.450 222.600 58.830 ;
      RECT 170.990 101.055 171.705 101.265 ;
      RECT 167.095 101.475 176.505 101.685 ;
      RECT 168.055 87.615 172.665 87.825 ;
      RECT 166.135 101.895 173.625 102.105 ;
      RECT 166.615 102.320 170.265 102.520 ;
      RECT 169.015 88.040 173.145 88.240 ;
      RECT 171.895 102.320 174.105 102.940 ;
      RECT 187.900 60.400 201.100 60.800 ;
      RECT 165.655 103.160 171.705 103.360 ;
      RECT 201.700 60.400 214.900 60.800 ;
      RECT 168.055 103.160 181.305 103.780 ;
      RECT 173.815 104.420 181.785 104.620 ;
      RECT 170.935 104.835 171.705 105.045 ;
      RECT 215.500 60.400 228.700 60.800 ;
      RECT 229.300 60.400 242.500 60.800 ;
      RECT 224.940 58.450 228.600 58.830 ;
      RECT 191.120 65.730 193.920 66.110 ;
      RECT 197.720 65.730 200.150 66.110 ;
      RECT 204.920 65.730 207.720 66.110 ;
      RECT 211.520 65.730 213.950 66.110 ;
      RECT 218.720 65.730 221.520 66.110 ;
      RECT 225.320 65.730 227.750 66.110 ;
      RECT 232.520 65.730 235.320 66.110 ;
      RECT 239.120 65.730 241.550 66.110 ;
      RECT 232.240 58.450 236.400 58.830 ;
      RECT 238.740 58.450 242.400 58.830 ;
      RECT 172.855 81.740 178.905 81.940 ;
      RECT 169.550 81.735 170.265 81.945 ;
      RECT 170.935 81.735 171.650 81.945 ;
      RECT 173.815 84.260 177.465 84.460 ;
      RECT 166.135 94.755 170.745 94.965 ;
      RECT 170.880 52.900 171.280 53.300 ;
      RECT 171.840 52.900 172.240 53.300 ;
      RECT 172.800 52.900 173.200 53.300 ;
      RECT 173.760 52.900 174.160 53.300 ;
      RECT 174.720 52.900 175.120 53.300 ;
      RECT 171.440 26.450 175.100 26.830 ;
      RECT 215.600 52.500 216.000 52.900 ;
      RECT 227.630 26.380 230.080 26.780 ;
      RECT 164.160 52.900 164.560 53.300 ;
      RECT 171.820 33.730 174.250 34.110 ;
      RECT 233.510 26.620 235.960 27.020 ;
      RECT 219.250 35.095 219.950 35.705 ;
      RECT 221.930 26.380 224.380 26.780 ;
      RECT 188.900 42.830 189.600 43.230 ;
      RECT 197.400 43.650 230.700 44.050 ;
      RECT 199.600 44.470 244.500 44.870 ;
      RECT 229.400 52.500 229.800 52.900 ;
      RECT 165.120 52.900 165.520 53.300 ;
      RECT 243.200 52.500 243.600 52.900 ;
      RECT 187.200 41.190 216.900 41.590 ;
      RECT 188.100 42.010 203.100 42.410 ;
      RECT 166.080 52.900 166.480 53.300 ;
      RECT 167.040 52.900 167.440 53.300 ;
      RECT 168.000 52.900 168.400 53.300 ;
      RECT 218.900 30.000 231.600 30.400 ;
      RECT 168.960 52.900 169.360 53.300 ;
      RECT 169.920 52.900 170.320 53.300 ;
      RECT 239.110 26.630 241.060 27.030 ;
      RECT 248.310 26.630 250.260 27.030 ;
      RECT 252.910 26.630 254.860 27.030 ;
      RECT 245.900 30.800 253.500 31.200 ;
      RECT 317.440 42.420 320.100 42.820 ;
      RECT 257.000 52.500 257.400 52.900 ;
      RECT 270.800 52.500 271.200 52.900 ;
      RECT 284.600 52.500 285.000 52.900 ;
      RECT 322.440 42.420 325.100 42.820 ;
    LAYER Metal4 ;
      RECT 148.420 79.595 148.620 109.705 ;
      RECT 157.540 87.575 157.740 109.705 ;
      RECT 142.660 88.835 142.860 110.545 ;
      RECT 170.980 81.695 171.180 110.965 ;
      RECT 144.580 91.775 144.780 113.065 ;
      RECT 148.900 81.695 149.100 113.485 ;
      RECT 150.820 105.215 151.020 113.485 ;
      RECT 151.780 82.535 151.980 113.485 ;
      RECT 170.020 81.695 170.220 113.485 ;
      RECT 172.420 87.575 172.620 114.325 ;
      RECT 149.860 95.975 150.060 115.165 ;
      RECT 147.940 97.235 148.140 117.265 ;
      RECT 149.380 105.635 149.580 118.525 ;
      RECT 160.420 77.915 160.620 118.945 ;
      RECT 146.500 99.755 146.700 120.205 ;
      RECT 153.220 90.095 153.420 121.045 ;
      RECT 168.580 94.715 168.780 123.565 ;
      RECT 167.140 101.435 167.340 130.705 ;
      RECT 153.700 95.975 153.900 134.065 ;
      RECT 166.180 101.855 166.380 142.045 ;
      RECT 314.100 49.900 314.500 186.900 ;
      RECT 219.305 120.400 219.595 120.600 ;
      RECT 225.305 120.400 225.595 120.600 ;
      RECT 231.305 120.400 231.595 120.600 ;
      RECT 237.305 120.400 237.595 120.600 ;
      RECT 243.305 120.400 243.595 120.600 ;
      RECT 249.305 120.400 249.595 120.600 ;
      RECT 255.305 120.400 255.595 120.600 ;
      RECT 262.605 120.400 262.895 120.600 ;
      RECT 268.605 120.400 268.895 120.600 ;
      RECT 274.605 120.400 274.895 120.600 ;
      RECT 280.605 120.400 280.895 120.600 ;
      RECT 286.605 120.400 286.895 120.600 ;
      RECT 292.605 120.400 292.895 120.600 ;
      RECT 298.605 120.400 298.895 120.600 ;
      RECT 304.605 120.400 304.895 120.600 ;
      RECT 159.460 116.555 159.660 118.525 ;
      RECT 159.940 114.875 160.140 121.465 ;
      RECT 165.700 118.655 165.900 121.465 ;
      RECT 238.605 122.000 238.895 122.200 ;
      RECT 244.605 122.000 244.895 122.200 ;
      RECT 250.605 122.000 250.895 122.200 ;
      RECT 256.605 122.000 256.895 122.200 ;
      RECT 261.305 122.000 261.595 122.200 ;
      RECT 267.305 122.000 267.595 122.200 ;
      RECT 273.305 122.000 273.595 122.200 ;
      RECT 279.305 122.000 279.595 122.200 ;
      RECT 161.160 112.355 163.000 112.645 ;
      RECT 226.605 123.600 226.895 123.800 ;
      RECT 232.605 123.600 232.895 123.800 ;
      RECT 285.305 123.600 285.595 123.800 ;
      RECT 291.305 123.600 291.595 123.800 ;
      RECT 158.980 121.595 159.180 125.245 ;
      RECT 220.605 125.200 220.895 125.400 ;
      RECT 297.305 125.200 297.595 125.400 ;
      RECT 303.305 126.800 303.595 127.000 ;
      RECT 161.160 127.475 163.000 127.765 ;
      RECT 214.605 128.400 214.895 128.600 ;
      RECT 175.300 114.035 175.500 119.365 ;
      RECT 195.050 111.495 195.750 112.105 ;
      RECT 161.160 135.035 163.000 135.325 ;
      RECT 195.050 137.495 195.750 138.105 ;
      RECT 171.460 114.035 171.660 141.625 ;
      RECT 161.160 119.915 163.000 120.205 ;
      RECT 161.160 142.595 163.000 142.885 ;
      RECT 192.850 143.495 193.550 144.105 ;
      RECT 163.780 142.595 163.980 145.825 ;
      RECT 170.500 126.635 170.700 148.765 ;
      RECT 192.850 149.495 193.550 150.105 ;
      RECT 161.160 150.155 163.000 150.445 ;
      RECT 163.300 144.275 163.500 151.285 ;
      RECT 158.980 147.215 159.180 151.705 ;
      RECT 190.650 155.495 191.350 156.105 ;
      RECT 159.460 145.535 159.660 156.325 ;
      RECT 161.160 157.715 163.000 158.005 ;
      RECT 163.780 149.315 163.980 159.265 ;
      RECT 164.740 145.535 164.940 159.685 ;
      RECT 160.420 125.795 160.620 160.945 ;
      RECT 190.650 161.495 191.350 162.105 ;
      RECT 161.160 165.275 163.000 165.565 ;
      RECT 190.650 167.495 191.350 168.105 ;
      RECT 190.650 173.495 191.350 174.105 ;
      RECT 213.305 120.400 213.595 120.600 ;
      RECT 169.180 189.295 169.880 189.905 ;
      RECT 313.950 189.295 314.650 189.905 ;
      RECT 154.960 123.695 156.800 123.985 ;
      RECT 68.605 120.400 68.895 120.600 ;
      RECT 26.605 125.200 26.895 125.400 ;
      RECT 103.305 125.200 103.595 125.400 ;
      RECT 74.605 120.400 74.895 120.600 ;
      RECT 80.605 120.400 80.895 120.600 ;
      RECT 145.060 110.255 145.260 126.085 ;
      RECT 20.605 126.800 20.895 127.000 ;
      RECT 86.605 120.400 86.895 120.600 ;
      RECT 92.605 120.400 92.895 120.600 ;
      RECT 109.305 128.400 109.595 128.600 ;
      RECT 98.605 120.400 98.895 120.600 ;
      RECT 157.540 121.595 157.740 129.025 ;
      RECT 104.605 120.400 104.895 120.600 ;
      RECT 154.960 131.255 156.800 131.545 ;
      RECT 157.060 115.295 157.260 133.225 ;
      RECT 44.605 122.000 44.895 122.200 ;
      RECT 50.605 122.000 50.895 122.200 ;
      RECT 128.450 137.495 129.150 138.105 ;
      RECT 56.605 122.000 56.895 122.200 ;
      RECT 154.960 138.815 156.800 139.105 ;
      RECT 151.780 114.455 151.980 141.625 ;
      RECT 62.605 122.000 62.895 122.200 ;
      RECT 67.305 122.000 67.595 122.200 ;
      RECT 73.305 122.000 73.595 122.200 ;
      RECT 157.060 133.775 157.260 143.305 ;
      RECT 130.650 143.495 131.350 144.105 ;
      RECT 79.305 122.000 79.595 122.200 ;
      RECT 85.305 122.000 85.595 122.200 ;
      RECT 154.960 146.375 156.800 146.665 ;
      RECT 110.605 120.400 110.895 120.600 ;
      RECT 130.650 149.495 131.350 150.105 ;
      RECT 154.960 116.135 156.800 116.425 ;
      RECT 150.340 109.835 150.540 113.905 ;
      RECT 128.450 111.495 129.150 112.105 ;
      RECT 154.960 108.575 156.800 108.865 ;
      RECT 154.960 153.935 156.800 154.225 ;
      RECT 132.850 155.495 133.550 156.105 ;
      RECT 19.305 120.400 19.595 120.600 ;
      RECT 25.305 120.400 25.595 120.600 ;
      RECT 150.820 117.395 151.980 156.745 ;
      RECT 31.305 120.400 31.595 120.600 ;
      RECT 154.180 114.035 154.860 122.305 ;
      RECT 37.305 120.400 37.595 120.600 ;
      RECT 32.605 123.600 32.895 123.800 ;
      RECT 154.960 161.495 156.800 161.785 ;
      RECT 132.850 161.495 133.550 162.105 ;
      RECT 38.605 123.600 38.895 123.800 ;
      RECT 91.305 123.600 91.595 123.800 ;
      RECT 132.850 167.495 133.550 168.105 ;
      RECT 97.305 123.600 97.595 123.800 ;
      RECT 154.960 169.055 156.800 169.345 ;
      RECT 132.850 173.495 133.550 174.105 ;
      RECT 43.305 120.400 43.595 120.600 ;
      RECT 2.500 174.500 135.100 174.900 ;
      RECT 49.305 120.400 49.595 120.600 ;
      RECT 10.650 189.295 11.350 189.905 ;
      RECT 154.330 189.295 155.030 189.905 ;
      RECT 55.305 120.400 55.595 120.600 ;
      RECT 61.305 120.400 61.595 120.600 ;
      RECT 6.250 214.395 6.950 215.005 ;
      RECT 148.800 2.500 149.200 53.300 ;
      RECT 149.760 2.500 150.160 53.300 ;
      RECT 150.720 2.500 151.120 53.300 ;
      RECT 151.680 2.500 152.080 53.300 ;
      RECT 152.640 2.500 153.040 53.300 ;
      RECT 153.600 2.500 154.000 53.300 ;
      RECT 154.560 2.500 154.960 53.300 ;
      RECT 155.520 2.500 155.920 53.300 ;
      RECT 156.480 2.500 156.880 53.300 ;
      RECT 157.440 2.500 157.840 53.300 ;
      RECT 1.250 69.095 1.950 69.705 ;
      RECT 10.800 38.000 11.200 71.400 ;
      RECT 115.400 39.700 115.800 72.150 ;
      RECT 117.600 41.000 118.000 72.150 ;
      RECT 119.800 42.300 120.200 72.150 ;
      RECT 122.000 43.600 122.400 72.150 ;
      RECT 124.200 44.900 124.600 72.150 ;
      RECT 126.400 46.200 126.800 72.150 ;
      RECT 128.600 47.500 129.000 72.150 ;
      RECT 130.800 48.800 131.200 72.150 ;
      RECT 133.000 50.100 133.400 72.150 ;
      RECT 132.850 75.495 133.550 76.105 ;
      RECT 132.850 81.495 133.550 82.105 ;
      RECT 154.960 85.895 156.800 86.185 ;
      RECT 132.850 87.495 133.550 88.105 ;
      RECT 154.960 93.455 156.800 93.745 ;
      RECT 132.850 93.495 133.550 94.105 ;
      RECT 149.380 89.255 149.580 95.845 ;
      RECT 130.650 99.495 131.350 100.105 ;
      RECT 154.960 101.015 156.800 101.305 ;
      RECT 152.740 86.735 152.940 104.245 ;
      RECT 143.140 98.915 143.340 104.665 ;
      RECT 157.060 81.695 157.260 105.925 ;
      RECT 130.650 105.495 131.350 106.105 ;
      RECT 92.550 29.095 93.250 29.705 ;
      RECT 92.050 35.095 92.750 35.705 ;
      RECT 21.800 19.500 22.200 52.900 ;
      RECT 35.600 18.200 36.000 52.900 ;
      RECT 49.400 16.900 49.800 52.900 ;
      RECT 63.200 15.600 63.600 52.900 ;
      RECT 77.000 14.300 77.400 52.900 ;
      RECT 90.800 13.000 91.200 52.900 ;
      RECT 104.600 11.700 105.000 52.900 ;
      RECT 118.400 10.400 118.800 52.900 ;
      RECT 147.840 2.500 148.240 53.300 ;
      RECT 199.600 71.700 200.000 72.100 ;
      RECT 201.800 71.700 202.200 72.100 ;
      RECT 204.000 71.700 204.400 72.100 ;
      RECT 206.200 71.700 206.600 72.100 ;
      RECT 208.400 71.700 208.800 72.100 ;
      RECT 229.400 3.900 229.800 52.900 ;
      RECT 243.200 5.200 243.600 52.900 ;
      RECT 257.000 6.500 257.400 52.900 ;
      RECT 270.800 7.800 271.200 52.900 ;
      RECT 284.600 9.100 285.000 52.900 ;
      RECT 201.800 45.290 202.200 45.690 ;
      RECT 204.000 46.110 204.400 46.510 ;
      RECT 206.200 46.930 206.600 47.330 ;
      RECT 208.400 47.750 208.800 48.150 ;
      RECT 218.750 29.095 219.450 29.705 ;
      RECT 190.650 75.495 191.350 76.105 ;
      RECT 175.400 2.500 175.800 29.600 ;
      RECT 190.650 81.495 191.350 82.105 ;
      RECT 161.160 82.115 163.000 82.405 ;
      RECT 219.250 35.095 219.950 35.705 ;
      RECT 162.820 82.955 163.020 87.445 ;
      RECT 187.200 41.190 187.600 41.590 ;
      RECT 190.650 87.495 191.350 88.105 ;
      RECT 163.300 80.015 163.500 88.705 ;
      RECT 164.260 82.955 164.460 89.545 ;
      RECT 161.160 89.675 163.000 89.965 ;
      RECT 188.100 42.010 188.500 42.410 ;
      RECT 189.200 42.830 189.600 43.230 ;
      RECT 190.650 93.495 191.350 94.105 ;
      RECT 197.400 43.650 197.800 44.050 ;
      RECT 161.160 97.235 163.000 97.525 ;
      RECT 170.500 90.095 170.700 99.205 ;
      RECT 158.400 2.500 158.800 53.300 ;
      RECT 192.850 99.495 193.550 100.105 ;
      RECT 159.360 0.000 159.760 53.300 ;
      RECT 160.320 1.300 160.720 53.300 ;
      RECT 161.280 2.600 161.680 53.300 ;
      RECT 161.160 104.795 163.000 105.085 ;
      RECT 171.460 101.015 171.660 105.085 ;
      RECT 162.240 3.900 162.640 53.300 ;
      RECT 158.500 79.595 158.700 105.925 ;
      RECT 163.200 5.200 163.600 53.300 ;
      RECT 192.850 105.495 193.550 106.105 ;
      RECT 164.160 6.500 164.560 53.300 ;
      RECT 165.120 7.800 165.520 53.300 ;
      RECT 166.080 9.100 166.480 53.300 ;
      RECT 167.040 10.400 167.440 53.300 ;
      RECT 168.000 11.700 168.400 53.300 ;
      RECT 168.960 13.000 169.360 53.300 ;
      RECT 169.920 14.300 170.320 53.300 ;
      RECT 170.880 15.600 171.280 53.300 ;
      RECT 171.840 16.900 172.240 53.300 ;
      RECT 172.800 18.200 173.200 53.300 ;
      RECT 173.760 19.500 174.160 53.300 ;
      RECT 174.720 48.850 175.120 53.300 ;
      RECT 190.800 0.000 191.200 60.800 ;
      RECT 202.900 1.300 203.300 60.800 ;
      RECT 199.600 44.470 200.000 44.870 ;
      RECT 187.200 69.700 187.600 70.100 ;
      RECT 188.100 70.600 188.500 71.000 ;
      RECT 215.600 2.600 216.000 52.900 ;
      RECT 189.200 71.500 189.600 71.900 ;
      RECT 197.400 71.700 197.800 72.100 ;
    LAYER Metal5 ;
      RECT 42.460 116.100 45.800 122.460 ;
      RECT 48.460 116.100 51.800 122.460 ;
      RECT 54.460 116.100 57.800 122.460 ;
      RECT 60.460 116.100 63.800 122.460 ;
      RECT 260.400 116.100 263.740 122.460 ;
      RECT 266.400 116.100 269.740 122.460 ;
      RECT 272.400 116.100 275.740 122.460 ;
      RECT 278.400 116.100 281.740 122.460 ;
      RECT 30.460 116.100 33.800 124.060 ;
      RECT 36.460 116.100 39.800 124.060 ;
      RECT 284.400 116.100 287.740 124.060 ;
      RECT 290.400 116.100 293.740 124.060 ;
      RECT 24.460 116.100 27.800 125.660 ;
      RECT 296.400 116.100 299.740 125.660 ;
      RECT 18.460 116.100 21.800 127.260 ;
      RECT 302.400 116.100 305.740 127.260 ;
      RECT 18.460 120.140 21.800 133.440 ;
      RECT 24.460 120.140 27.800 133.440 ;
      RECT 30.460 120.140 33.800 133.440 ;
      RECT 36.460 120.140 39.800 133.440 ;
      RECT 42.460 120.140 45.800 133.440 ;
      RECT 48.460 120.140 51.800 133.440 ;
      RECT 54.460 120.140 57.800 133.440 ;
      RECT 60.460 120.140 63.800 133.440 ;
      RECT 260.400 120.140 263.740 133.440 ;
      RECT 266.400 120.140 269.740 133.440 ;
      RECT 272.400 120.140 275.740 133.440 ;
      RECT 278.400 120.140 281.740 133.440 ;
      RECT 284.400 120.140 287.740 133.440 ;
      RECT 290.400 120.140 293.740 133.440 ;
      RECT 296.400 120.140 299.740 133.440 ;
      RECT 302.400 120.140 305.740 133.440 ;
      RECT 254.400 121.740 257.740 133.440 ;
      RECT 161.115 127.310 163.045 127.930 ;
      RECT 212.400 128.140 215.740 133.440 ;
      RECT 218.400 124.940 221.740 133.440 ;
      RECT 224.400 123.340 227.740 133.440 ;
      RECT 230.400 123.340 233.740 133.440 ;
      RECT 236.400 121.740 239.740 133.440 ;
      RECT 242.400 121.740 245.740 133.440 ;
      RECT 248.400 121.740 251.740 133.440 ;
      RECT 161.115 134.870 163.045 135.490 ;
      RECT 194.400 136.100 305.740 139.440 ;
      RECT 161.115 142.430 163.045 143.050 ;
      RECT 192.200 142.100 305.740 145.440 ;
      RECT 161.115 149.990 163.045 150.610 ;
      RECT 192.200 148.100 305.740 151.440 ;
      RECT 190.000 154.100 305.740 157.440 ;
      RECT 161.115 157.550 163.045 158.170 ;
      RECT 190.000 160.100 305.740 163.440 ;
      RECT 161.115 165.110 163.045 165.730 ;
      RECT 190.000 166.100 305.740 169.440 ;
      RECT 190.000 172.100 305.740 175.440 ;
      RECT 169.180 189.290 169.880 189.910 ;
      RECT 313.950 189.290 314.650 189.910 ;
      RECT 102.460 124.940 105.800 133.440 ;
      RECT 18.460 142.100 132.000 145.440 ;
      RECT 108.460 128.140 111.800 133.440 ;
      RECT 154.915 146.210 156.845 146.830 ;
      RECT 154.915 123.530 156.845 124.150 ;
      RECT 18.460 148.100 132.000 151.440 ;
      RECT 154.915 131.090 156.845 131.710 ;
      RECT 154.915 153.770 156.845 154.390 ;
      RECT 18.460 154.100 134.200 157.440 ;
      RECT 66.460 121.740 69.800 133.440 ;
      RECT 72.460 121.740 75.800 133.440 ;
      RECT 154.915 161.330 156.845 161.950 ;
      RECT 18.460 160.100 134.200 163.440 ;
      RECT 78.460 121.740 81.800 133.440 ;
      RECT 84.460 121.740 87.800 133.440 ;
      RECT 18.460 166.100 134.200 169.440 ;
      RECT 90.460 123.340 93.800 133.440 ;
      RECT 154.915 168.890 156.845 169.510 ;
      RECT 18.460 172.100 134.200 175.440 ;
      RECT 154.915 138.650 156.845 139.270 ;
      RECT 10.650 189.290 11.350 189.910 ;
      RECT 154.330 189.290 155.030 189.910 ;
      RECT 18.460 136.100 129.800 139.440 ;
      RECT 96.460 123.340 99.800 133.440 ;
      RECT 6.250 214.390 6.950 215.010 ;
      RECT 18.460 104.100 132.000 107.440 ;
      RECT 154.915 108.410 156.845 109.030 ;
      RECT 18.460 110.100 129.800 113.440 ;
      RECT 154.915 115.970 156.845 116.590 ;
      RECT 66.460 116.100 69.800 120.860 ;
      RECT 72.460 116.100 75.800 120.860 ;
      RECT 78.460 116.100 81.800 120.860 ;
      RECT 84.460 116.100 87.800 120.860 ;
      RECT 90.460 116.100 93.800 120.860 ;
      RECT 96.460 116.100 99.800 120.860 ;
      RECT 102.460 116.100 105.800 120.860 ;
      RECT 108.460 116.100 111.800 120.860 ;
      RECT 92.050 35.090 92.750 35.710 ;
      RECT 92.400 27.500 135.000 38.640 ;
      RECT 1.250 69.090 1.950 69.710 ;
      RECT 18.460 74.100 134.200 77.440 ;
      RECT 18.460 80.100 134.200 83.440 ;
      RECT 154.915 85.730 156.845 86.350 ;
      RECT 18.460 86.100 134.200 89.440 ;
      RECT 154.915 93.290 156.845 93.910 ;
      RECT 18.460 92.100 134.200 95.440 ;
      RECT 18.460 98.100 132.000 101.440 ;
      RECT 154.915 100.850 156.845 101.470 ;
      RECT 190.000 74.100 305.740 77.440 ;
      RECT 161.115 81.950 163.045 82.570 ;
      RECT 219.250 35.090 219.950 35.710 ;
      RECT 190.000 80.100 305.740 83.440 ;
      RECT 187.200 41.170 187.600 70.120 ;
      RECT 188.100 41.990 188.500 71.020 ;
      RECT 190.000 86.100 305.740 89.440 ;
      RECT 161.115 89.510 163.045 90.130 ;
      RECT 212.400 116.100 215.740 120.860 ;
      RECT 218.400 116.100 221.740 120.860 ;
      RECT 224.400 116.100 227.740 120.860 ;
      RECT 230.400 116.100 233.740 120.860 ;
      RECT 236.400 116.100 239.740 120.860 ;
      RECT 242.400 116.100 245.740 120.860 ;
      RECT 248.400 116.100 251.740 120.860 ;
      RECT 254.400 116.100 257.740 120.860 ;
      RECT 189.200 42.810 189.600 71.920 ;
      RECT 197.400 43.630 197.800 72.120 ;
      RECT 190.000 92.100 305.740 95.440 ;
      RECT 161.115 97.070 163.045 97.690 ;
      RECT 199.600 44.450 200.000 72.120 ;
      RECT 192.200 98.100 305.740 101.440 ;
      RECT 201.800 45.270 202.200 72.120 ;
      RECT 161.115 104.630 163.045 105.250 ;
      RECT 204.000 46.090 204.400 72.120 ;
      RECT 192.200 104.100 305.740 107.440 ;
      RECT 206.200 46.910 206.600 72.120 ;
      RECT 161.115 112.190 163.045 112.810 ;
      RECT 208.400 47.730 208.800 72.120 ;
      RECT 194.400 110.100 305.740 113.440 ;
      RECT 177.000 27.500 219.600 38.640 ;
      RECT 161.115 119.750 163.045 120.370 ;
    LAYER TopMetal1 ;
      RECT 91.100 28.660 135.000 37.480 ;
      RECT 177.000 28.660 220.900 37.480 ;
      RECT 9.800 74.700 155.880 190.800 ;
      RECT 168.330 74.700 315.500 190.800 ;
      RECT 0.400 68.300 2.800 210.500 ;
      RECT 154.780 82.040 159.720 210.500 ;
      RECT 5.650 213.750 7.550 215.650 ;
      RECT 160.980 81.630 163.560 216.100 ;
    LAYER TopMetal2 ;
  END
END oa_sar8_core16
END LIBRARY
